VERSION 5.7 ;
  NOWIREEXTENSIONATPIN ON ;
  DIVIDERCHAR "/" ;
  BUSBITCHARS "[]" ;
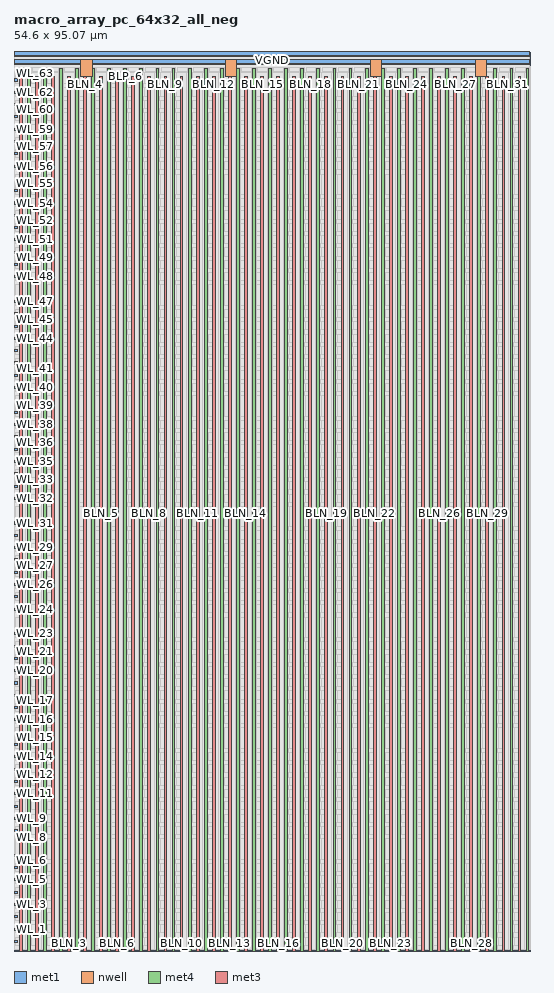
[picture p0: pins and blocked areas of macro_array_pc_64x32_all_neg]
MACRO macro_array_pc_64x32_all_neg
  CLASS BLOCK ;
  FOREIGN macro_array_pc_64x32_all_neg ;
  ORIGIN 0.000 0.000 ;
  SIZE 54.600 BY 95.070 ;
  PIN VPWR
    USE POWER ;
    PORT
      LAYER met1 ;
        RECT 0.000 93.750 54.500 94.150 ;
    END
    PORT
      LAYER nwell ;
        RECT 7.050 92.400 8.250 94.120 ;
    END
    PORT
      LAYER nwell ;
        RECT 22.350 92.400 23.550 94.120 ;
    END
    PORT
      LAYER nwell ;
        RECT 37.650 92.400 38.850 94.120 ;
    END
    PORT
      LAYER nwell ;
        RECT 48.700 92.400 49.900 94.120 ;
    END
    PORT
      LAYER met4 ;
        RECT 0.000 93.680 54.500 94.220 ;
    END
  END VPWR
  PIN VGND
    USE GROUND ;
    PORT
      LAYER met1 ;
        RECT 0.000 94.600 54.500 95.000 ;
    END
    PORT
      LAYER met4 ;
        RECT 0.000 94.530 54.500 95.070 ;
    END
  END VGND
  PIN BLP_0
    ANTENNADIFFAREA 0.121800 ;
    PORT
      LAYER met4 ;
        RECT 1.400 0.000 1.700 93.250 ;
    END
  END BLP_0
  PIN BLN_0
    ANTENNADIFFAREA 7.795200 ;
    PORT
      LAYER met3 ;
        RECT 0.550 0.000 0.850 92.400 ;
    END
  END BLN_0
  PIN BLP_1
    ANTENNADIFFAREA 0.121800 ;
    PORT
      LAYER met4 ;
        RECT 3.100 0.000 3.400 93.250 ;
    END
  END BLP_1
  PIN BLN_1
    ANTENNADIFFAREA 7.795200 ;
    PORT
      LAYER met3 ;
        RECT 2.250 0.000 2.550 92.400 ;
    END
  END BLN_1
  PIN BLP_2
    ANTENNADIFFAREA 0.121800 ;
    PORT
      LAYER met4 ;
        RECT 4.800 0.000 5.100 93.250 ;
    END
  END BLP_2
  PIN BLN_2
    ANTENNADIFFAREA 7.795200 ;
    PORT
      LAYER met3 ;
        RECT 3.950 0.000 4.250 92.400 ;
    END
  END BLN_2
  PIN BLP_3
    ANTENNADIFFAREA 0.121800 ;
    PORT
      LAYER met4 ;
        RECT 6.500 0.000 6.800 93.250 ;
    END
  END BLP_3
  PIN BLN_3
    ANTENNADIFFAREA 7.795200 ;
    PORT
      LAYER met3 ;
        RECT 5.650 0.000 5.950 92.400 ;
    END
  END BLN_3
  PIN BLP_4
    ANTENNADIFFAREA 0.121800 ;
    PORT
      LAYER met4 ;
        RECT 8.200 0.000 8.500 93.250 ;
    END
  END BLP_4
  PIN BLN_4
    ANTENNADIFFAREA 7.795200 ;
    PORT
      LAYER met3 ;
        RECT 7.350 0.000 7.650 92.400 ;
    END
  END BLN_4
  PIN BLP_5
    ANTENNADIFFAREA 0.121800 ;
    PORT
      LAYER met4 ;
        RECT 9.900 0.000 10.200 93.250 ;
    END
  END BLP_5
  PIN BLN_5
    ANTENNADIFFAREA 7.795200 ;
    PORT
      LAYER met3 ;
        RECT 9.050 0.000 9.350 92.400 ;
    END
  END BLN_5
  PIN BLP_6
    ANTENNADIFFAREA 0.121800 ;
    PORT
      LAYER met4 ;
        RECT 11.600 0.000 11.900 93.250 ;
    END
  END BLP_6
  PIN BLN_6
    ANTENNADIFFAREA 7.795200 ;
    PORT
      LAYER met3 ;
        RECT 10.750 0.000 11.050 92.400 ;
    END
  END BLN_6
  PIN BLP_7
    ANTENNADIFFAREA 0.121800 ;
    PORT
      LAYER met4 ;
        RECT 13.300 0.000 13.600 93.250 ;
    END
  END BLP_7
  PIN BLN_7
    ANTENNADIFFAREA 7.795200 ;
    PORT
      LAYER met3 ;
        RECT 12.450 0.000 12.750 92.400 ;
    END
  END BLN_7
  PIN BLP_8
    ANTENNADIFFAREA 0.121800 ;
    PORT
      LAYER met4 ;
        RECT 15.000 0.000 15.300 93.250 ;
    END
  END BLP_8
  PIN BLN_8
    ANTENNADIFFAREA 7.795200 ;
    PORT
      LAYER met3 ;
        RECT 14.150 0.000 14.450 92.400 ;
    END
  END BLN_8
  PIN BLP_9
    ANTENNADIFFAREA 0.121800 ;
    PORT
      LAYER met4 ;
        RECT 16.700 0.000 17.000 93.250 ;
    END
  END BLP_9
  PIN BLN_9
    ANTENNADIFFAREA 7.795200 ;
    PORT
      LAYER met3 ;
        RECT 15.850 0.000 16.150 92.400 ;
    END
  END BLN_9
  PIN BLP_10
    ANTENNADIFFAREA 0.121800 ;
    PORT
      LAYER met4 ;
        RECT 18.400 0.000 18.700 93.250 ;
    END
  END BLP_10
  PIN BLN_10
    ANTENNADIFFAREA 7.795200 ;
    PORT
      LAYER met3 ;
        RECT 17.550 0.000 17.850 92.400 ;
    END
  END BLN_10
  PIN BLP_11
    ANTENNADIFFAREA 0.121800 ;
    PORT
      LAYER met4 ;
        RECT 20.100 0.000 20.400 93.250 ;
    END
  END BLP_11
  PIN BLN_11
    ANTENNADIFFAREA 7.795200 ;
    PORT
      LAYER met3 ;
        RECT 19.250 0.000 19.550 92.400 ;
    END
  END BLN_11
  PIN BLP_12
    ANTENNADIFFAREA 0.121800 ;
    PORT
      LAYER met4 ;
        RECT 21.800 0.000 22.100 93.250 ;
    END
  END BLP_12
  PIN BLN_12
    ANTENNADIFFAREA 7.795200 ;
    PORT
      LAYER met3 ;
        RECT 20.950 0.000 21.250 92.400 ;
    END
  END BLN_12
  PIN BLP_13
    ANTENNADIFFAREA 0.121800 ;
    PORT
      LAYER met4 ;
        RECT 23.500 0.000 23.800 93.250 ;
    END
  END BLP_13
  PIN BLN_13
    ANTENNADIFFAREA 7.795200 ;
    PORT
      LAYER met3 ;
        RECT 22.650 0.000 22.950 92.400 ;
    END
  END BLN_13
  PIN BLP_14
    ANTENNADIFFAREA 0.121800 ;
    PORT
      LAYER met4 ;
        RECT 25.200 0.000 25.500 93.250 ;
    END
  END BLP_14
  PIN BLN_14
    ANTENNADIFFAREA 7.795200 ;
    PORT
      LAYER met3 ;
        RECT 24.350 0.000 24.650 92.400 ;
    END
  END BLN_14
  PIN BLP_15
    ANTENNADIFFAREA 0.121800 ;
    PORT
      LAYER met4 ;
        RECT 26.900 0.000 27.200 93.250 ;
    END
  END BLP_15
  PIN BLN_15
    ANTENNADIFFAREA 7.795200 ;
    PORT
      LAYER met3 ;
        RECT 26.050 0.000 26.350 92.400 ;
    END
  END BLN_15
  PIN BLP_16
    ANTENNADIFFAREA 0.121800 ;
    PORT
      LAYER met4 ;
        RECT 28.600 0.000 28.900 93.250 ;
    END
  END BLP_16
  PIN BLN_16
    ANTENNADIFFAREA 7.795200 ;
    PORT
      LAYER met3 ;
        RECT 27.750 0.000 28.050 92.400 ;
    END
  END BLN_16
  PIN BLP_17
    ANTENNADIFFAREA 0.121800 ;
    PORT
      LAYER met4 ;
        RECT 30.300 0.000 30.600 93.250 ;
    END
  END BLP_17
  PIN BLN_17
    ANTENNADIFFAREA 7.795200 ;
    PORT
      LAYER met3 ;
        RECT 29.450 0.000 29.750 92.400 ;
    END
  END BLN_17
  PIN BLP_18
    ANTENNADIFFAREA 0.121800 ;
    PORT
      LAYER met4 ;
        RECT 32.000 0.000 32.300 93.250 ;
    END
  END BLP_18
  PIN BLN_18
    ANTENNADIFFAREA 7.795200 ;
    PORT
      LAYER met3 ;
        RECT 31.150 0.000 31.450 92.400 ;
    END
  END BLN_18
  PIN BLP_19
    ANTENNADIFFAREA 0.121800 ;
    PORT
      LAYER met4 ;
        RECT 33.700 0.000 34.000 93.250 ;
    END
  END BLP_19
  PIN BLN_19
    ANTENNADIFFAREA 7.795200 ;
    PORT
      LAYER met3 ;
        RECT 32.850 0.000 33.150 92.400 ;
    END
  END BLN_19
  PIN BLP_20
    ANTENNADIFFAREA 0.121800 ;
    PORT
      LAYER met4 ;
        RECT 35.400 0.000 35.700 93.250 ;
    END
  END BLP_20
  PIN BLN_20
    ANTENNADIFFAREA 7.795200 ;
    PORT
      LAYER met3 ;
        RECT 34.550 0.000 34.850 92.400 ;
    END
  END BLN_20
  PIN BLP_21
    ANTENNADIFFAREA 0.121800 ;
    PORT
      LAYER met4 ;
        RECT 37.100 0.000 37.400 93.250 ;
    END
  END BLP_21
  PIN BLN_21
    ANTENNADIFFAREA 7.795200 ;
    PORT
      LAYER met3 ;
        RECT 36.250 0.000 36.550 92.400 ;
    END
  END BLN_21
  PIN BLP_22
    ANTENNADIFFAREA 0.121800 ;
    PORT
      LAYER met4 ;
        RECT 38.800 0.000 39.100 93.250 ;
    END
  END BLP_22
  PIN BLN_22
    ANTENNADIFFAREA 7.795200 ;
    PORT
      LAYER met3 ;
        RECT 37.950 0.000 38.250 92.400 ;
    END
  END BLN_22
  PIN BLP_23
    ANTENNADIFFAREA 0.121800 ;
    PORT
      LAYER met4 ;
        RECT 40.500 0.000 40.800 93.250 ;
    END
  END BLP_23
  PIN BLN_23
    ANTENNADIFFAREA 7.795200 ;
    PORT
      LAYER met3 ;
        RECT 39.650 0.000 39.950 92.400 ;
    END
  END BLN_23
  PIN BLP_24
    ANTENNADIFFAREA 0.121800 ;
    PORT
      LAYER met4 ;
        RECT 42.200 0.000 42.500 93.250 ;
    END
  END BLP_24
  PIN BLN_24
    ANTENNADIFFAREA 7.795200 ;
    PORT
      LAYER met3 ;
        RECT 41.350 0.000 41.650 92.400 ;
    END
  END BLN_24
  PIN BLP_25
    ANTENNADIFFAREA 0.121800 ;
    PORT
      LAYER met4 ;
        RECT 43.900 0.000 44.200 93.250 ;
    END
  END BLP_25
  PIN BLN_25
    ANTENNADIFFAREA 7.795200 ;
    PORT
      LAYER met3 ;
        RECT 43.050 0.000 43.350 92.400 ;
    END
  END BLN_25
  PIN BLP_26
    ANTENNADIFFAREA 0.121800 ;
    PORT
      LAYER met4 ;
        RECT 45.600 0.000 45.900 93.250 ;
    END
  END BLP_26
  PIN BLN_26
    ANTENNADIFFAREA 7.795200 ;
    PORT
      LAYER met3 ;
        RECT 44.750 0.000 45.050 92.400 ;
    END
  END BLN_26
  PIN BLP_27
    ANTENNADIFFAREA 0.121800 ;
    PORT
      LAYER met4 ;
        RECT 47.300 0.000 47.600 93.250 ;
    END
  END BLP_27
  PIN BLN_27
    ANTENNADIFFAREA 7.795200 ;
    PORT
      LAYER met3 ;
        RECT 46.450 0.000 46.750 92.400 ;
    END
  END BLN_27
  PIN BLP_28
    ANTENNADIFFAREA 0.121800 ;
    PORT
      LAYER met4 ;
        RECT 49.000 0.000 49.300 93.250 ;
    END
  END BLP_28
  PIN BLN_28
    ANTENNADIFFAREA 7.795200 ;
    PORT
      LAYER met3 ;
        RECT 48.150 0.000 48.450 92.400 ;
    END
  END BLN_28
  PIN BLP_29
    ANTENNADIFFAREA 0.121800 ;
    PORT
      LAYER met4 ;
        RECT 50.700 0.000 51.000 93.250 ;
    END
  END BLP_29
  PIN BLN_29
    ANTENNADIFFAREA 7.795200 ;
    PORT
      LAYER met3 ;
        RECT 49.850 0.000 50.150 92.400 ;
    END
  END BLN_29
  PIN BLP_30
    ANTENNADIFFAREA 0.121800 ;
    PORT
      LAYER met4 ;
        RECT 52.400 0.000 52.700 93.250 ;
    END
  END BLP_30
  PIN BLN_30
    ANTENNADIFFAREA 7.795200 ;
    PORT
      LAYER met3 ;
        RECT 51.550 0.000 51.850 92.400 ;
    END
  END BLN_30
  PIN BLP_31
    ANTENNADIFFAREA 0.121800 ;
    PORT
      LAYER met4 ;
        RECT 54.100 0.000 54.400 93.250 ;
    END
  END BLP_31
  PIN BLN_31
    ANTENNADIFFAREA 7.795200 ;
    PORT
      LAYER met3 ;
        RECT 53.250 0.000 53.550 92.400 ;
    END
  END BLN_31
  PIN WL_0
    ANTENNAGATEAREA 2.284800 ;
    PORT
      LAYER met1 ;
        RECT 0.000 0.900 0.390 1.120 ;
    END
  END WL_0
  PIN WL_1
    ANTENNAGATEAREA 2.284800 ;
    PORT
      LAYER met1 ;
        RECT 0.000 2.200 0.390 2.420 ;
    END
  END WL_1
  PIN WL_2
    ANTENNAGATEAREA 2.284800 ;
    PORT
      LAYER met1 ;
        RECT 0.000 3.500 0.390 3.720 ;
    END
  END WL_2
  PIN WL_3
    ANTENNAGATEAREA 2.284800 ;
    PORT
      LAYER met1 ;
        RECT 0.000 4.800 0.390 5.020 ;
    END
  END WL_3
  PIN WL_4
    ANTENNAGATEAREA 2.284800 ;
    PORT
      LAYER met1 ;
        RECT 0.000 6.100 0.390 6.320 ;
    END
  END WL_4
  PIN WL_5
    ANTENNAGATEAREA 2.284800 ;
    PORT
      LAYER met1 ;
        RECT 0.000 7.400 0.390 7.620 ;
    END
  END WL_5
  PIN WL_6
    ANTENNAGATEAREA 2.284800 ;
    PORT
      LAYER met1 ;
        RECT 0.000 8.700 0.390 8.920 ;
    END
  END WL_6
  PIN WL_7
    ANTENNAGATEAREA 2.284800 ;
    PORT
      LAYER met1 ;
        RECT 0.000 10.000 0.390 10.220 ;
    END
  END WL_7
  PIN WL_8
    ANTENNAGATEAREA 2.284800 ;
    PORT
      LAYER met1 ;
        RECT 0.000 12.600 0.390 12.820 ;
    END
  END WL_8
  PIN WL_9
    ANTENNAGATEAREA 2.284800 ;
    PORT
      LAYER met1 ;
        RECT 0.000 13.900 0.390 14.120 ;
    END
  END WL_9
  PIN WL_10
    ANTENNAGATEAREA 2.284800 ;
    PORT
      LAYER met1 ;
        RECT 0.000 15.200 0.390 15.420 ;
    END
  END WL_10
  PIN WL_11
    ANTENNAGATEAREA 2.284800 ;
    PORT
      LAYER met1 ;
        RECT 0.000 16.500 0.390 16.720 ;
    END
  END WL_11
  PIN WL_12
    ANTENNAGATEAREA 2.284800 ;
    PORT
      LAYER met1 ;
        RECT 0.000 17.800 0.390 18.020 ;
    END
  END WL_12
  PIN WL_13
    ANTENNAGATEAREA 2.284800 ;
    PORT
      LAYER met1 ;
        RECT 0.000 19.100 0.390 19.320 ;
    END
  END WL_13
  PIN WL_14
    ANTENNAGATEAREA 2.284800 ;
    PORT
      LAYER met1 ;
        RECT 0.000 20.400 0.390 20.620 ;
    END
  END WL_14
  PIN WL_15
    ANTENNAGATEAREA 2.284800 ;
    PORT
      LAYER met1 ;
        RECT 0.000 21.700 0.390 21.920 ;
    END
  END WL_15
  PIN WL_16
    ANTENNAGATEAREA 2.284800 ;
    PORT
      LAYER met1 ;
        RECT 0.000 24.300 0.390 24.520 ;
    END
  END WL_16
  PIN WL_17
    ANTENNAGATEAREA 2.284800 ;
    PORT
      LAYER met1 ;
        RECT 0.000 25.600 0.390 25.820 ;
    END
  END WL_17
  PIN WL_18
    ANTENNAGATEAREA 2.284800 ;
    PORT
      LAYER met1 ;
        RECT 0.000 26.900 0.390 27.120 ;
    END
  END WL_18
  PIN WL_19
    ANTENNAGATEAREA 2.284800 ;
    PORT
      LAYER met1 ;
        RECT 0.000 28.200 0.390 28.420 ;
    END
  END WL_19
  PIN WL_20
    ANTENNAGATEAREA 2.284800 ;
    PORT
      LAYER met1 ;
        RECT 0.000 29.500 0.390 29.720 ;
    END
  END WL_20
  PIN WL_21
    ANTENNAGATEAREA 2.284800 ;
    PORT
      LAYER met1 ;
        RECT 0.000 30.800 0.390 31.020 ;
    END
  END WL_21
  PIN WL_22
    ANTENNAGATEAREA 2.284800 ;
    PORT
      LAYER met1 ;
        RECT 0.000 32.100 0.390 32.320 ;
    END
  END WL_22
  PIN WL_23
    ANTENNAGATEAREA 2.284800 ;
    PORT
      LAYER met1 ;
        RECT 0.000 33.400 0.390 33.620 ;
    END
  END WL_23
  PIN WL_24
    ANTENNAGATEAREA 2.284800 ;
    PORT
      LAYER met1 ;
        RECT 0.000 36.000 0.390 36.220 ;
    END
  END WL_24
  PIN WL_25
    ANTENNAGATEAREA 2.284800 ;
    PORT
      LAYER met1 ;
        RECT 0.000 37.300 0.390 37.520 ;
    END
  END WL_25
  PIN WL_26
    ANTENNAGATEAREA 2.284800 ;
    PORT
      LAYER met1 ;
        RECT 0.000 38.600 0.390 38.820 ;
    END
  END WL_26
  PIN WL_27
    ANTENNAGATEAREA 2.284800 ;
    PORT
      LAYER met1 ;
        RECT 0.000 39.900 0.390 40.120 ;
    END
  END WL_27
  PIN WL_28
    ANTENNAGATEAREA 2.284800 ;
    PORT
      LAYER met1 ;
        RECT 0.000 41.200 0.390 41.420 ;
    END
  END WL_28
  PIN WL_29
    ANTENNAGATEAREA 2.284800 ;
    PORT
      LAYER met1 ;
        RECT 0.000 42.500 0.390 42.720 ;
    END
  END WL_29
  PIN WL_30
    ANTENNAGATEAREA 2.284800 ;
    PORT
      LAYER met1 ;
        RECT 0.000 43.800 0.390 44.020 ;
    END
  END WL_30
  PIN WL_31
    ANTENNAGATEAREA 2.284800 ;
    PORT
      LAYER met1 ;
        RECT 0.000 45.100 0.390 45.320 ;
    END
  END WL_31
  PIN WL_32
    ANTENNAGATEAREA 2.284800 ;
    PORT
      LAYER met1 ;
        RECT 0.000 47.700 0.390 47.920 ;
    END
  END WL_32
  PIN WL_33
    ANTENNAGATEAREA 2.284800 ;
    PORT
      LAYER met1 ;
        RECT 0.000 49.000 0.390 49.220 ;
    END
  END WL_33
  PIN WL_34
    ANTENNAGATEAREA 2.284800 ;
    PORT
      LAYER met1 ;
        RECT 0.000 50.300 0.390 50.520 ;
    END
  END WL_34
  PIN WL_35
    ANTENNAGATEAREA 2.284800 ;
    PORT
      LAYER met1 ;
        RECT 0.000 51.600 0.390 51.820 ;
    END
  END WL_35
  PIN WL_36
    ANTENNAGATEAREA 2.284800 ;
    PORT
      LAYER met1 ;
        RECT 0.000 52.900 0.390 53.120 ;
    END
  END WL_36
  PIN WL_37
    ANTENNAGATEAREA 2.284800 ;
    PORT
      LAYER met1 ;
        RECT 0.000 54.200 0.390 54.420 ;
    END
  END WL_37
  PIN WL_38
    ANTENNAGATEAREA 2.284800 ;
    PORT
      LAYER met1 ;
        RECT 0.000 55.500 0.390 55.720 ;
    END
  END WL_38
  PIN WL_39
    ANTENNAGATEAREA 2.284800 ;
    PORT
      LAYER met1 ;
        RECT 0.000 56.800 0.390 57.020 ;
    END
  END WL_39
  PIN WL_40
    ANTENNAGATEAREA 2.284800 ;
    PORT
      LAYER met1 ;
        RECT 0.000 59.400 0.390 59.620 ;
    END
  END WL_40
  PIN WL_41
    ANTENNAGATEAREA 2.284800 ;
    PORT
      LAYER met1 ;
        RECT 0.000 60.700 0.390 60.920 ;
    END
  END WL_41
  PIN WL_42
    ANTENNAGATEAREA 2.284800 ;
    PORT
      LAYER met1 ;
        RECT 0.000 62.000 0.390 62.220 ;
    END
  END WL_42
  PIN WL_43
    ANTENNAGATEAREA 2.284800 ;
    PORT
      LAYER met1 ;
        RECT 0.000 63.300 0.390 63.520 ;
    END
  END WL_43
  PIN WL_44
    ANTENNAGATEAREA 2.284800 ;
    PORT
      LAYER met1 ;
        RECT 0.000 64.600 0.390 64.820 ;
    END
  END WL_44
  PIN WL_45
    ANTENNAGATEAREA 2.284800 ;
    PORT
      LAYER met1 ;
        RECT 0.000 65.900 0.390 66.120 ;
    END
  END WL_45
  PIN WL_46
    ANTENNAGATEAREA 2.284800 ;
    PORT
      LAYER met1 ;
        RECT 0.000 67.200 0.390 67.420 ;
    END
  END WL_46
  PIN WL_47
    ANTENNAGATEAREA 2.284800 ;
    PORT
      LAYER met1 ;
        RECT 0.000 68.500 0.390 68.720 ;
    END
  END WL_47
  PIN WL_48
    ANTENNAGATEAREA 2.284800 ;
    PORT
      LAYER met1 ;
        RECT 0.000 71.100 0.390 71.320 ;
    END
  END WL_48
  PIN WL_49
    ANTENNAGATEAREA 2.284800 ;
    PORT
      LAYER met1 ;
        RECT 0.000 72.400 0.390 72.620 ;
    END
  END WL_49
  PIN WL_50
    ANTENNAGATEAREA 2.284800 ;
    PORT
      LAYER met1 ;
        RECT 0.000 73.700 0.390 73.920 ;
    END
  END WL_50
  PIN WL_51
    ANTENNAGATEAREA 2.284800 ;
    PORT
      LAYER met1 ;
        RECT 0.000 75.000 0.390 75.220 ;
    END
  END WL_51
  PIN WL_52
    ANTENNAGATEAREA 2.284800 ;
    PORT
      LAYER met1 ;
        RECT 0.000 76.300 0.390 76.520 ;
    END
  END WL_52
  PIN WL_53
    ANTENNAGATEAREA 2.284800 ;
    PORT
      LAYER met1 ;
        RECT 0.000 77.600 0.390 77.820 ;
    END
  END WL_53
  PIN WL_54
    ANTENNAGATEAREA 2.284800 ;
    PORT
      LAYER met1 ;
        RECT 0.000 78.900 0.390 79.120 ;
    END
  END WL_54
  PIN WL_55
    ANTENNAGATEAREA 2.284800 ;
    PORT
      LAYER met1 ;
        RECT 0.000 80.200 0.390 80.420 ;
    END
  END WL_55
  PIN WL_56
    ANTENNAGATEAREA 2.284800 ;
    PORT
      LAYER met1 ;
        RECT 0.000 82.800 0.390 83.020 ;
    END
  END WL_56
  PIN WL_57
    ANTENNAGATEAREA 2.284800 ;
    PORT
      LAYER met1 ;
        RECT 0.000 84.100 0.390 84.320 ;
    END
  END WL_57
  PIN WL_58
    ANTENNAGATEAREA 2.284800 ;
    PORT
      LAYER met1 ;
        RECT 0.000 85.400 0.390 85.620 ;
    END
  END WL_58
  PIN WL_59
    ANTENNAGATEAREA 2.284800 ;
    PORT
      LAYER met1 ;
        RECT 0.000 86.700 0.390 86.920 ;
    END
  END WL_59
  PIN WL_60
    ANTENNAGATEAREA 2.284800 ;
    PORT
      LAYER met1 ;
        RECT 0.000 88.000 0.390 88.220 ;
    END
  END WL_60
  PIN WL_61
    ANTENNAGATEAREA 2.284800 ;
    PORT
      LAYER met1 ;
        RECT 0.000 89.300 0.390 89.520 ;
    END
  END WL_61
  PIN WL_62
    ANTENNAGATEAREA 2.284800 ;
    PORT
      LAYER met1 ;
        RECT 0.000 90.600 0.390 90.820 ;
    END
  END WL_62
  PIN WL_63
    ANTENNAGATEAREA 2.284800 ;
    PORT
      LAYER met1 ;
        RECT 0.000 91.900 0.390 92.120 ;
    END
  END WL_63
  OBS
      LAYER nwell ;
        RECT 0.100 92.400 5.780 93.550 ;
        RECT 9.520 92.400 21.080 93.550 ;
        RECT 24.820 92.400 36.380 93.550 ;
        RECT 40.120 92.400 47.430 93.550 ;
        RECT 51.170 92.400 54.040 93.550 ;
      LAYER li1 ;
        RECT 0.140 0.160 53.750 93.845 ;
      LAYER met1 ;
        RECT 0.080 92.400 54.600 93.470 ;
        RECT 0.670 91.620 54.600 92.400 ;
        RECT 0.080 91.100 54.600 91.620 ;
        RECT 0.670 90.320 54.600 91.100 ;
        RECT 0.080 89.800 54.600 90.320 ;
        RECT 0.670 89.020 54.600 89.800 ;
        RECT 0.080 88.500 54.600 89.020 ;
        RECT 0.670 87.720 54.600 88.500 ;
        RECT 0.080 87.200 54.600 87.720 ;
        RECT 0.670 86.420 54.600 87.200 ;
        RECT 0.080 85.900 54.600 86.420 ;
        RECT 0.670 85.120 54.600 85.900 ;
        RECT 0.080 84.600 54.600 85.120 ;
        RECT 0.670 83.820 54.600 84.600 ;
        RECT 0.080 83.300 54.600 83.820 ;
        RECT 0.670 82.520 54.600 83.300 ;
        RECT 0.080 80.700 54.600 82.520 ;
        RECT 0.670 79.920 54.600 80.700 ;
        RECT 0.080 79.400 54.600 79.920 ;
        RECT 0.670 78.620 54.600 79.400 ;
        RECT 0.080 78.100 54.600 78.620 ;
        RECT 0.670 77.320 54.600 78.100 ;
        RECT 0.080 76.800 54.600 77.320 ;
        RECT 0.670 76.020 54.600 76.800 ;
        RECT 0.080 75.500 54.600 76.020 ;
        RECT 0.670 74.720 54.600 75.500 ;
        RECT 0.080 74.200 54.600 74.720 ;
        RECT 0.670 73.420 54.600 74.200 ;
        RECT 0.080 72.900 54.600 73.420 ;
        RECT 0.670 72.120 54.600 72.900 ;
        RECT 0.080 71.600 54.600 72.120 ;
        RECT 0.670 70.820 54.600 71.600 ;
        RECT 0.080 69.000 54.600 70.820 ;
        RECT 0.670 68.220 54.600 69.000 ;
        RECT 0.080 67.700 54.600 68.220 ;
        RECT 0.670 66.920 54.600 67.700 ;
        RECT 0.080 66.400 54.600 66.920 ;
        RECT 0.670 65.620 54.600 66.400 ;
        RECT 0.080 65.100 54.600 65.620 ;
        RECT 0.670 64.320 54.600 65.100 ;
        RECT 0.080 63.800 54.600 64.320 ;
        RECT 0.670 63.020 54.600 63.800 ;
        RECT 0.080 62.500 54.600 63.020 ;
        RECT 0.670 61.720 54.600 62.500 ;
        RECT 0.080 61.200 54.600 61.720 ;
        RECT 0.670 60.420 54.600 61.200 ;
        RECT 0.080 59.900 54.600 60.420 ;
        RECT 0.670 59.120 54.600 59.900 ;
        RECT 0.080 57.300 54.600 59.120 ;
        RECT 0.670 56.520 54.600 57.300 ;
        RECT 0.080 56.000 54.600 56.520 ;
        RECT 0.670 55.220 54.600 56.000 ;
        RECT 0.080 54.700 54.600 55.220 ;
        RECT 0.670 53.920 54.600 54.700 ;
        RECT 0.080 53.400 54.600 53.920 ;
        RECT 0.670 52.620 54.600 53.400 ;
        RECT 0.080 52.100 54.600 52.620 ;
        RECT 0.670 51.320 54.600 52.100 ;
        RECT 0.080 50.800 54.600 51.320 ;
        RECT 0.670 50.020 54.600 50.800 ;
        RECT 0.080 49.500 54.600 50.020 ;
        RECT 0.670 48.720 54.600 49.500 ;
        RECT 0.080 48.200 54.600 48.720 ;
        RECT 0.670 47.420 54.600 48.200 ;
        RECT 0.080 45.600 54.600 47.420 ;
        RECT 0.670 44.820 54.600 45.600 ;
        RECT 0.080 44.300 54.600 44.820 ;
        RECT 0.670 43.520 54.600 44.300 ;
        RECT 0.080 43.000 54.600 43.520 ;
        RECT 0.670 42.220 54.600 43.000 ;
        RECT 0.080 41.700 54.600 42.220 ;
        RECT 0.670 40.920 54.600 41.700 ;
        RECT 0.080 40.400 54.600 40.920 ;
        RECT 0.670 39.620 54.600 40.400 ;
        RECT 0.080 39.100 54.600 39.620 ;
        RECT 0.670 38.320 54.600 39.100 ;
        RECT 0.080 37.800 54.600 38.320 ;
        RECT 0.670 37.020 54.600 37.800 ;
        RECT 0.080 36.500 54.600 37.020 ;
        RECT 0.670 35.720 54.600 36.500 ;
        RECT 0.080 33.900 54.600 35.720 ;
        RECT 0.670 33.120 54.600 33.900 ;
        RECT 0.080 32.600 54.600 33.120 ;
        RECT 0.670 31.820 54.600 32.600 ;
        RECT 0.080 31.300 54.600 31.820 ;
        RECT 0.670 30.520 54.600 31.300 ;
        RECT 0.080 30.000 54.600 30.520 ;
        RECT 0.670 29.220 54.600 30.000 ;
        RECT 0.080 28.700 54.600 29.220 ;
        RECT 0.670 27.920 54.600 28.700 ;
        RECT 0.080 27.400 54.600 27.920 ;
        RECT 0.670 26.620 54.600 27.400 ;
        RECT 0.080 26.100 54.600 26.620 ;
        RECT 0.670 25.320 54.600 26.100 ;
        RECT 0.080 24.800 54.600 25.320 ;
        RECT 0.670 24.020 54.600 24.800 ;
        RECT 0.080 22.200 54.600 24.020 ;
        RECT 0.670 21.420 54.600 22.200 ;
        RECT 0.080 20.900 54.600 21.420 ;
        RECT 0.670 20.120 54.600 20.900 ;
        RECT 0.080 19.600 54.600 20.120 ;
        RECT 0.670 18.820 54.600 19.600 ;
        RECT 0.080 18.300 54.600 18.820 ;
        RECT 0.670 17.520 54.600 18.300 ;
        RECT 0.080 17.000 54.600 17.520 ;
        RECT 0.670 16.220 54.600 17.000 ;
        RECT 0.080 15.700 54.600 16.220 ;
        RECT 0.670 14.920 54.600 15.700 ;
        RECT 0.080 14.400 54.600 14.920 ;
        RECT 0.670 13.620 54.600 14.400 ;
        RECT 0.080 13.100 54.600 13.620 ;
        RECT 0.670 12.320 54.600 13.100 ;
        RECT 0.080 10.500 54.600 12.320 ;
        RECT 0.670 9.720 54.600 10.500 ;
        RECT 0.080 9.200 54.600 9.720 ;
        RECT 0.670 8.420 54.600 9.200 ;
        RECT 0.080 7.900 54.600 8.420 ;
        RECT 0.670 7.120 54.600 7.900 ;
        RECT 0.080 6.600 54.600 7.120 ;
        RECT 0.670 5.820 54.600 6.600 ;
        RECT 0.080 5.300 54.600 5.820 ;
        RECT 0.670 4.520 54.600 5.300 ;
        RECT 0.080 4.000 54.600 4.520 ;
        RECT 0.670 3.220 54.600 4.000 ;
        RECT 0.080 2.700 54.600 3.220 ;
        RECT 0.670 1.920 54.600 2.700 ;
        RECT 0.080 1.400 54.600 1.920 ;
        RECT 0.670 0.620 54.600 1.400 ;
        RECT 0.080 0.170 54.600 0.620 ;
      LAYER met2 ;
        RECT 0.080 0.170 54.500 95.060 ;
      LAYER met3 ;
        RECT 0.080 92.800 54.500 95.070 ;
        RECT 0.080 0.170 0.150 92.800 ;
        RECT 1.250 0.170 1.850 92.800 ;
        RECT 2.950 0.170 3.550 92.800 ;
        RECT 4.650 0.170 5.250 92.800 ;
        RECT 6.350 0.170 6.950 92.800 ;
        RECT 8.050 0.170 8.650 92.800 ;
        RECT 9.750 0.170 10.350 92.800 ;
        RECT 11.450 0.170 12.050 92.800 ;
        RECT 13.150 0.170 13.750 92.800 ;
        RECT 14.850 0.170 15.450 92.800 ;
        RECT 16.550 0.170 17.150 92.800 ;
        RECT 18.250 0.170 18.850 92.800 ;
        RECT 19.950 0.170 20.550 92.800 ;
        RECT 21.650 0.170 22.250 92.800 ;
        RECT 23.350 0.170 23.950 92.800 ;
        RECT 25.050 0.170 25.650 92.800 ;
        RECT 26.750 0.170 27.350 92.800 ;
        RECT 28.450 0.170 29.050 92.800 ;
        RECT 30.150 0.170 30.750 92.800 ;
        RECT 31.850 0.170 32.450 92.800 ;
        RECT 33.550 0.170 34.150 92.800 ;
        RECT 35.250 0.170 35.850 92.800 ;
        RECT 36.950 0.170 37.550 92.800 ;
        RECT 38.650 0.170 39.250 92.800 ;
        RECT 40.350 0.170 40.950 92.800 ;
        RECT 42.050 0.170 42.650 92.800 ;
        RECT 43.750 0.170 44.350 92.800 ;
        RECT 45.450 0.170 46.050 92.800 ;
        RECT 47.150 0.170 47.750 92.800 ;
        RECT 48.850 0.170 49.450 92.800 ;
        RECT 50.550 0.170 51.150 92.800 ;
        RECT 52.250 0.170 52.850 92.800 ;
        RECT 53.950 0.170 54.500 92.800 ;
      LAYER met4 ;
        RECT 2.100 92.820 2.700 93.280 ;
        RECT 3.800 92.820 4.400 93.280 ;
        RECT 5.500 92.820 6.100 93.280 ;
        RECT 7.200 92.820 7.800 93.280 ;
        RECT 8.900 92.820 9.500 93.280 ;
        RECT 10.600 92.820 11.200 93.280 ;
        RECT 12.300 92.820 12.900 93.280 ;
        RECT 14.000 92.820 14.600 93.280 ;
        RECT 15.700 92.820 16.300 93.280 ;
        RECT 17.400 92.820 18.000 93.280 ;
        RECT 19.100 92.820 19.700 93.280 ;
        RECT 20.800 92.820 21.400 93.280 ;
        RECT 22.500 92.820 23.100 93.280 ;
        RECT 24.200 92.820 24.800 93.280 ;
        RECT 25.900 92.820 26.500 93.280 ;
        RECT 27.600 92.820 28.200 93.280 ;
        RECT 29.300 92.820 29.900 93.280 ;
        RECT 31.000 92.820 31.600 93.280 ;
        RECT 32.700 92.820 33.300 93.280 ;
        RECT 34.400 92.820 35.000 93.280 ;
        RECT 36.100 92.820 36.700 93.280 ;
        RECT 37.800 92.820 38.400 93.280 ;
        RECT 39.500 92.820 40.100 93.280 ;
        RECT 41.200 92.820 41.800 93.280 ;
        RECT 42.900 92.820 43.500 93.280 ;
        RECT 44.600 92.820 45.200 93.280 ;
        RECT 46.300 92.820 46.900 93.280 ;
        RECT 48.000 92.820 48.600 93.280 ;
        RECT 49.700 92.820 50.300 93.280 ;
        RECT 51.400 92.820 52.000 93.280 ;
        RECT 53.100 92.820 53.700 93.280 ;
      LAYER met2 ;
        RECT 27.280 0.170 27.775 0.610 ;
        RECT 27.280 1.470 27.775 1.910 ;
        RECT 27.280 2.770 27.775 3.210 ;
        RECT 27.280 4.070 27.775 4.510 ;
        RECT 27.280 5.370 27.775 5.810 ;
        RECT 27.280 6.670 27.775 7.110 ;
        RECT 27.280 7.970 27.775 8.410 ;
        RECT 27.280 9.270 27.775 9.710 ;
        RECT 27.280 11.870 27.775 12.310 ;
        RECT 27.280 13.170 27.775 13.610 ;
        RECT 27.280 14.470 27.775 14.910 ;
        RECT 27.280 15.770 27.775 16.210 ;
        RECT 27.280 17.070 27.775 17.510 ;
        RECT 27.280 18.370 27.775 18.810 ;
        RECT 27.280 19.670 27.775 20.110 ;
        RECT 27.280 20.970 27.775 21.410 ;
        RECT 27.280 23.570 27.775 24.010 ;
        RECT 27.280 24.870 27.775 25.310 ;
        RECT 27.280 26.170 27.775 26.610 ;
        RECT 27.280 27.470 27.775 27.910 ;
        RECT 27.280 28.770 27.775 29.210 ;
        RECT 27.280 30.070 27.775 30.510 ;
        RECT 27.280 31.370 27.775 31.810 ;
        RECT 27.280 32.670 27.775 33.110 ;
        RECT 27.280 35.270 27.775 35.710 ;
        RECT 27.280 36.570 27.775 37.010 ;
        RECT 27.280 37.870 27.775 38.310 ;
        RECT 27.280 39.170 27.775 39.610 ;
        RECT 27.280 40.470 27.775 40.910 ;
        RECT 27.280 41.770 27.775 42.210 ;
        RECT 27.280 43.070 27.775 43.510 ;
        RECT 27.280 44.370 27.775 44.810 ;
        RECT 27.280 46.970 27.775 47.410 ;
        RECT 27.280 48.270 27.775 48.710 ;
        RECT 27.280 49.570 27.775 50.010 ;
        RECT 27.280 50.870 27.775 51.310 ;
        RECT 27.280 52.170 27.775 52.610 ;
        RECT 27.280 53.470 27.775 53.910 ;
        RECT 27.280 54.770 27.775 55.210 ;
        RECT 27.280 56.070 27.775 56.510 ;
        RECT 27.280 58.670 27.775 59.110 ;
        RECT 27.280 59.970 27.775 60.410 ;
        RECT 27.280 61.270 27.775 61.710 ;
        RECT 27.280 62.570 27.775 63.010 ;
        RECT 27.280 63.870 27.775 64.310 ;
        RECT 27.280 65.170 27.775 65.610 ;
        RECT 27.280 66.470 27.775 66.910 ;
        RECT 27.280 67.770 27.775 68.210 ;
        RECT 27.280 70.370 27.775 70.810 ;
        RECT 27.280 71.670 27.775 72.110 ;
        RECT 27.280 72.970 27.775 73.410 ;
        RECT 27.280 74.270 27.775 74.710 ;
        RECT 27.280 75.570 27.775 76.010 ;
        RECT 27.280 76.870 27.775 77.310 ;
        RECT 27.280 78.170 27.775 78.610 ;
        RECT 27.280 79.470 27.775 79.910 ;
        RECT 27.280 82.070 27.775 82.510 ;
        RECT 27.280 83.370 27.775 83.810 ;
        RECT 27.280 84.670 27.775 85.110 ;
        RECT 27.280 85.970 27.775 86.410 ;
        RECT 27.280 87.270 27.775 87.710 ;
        RECT 27.280 88.570 27.775 89.010 ;
        RECT 27.280 89.870 27.775 90.310 ;
        RECT 27.280 91.170 27.775 91.610 ;
        RECT 25.745 92.870 27.300 93.340 ;
        RECT 40.880 50.870 41.375 51.310 ;
        RECT 40.880 52.170 41.375 52.610 ;
        RECT 40.880 53.470 41.375 53.910 ;
        RECT 40.880 54.770 41.375 55.210 ;
        RECT 40.880 56.070 41.375 56.510 ;
        RECT 40.880 58.670 41.375 59.110 ;
        RECT 40.880 48.270 41.375 48.710 ;
        RECT 40.880 59.970 41.375 60.410 ;
        RECT 40.880 61.270 41.375 61.710 ;
        RECT 40.880 62.570 41.375 63.010 ;
        RECT 40.880 63.870 41.375 64.310 ;
        RECT 40.880 65.170 41.375 65.610 ;
        RECT 40.880 66.470 41.375 66.910 ;
        RECT 40.880 67.770 41.375 68.210 ;
        RECT 40.880 70.370 41.375 70.810 ;
        RECT 40.880 71.670 41.375 72.110 ;
        RECT 40.880 72.970 41.375 73.410 ;
        RECT 40.880 74.270 41.375 74.710 ;
        RECT 40.880 75.570 41.375 76.010 ;
        RECT 40.880 76.870 41.375 77.310 ;
        RECT 40.880 78.170 41.375 78.610 ;
        RECT 40.880 79.470 41.375 79.910 ;
        RECT 40.880 82.070 41.375 82.510 ;
        RECT 40.880 49.570 41.375 50.010 ;
        RECT 40.880 83.370 41.375 83.810 ;
        RECT 40.880 84.670 41.375 85.110 ;
        RECT 40.880 85.970 41.375 86.410 ;
        RECT 40.880 87.270 41.375 87.710 ;
        RECT 40.880 88.570 41.375 89.010 ;
        RECT 40.880 89.870 41.375 90.310 ;
        RECT 40.880 91.170 41.375 91.610 ;
        RECT 39.345 92.870 40.900 93.340 ;
        RECT 47.680 74.270 48.175 74.710 ;
        RECT 47.680 75.570 48.175 76.010 ;
        RECT 47.680 71.670 48.175 72.110 ;
        RECT 47.680 76.870 48.175 77.310 ;
        RECT 47.680 78.170 48.175 78.610 ;
        RECT 47.680 79.470 48.175 79.910 ;
        RECT 47.680 82.070 48.175 82.510 ;
        RECT 47.680 83.370 48.175 83.810 ;
        RECT 47.680 84.670 48.175 85.110 ;
        RECT 47.680 85.970 48.175 86.410 ;
        RECT 47.680 72.970 48.175 73.410 ;
        RECT 47.680 87.270 48.175 87.710 ;
        RECT 47.680 88.570 48.175 89.010 ;
        RECT 47.680 89.870 48.175 90.310 ;
        RECT 47.680 91.170 48.175 91.610 ;
        RECT 46.145 92.870 47.700 93.340 ;
        RECT 49.380 85.970 49.875 86.410 ;
        RECT 51.080 85.970 51.575 86.410 ;
        RECT 52.780 85.970 53.275 86.410 ;
        RECT 52.780 83.370 53.275 83.810 ;
        RECT 49.380 83.370 49.875 83.810 ;
        RECT 49.380 87.270 49.875 87.710 ;
        RECT 51.080 87.270 51.575 87.710 ;
        RECT 52.780 87.270 53.275 87.710 ;
        RECT 49.380 84.670 49.875 85.110 ;
        RECT 49.380 88.570 49.875 89.010 ;
        RECT 51.080 88.570 51.575 89.010 ;
        RECT 52.780 88.570 53.275 89.010 ;
        RECT 51.080 84.670 51.575 85.110 ;
        RECT 49.380 89.870 49.875 90.310 ;
        RECT 51.080 89.870 51.575 90.310 ;
        RECT 52.780 89.870 53.275 90.310 ;
        RECT 52.780 84.670 53.275 85.110 ;
        RECT 49.380 91.170 49.875 91.610 ;
        RECT 51.080 91.170 51.575 91.610 ;
        RECT 52.780 91.170 53.275 91.610 ;
        RECT 51.080 83.370 51.575 83.810 ;
        RECT 47.845 92.870 49.400 93.340 ;
        RECT 49.545 92.870 51.100 93.340 ;
        RECT 51.245 92.870 52.800 93.340 ;
        RECT 52.945 92.870 54.500 93.340 ;
        RECT 44.280 83.370 44.775 83.810 ;
        RECT 45.980 83.370 46.475 83.810 ;
        RECT 42.580 89.870 43.075 90.310 ;
        RECT 44.280 89.870 44.775 90.310 ;
        RECT 45.980 89.870 46.475 90.310 ;
        RECT 42.580 83.370 43.075 83.810 ;
        RECT 42.580 87.270 43.075 87.710 ;
        RECT 44.280 87.270 44.775 87.710 ;
        RECT 45.980 87.270 46.475 87.710 ;
        RECT 42.580 91.170 43.075 91.610 ;
        RECT 44.280 91.170 44.775 91.610 ;
        RECT 45.980 91.170 46.475 91.610 ;
        RECT 42.580 84.670 43.075 85.110 ;
        RECT 42.580 85.970 43.075 86.410 ;
        RECT 44.280 85.970 44.775 86.410 ;
        RECT 45.980 85.970 46.475 86.410 ;
        RECT 41.045 92.870 42.600 93.340 ;
        RECT 42.745 92.870 44.300 93.340 ;
        RECT 44.445 92.870 46.000 93.340 ;
        RECT 42.580 88.570 43.075 89.010 ;
        RECT 44.280 88.570 44.775 89.010 ;
        RECT 45.980 88.570 46.475 89.010 ;
        RECT 44.280 84.670 44.775 85.110 ;
        RECT 45.980 84.670 46.475 85.110 ;
        RECT 45.980 79.470 46.475 79.910 ;
        RECT 45.980 72.970 46.475 73.410 ;
        RECT 42.580 75.570 43.075 76.010 ;
        RECT 42.580 82.070 43.075 82.510 ;
        RECT 44.280 82.070 44.775 82.510 ;
        RECT 45.980 82.070 46.475 82.510 ;
        RECT 44.280 75.570 44.775 76.010 ;
        RECT 42.580 71.670 43.075 72.110 ;
        RECT 42.580 72.970 43.075 73.410 ;
        RECT 45.980 75.570 46.475 76.010 ;
        RECT 44.280 74.270 44.775 74.710 ;
        RECT 45.980 74.270 46.475 74.710 ;
        RECT 42.580 76.870 43.075 77.310 ;
        RECT 44.280 76.870 44.775 77.310 ;
        RECT 45.980 76.870 46.475 77.310 ;
        RECT 44.280 71.670 44.775 72.110 ;
        RECT 42.580 74.270 43.075 74.710 ;
        RECT 44.280 72.970 44.775 73.410 ;
        RECT 42.580 78.170 43.075 78.610 ;
        RECT 44.280 78.170 44.775 78.610 ;
        RECT 45.980 78.170 46.475 78.610 ;
        RECT 45.980 71.670 46.475 72.110 ;
        RECT 42.580 79.470 43.075 79.910 ;
        RECT 44.280 79.470 44.775 79.910 ;
        RECT 51.080 82.070 51.575 82.510 ;
        RECT 52.780 82.070 53.275 82.510 ;
        RECT 49.380 74.270 49.875 74.710 ;
        RECT 51.080 74.270 51.575 74.710 ;
        RECT 49.380 78.170 49.875 78.610 ;
        RECT 51.080 78.170 51.575 78.610 ;
        RECT 52.780 78.170 53.275 78.610 ;
        RECT 52.780 72.970 53.275 73.410 ;
        RECT 51.080 71.670 51.575 72.110 ;
        RECT 49.380 75.570 49.875 76.010 ;
        RECT 51.080 75.570 51.575 76.010 ;
        RECT 49.380 76.870 49.875 77.310 ;
        RECT 51.080 76.870 51.575 77.310 ;
        RECT 49.380 79.470 49.875 79.910 ;
        RECT 51.080 79.470 51.575 79.910 ;
        RECT 49.380 72.970 49.875 73.410 ;
        RECT 52.780 79.470 53.275 79.910 ;
        RECT 52.780 71.670 53.275 72.110 ;
        RECT 52.780 76.870 53.275 77.310 ;
        RECT 49.380 71.670 49.875 72.110 ;
        RECT 52.780 75.570 53.275 76.010 ;
        RECT 52.780 74.270 53.275 74.710 ;
        RECT 49.380 82.070 49.875 82.510 ;
        RECT 51.080 72.970 51.575 73.410 ;
        RECT 34.080 74.270 34.575 74.710 ;
        RECT 34.080 84.670 34.575 85.110 ;
        RECT 34.080 72.970 34.575 73.410 ;
        RECT 34.080 78.170 34.575 78.610 ;
        RECT 34.080 85.970 34.575 86.410 ;
        RECT 34.080 87.270 34.575 87.710 ;
        RECT 34.080 79.470 34.575 79.910 ;
        RECT 34.080 88.570 34.575 89.010 ;
        RECT 34.080 75.570 34.575 76.010 ;
        RECT 34.080 71.670 34.575 72.110 ;
        RECT 34.080 89.870 34.575 90.310 ;
        RECT 34.080 82.070 34.575 82.510 ;
        RECT 34.080 91.170 34.575 91.610 ;
        RECT 34.080 76.870 34.575 77.310 ;
        RECT 32.545 92.870 34.100 93.340 ;
        RECT 34.080 83.370 34.575 83.810 ;
        RECT 39.180 84.670 39.675 85.110 ;
        RECT 35.780 88.570 36.275 89.010 ;
        RECT 37.480 88.570 37.975 89.010 ;
        RECT 39.180 88.570 39.675 89.010 ;
        RECT 35.780 85.970 36.275 86.410 ;
        RECT 37.480 85.970 37.975 86.410 ;
        RECT 39.180 85.970 39.675 86.410 ;
        RECT 35.780 89.870 36.275 90.310 ;
        RECT 37.480 89.870 37.975 90.310 ;
        RECT 39.180 89.870 39.675 90.310 ;
        RECT 35.780 84.670 36.275 85.110 ;
        RECT 35.780 87.270 36.275 87.710 ;
        RECT 35.780 91.170 36.275 91.610 ;
        RECT 37.480 91.170 37.975 91.610 ;
        RECT 39.180 91.170 39.675 91.610 ;
        RECT 37.480 87.270 37.975 87.710 ;
        RECT 39.180 87.270 39.675 87.710 ;
        RECT 34.245 92.870 35.800 93.340 ;
        RECT 35.945 92.870 37.500 93.340 ;
        RECT 37.645 92.870 39.200 93.340 ;
        RECT 37.480 84.670 37.975 85.110 ;
        RECT 35.780 83.370 36.275 83.810 ;
        RECT 37.480 83.370 37.975 83.810 ;
        RECT 39.180 83.370 39.675 83.810 ;
        RECT 28.980 88.570 29.475 89.010 ;
        RECT 30.680 88.570 31.175 89.010 ;
        RECT 28.980 91.170 29.475 91.610 ;
        RECT 30.680 91.170 31.175 91.610 ;
        RECT 32.380 91.170 32.875 91.610 ;
        RECT 32.380 88.570 32.875 89.010 ;
        RECT 28.980 85.970 29.475 86.410 ;
        RECT 28.980 87.270 29.475 87.710 ;
        RECT 30.680 87.270 31.175 87.710 ;
        RECT 32.380 87.270 32.875 87.710 ;
        RECT 27.445 92.870 29.000 93.340 ;
        RECT 29.145 92.870 30.700 93.340 ;
        RECT 30.845 92.870 32.400 93.340 ;
        RECT 30.680 85.970 31.175 86.410 ;
        RECT 32.380 85.970 32.875 86.410 ;
        RECT 28.980 89.870 29.475 90.310 ;
        RECT 30.680 89.870 31.175 90.310 ;
        RECT 28.980 83.370 29.475 83.810 ;
        RECT 30.680 83.370 31.175 83.810 ;
        RECT 32.380 83.370 32.875 83.810 ;
        RECT 32.380 89.870 32.875 90.310 ;
        RECT 28.980 84.670 29.475 85.110 ;
        RECT 30.680 84.670 31.175 85.110 ;
        RECT 32.380 84.670 32.875 85.110 ;
        RECT 29.940 94.540 30.460 95.060 ;
        RECT 30.680 71.670 31.175 72.110 ;
        RECT 32.380 75.570 32.875 76.010 ;
        RECT 28.980 72.970 29.475 73.410 ;
        RECT 28.980 74.270 29.475 74.710 ;
        RECT 30.680 74.270 31.175 74.710 ;
        RECT 28.980 76.870 29.475 77.310 ;
        RECT 30.680 76.870 31.175 77.310 ;
        RECT 32.380 76.870 32.875 77.310 ;
        RECT 28.980 79.470 29.475 79.910 ;
        RECT 30.680 79.470 31.175 79.910 ;
        RECT 32.380 79.470 32.875 79.910 ;
        RECT 32.380 71.670 32.875 72.110 ;
        RECT 28.980 75.570 29.475 76.010 ;
        RECT 30.680 75.570 31.175 76.010 ;
        RECT 28.980 82.070 29.475 82.510 ;
        RECT 30.680 82.070 31.175 82.510 ;
        RECT 32.380 82.070 32.875 82.510 ;
        RECT 30.680 72.970 31.175 73.410 ;
        RECT 28.980 71.670 29.475 72.110 ;
        RECT 28.980 78.170 29.475 78.610 ;
        RECT 30.680 78.170 31.175 78.610 ;
        RECT 32.380 78.170 32.875 78.610 ;
        RECT 32.380 74.270 32.875 74.710 ;
        RECT 32.380 72.970 32.875 73.410 ;
        RECT 39.180 79.470 39.675 79.910 ;
        RECT 37.480 72.970 37.975 73.410 ;
        RECT 39.180 72.970 39.675 73.410 ;
        RECT 37.480 74.270 37.975 74.710 ;
        RECT 35.780 78.170 36.275 78.610 ;
        RECT 37.480 78.170 37.975 78.610 ;
        RECT 35.780 76.870 36.275 77.310 ;
        RECT 39.180 74.270 39.675 74.710 ;
        RECT 35.780 74.270 36.275 74.710 ;
        RECT 39.180 78.170 39.675 78.610 ;
        RECT 35.780 82.070 36.275 82.510 ;
        RECT 37.480 82.070 37.975 82.510 ;
        RECT 39.180 82.070 39.675 82.510 ;
        RECT 35.780 75.570 36.275 76.010 ;
        RECT 37.480 75.570 37.975 76.010 ;
        RECT 39.180 75.570 39.675 76.010 ;
        RECT 35.780 72.970 36.275 73.410 ;
        RECT 35.780 71.670 36.275 72.110 ;
        RECT 37.480 71.670 37.975 72.110 ;
        RECT 39.180 71.670 39.675 72.110 ;
        RECT 35.780 79.470 36.275 79.910 ;
        RECT 37.480 76.870 37.975 77.310 ;
        RECT 39.180 76.870 39.675 77.310 ;
        RECT 37.480 79.470 37.975 79.910 ;
        RECT 34.080 56.070 34.575 56.510 ;
        RECT 34.080 50.870 34.575 51.310 ;
        RECT 34.080 58.670 34.575 59.110 ;
        RECT 34.080 59.970 34.575 60.410 ;
        RECT 34.080 61.270 34.575 61.710 ;
        RECT 34.080 62.570 34.575 63.010 ;
        RECT 34.080 49.570 34.575 50.010 ;
        RECT 34.080 63.870 34.575 64.310 ;
        RECT 34.080 65.170 34.575 65.610 ;
        RECT 34.080 66.470 34.575 66.910 ;
        RECT 34.080 67.770 34.575 68.210 ;
        RECT 34.080 52.170 34.575 52.610 ;
        RECT 34.080 70.370 34.575 70.810 ;
        RECT 34.080 48.270 34.575 48.710 ;
        RECT 34.080 53.470 34.575 53.910 ;
        RECT 34.080 54.770 34.575 55.210 ;
        RECT 35.780 59.970 36.275 60.410 ;
        RECT 35.780 63.870 36.275 64.310 ;
        RECT 37.480 63.870 37.975 64.310 ;
        RECT 39.180 63.870 39.675 64.310 ;
        RECT 35.780 61.270 36.275 61.710 ;
        RECT 35.780 65.170 36.275 65.610 ;
        RECT 37.480 65.170 37.975 65.610 ;
        RECT 39.180 65.170 39.675 65.610 ;
        RECT 37.480 61.270 37.975 61.710 ;
        RECT 35.780 66.470 36.275 66.910 ;
        RECT 37.480 66.470 37.975 66.910 ;
        RECT 39.180 66.470 39.675 66.910 ;
        RECT 39.180 61.270 39.675 61.710 ;
        RECT 35.780 67.770 36.275 68.210 ;
        RECT 37.480 67.770 37.975 68.210 ;
        RECT 39.180 67.770 39.675 68.210 ;
        RECT 37.480 59.970 37.975 60.410 ;
        RECT 39.180 59.970 39.675 60.410 ;
        RECT 35.780 70.370 36.275 70.810 ;
        RECT 37.480 70.370 37.975 70.810 ;
        RECT 39.180 70.370 39.675 70.810 ;
        RECT 35.780 62.570 36.275 63.010 ;
        RECT 37.480 62.570 37.975 63.010 ;
        RECT 39.180 62.570 39.675 63.010 ;
        RECT 30.680 66.470 31.175 66.910 ;
        RECT 32.380 66.470 32.875 66.910 ;
        RECT 28.980 59.970 29.475 60.410 ;
        RECT 28.980 63.870 29.475 64.310 ;
        RECT 30.680 63.870 31.175 64.310 ;
        RECT 32.380 63.870 32.875 64.310 ;
        RECT 28.980 67.770 29.475 68.210 ;
        RECT 30.680 67.770 31.175 68.210 ;
        RECT 32.380 67.770 32.875 68.210 ;
        RECT 28.980 61.270 29.475 61.710 ;
        RECT 28.980 62.570 29.475 63.010 ;
        RECT 30.680 62.570 31.175 63.010 ;
        RECT 32.380 62.570 32.875 63.010 ;
        RECT 28.980 65.170 29.475 65.610 ;
        RECT 28.980 70.370 29.475 70.810 ;
        RECT 30.680 70.370 31.175 70.810 ;
        RECT 32.380 70.370 32.875 70.810 ;
        RECT 30.680 65.170 31.175 65.610 ;
        RECT 32.380 65.170 32.875 65.610 ;
        RECT 30.680 61.270 31.175 61.710 ;
        RECT 32.380 61.270 32.875 61.710 ;
        RECT 30.680 59.970 31.175 60.410 ;
        RECT 32.380 59.970 32.875 60.410 ;
        RECT 28.980 66.470 29.475 66.910 ;
        RECT 30.680 58.670 31.175 59.110 ;
        RECT 32.380 52.170 32.875 52.610 ;
        RECT 32.380 48.270 32.875 48.710 ;
        RECT 30.680 52.170 31.175 52.610 ;
        RECT 28.980 52.170 29.475 52.610 ;
        RECT 32.380 58.670 32.875 59.110 ;
        RECT 30.680 49.570 31.175 50.010 ;
        RECT 28.980 48.270 29.475 48.710 ;
        RECT 28.980 50.870 29.475 51.310 ;
        RECT 28.980 58.670 29.475 59.110 ;
        RECT 28.980 53.470 29.475 53.910 ;
        RECT 30.680 53.470 31.175 53.910 ;
        RECT 32.380 53.470 32.875 53.910 ;
        RECT 30.680 48.270 31.175 48.710 ;
        RECT 30.680 50.870 31.175 51.310 ;
        RECT 28.980 54.770 29.475 55.210 ;
        RECT 30.680 54.770 31.175 55.210 ;
        RECT 28.980 49.570 29.475 50.010 ;
        RECT 32.380 54.770 32.875 55.210 ;
        RECT 32.380 49.570 32.875 50.010 ;
        RECT 32.380 50.870 32.875 51.310 ;
        RECT 28.980 56.070 29.475 56.510 ;
        RECT 30.680 56.070 31.175 56.510 ;
        RECT 32.380 56.070 32.875 56.510 ;
        RECT 39.180 48.270 39.675 48.710 ;
        RECT 35.780 58.670 36.275 59.110 ;
        RECT 37.480 58.670 37.975 59.110 ;
        RECT 39.180 58.670 39.675 59.110 ;
        RECT 35.780 49.570 36.275 50.010 ;
        RECT 35.780 50.870 36.275 51.310 ;
        RECT 35.780 53.470 36.275 53.910 ;
        RECT 37.480 53.470 37.975 53.910 ;
        RECT 39.180 53.470 39.675 53.910 ;
        RECT 39.180 50.870 39.675 51.310 ;
        RECT 35.780 48.270 36.275 48.710 ;
        RECT 37.480 50.870 37.975 51.310 ;
        RECT 39.180 56.070 39.675 56.510 ;
        RECT 37.480 49.570 37.975 50.010 ;
        RECT 35.780 56.070 36.275 56.510 ;
        RECT 35.780 52.170 36.275 52.610 ;
        RECT 35.780 54.770 36.275 55.210 ;
        RECT 37.480 54.770 37.975 55.210 ;
        RECT 39.180 54.770 39.675 55.210 ;
        RECT 37.480 56.070 37.975 56.510 ;
        RECT 37.480 48.270 37.975 48.710 ;
        RECT 39.180 49.570 39.675 50.010 ;
        RECT 37.480 52.170 37.975 52.610 ;
        RECT 39.180 52.170 39.675 52.610 ;
        RECT 47.680 48.270 48.175 48.710 ;
        RECT 47.680 58.670 48.175 59.110 ;
        RECT 47.680 65.170 48.175 65.610 ;
        RECT 47.680 50.870 48.175 51.310 ;
        RECT 47.680 54.770 48.175 55.210 ;
        RECT 47.680 66.470 48.175 66.910 ;
        RECT 47.680 59.970 48.175 60.410 ;
        RECT 47.680 49.570 48.175 50.010 ;
        RECT 47.680 67.770 48.175 68.210 ;
        RECT 47.680 70.370 48.175 70.810 ;
        RECT 47.680 61.270 48.175 61.710 ;
        RECT 47.680 53.470 48.175 53.910 ;
        RECT 47.680 56.070 48.175 56.510 ;
        RECT 47.680 62.570 48.175 63.010 ;
        RECT 47.680 52.170 48.175 52.610 ;
        RECT 47.680 63.870 48.175 64.310 ;
        RECT 52.780 63.870 53.275 64.310 ;
        RECT 49.380 65.170 49.875 65.610 ;
        RECT 49.380 67.770 49.875 68.210 ;
        RECT 51.080 67.770 51.575 68.210 ;
        RECT 52.780 67.770 53.275 68.210 ;
        RECT 52.780 59.970 53.275 60.410 ;
        RECT 51.080 65.170 51.575 65.610 ;
        RECT 49.380 70.370 49.875 70.810 ;
        RECT 51.080 70.370 51.575 70.810 ;
        RECT 52.780 70.370 53.275 70.810 ;
        RECT 49.380 66.470 49.875 66.910 ;
        RECT 49.380 61.270 49.875 61.710 ;
        RECT 51.080 61.270 51.575 61.710 ;
        RECT 52.780 61.270 53.275 61.710 ;
        RECT 51.080 66.470 51.575 66.910 ;
        RECT 52.780 66.470 53.275 66.910 ;
        RECT 52.780 65.170 53.275 65.610 ;
        RECT 49.380 62.570 49.875 63.010 ;
        RECT 51.080 62.570 51.575 63.010 ;
        RECT 52.780 62.570 53.275 63.010 ;
        RECT 49.380 59.970 49.875 60.410 ;
        RECT 51.080 59.970 51.575 60.410 ;
        RECT 49.380 63.870 49.875 64.310 ;
        RECT 51.080 63.870 51.575 64.310 ;
        RECT 42.580 67.770 43.075 68.210 ;
        RECT 42.580 61.270 43.075 61.710 ;
        RECT 44.280 61.270 44.775 61.710 ;
        RECT 45.980 61.270 46.475 61.710 ;
        RECT 44.280 67.770 44.775 68.210 ;
        RECT 44.280 65.170 44.775 65.610 ;
        RECT 45.980 67.770 46.475 68.210 ;
        RECT 45.980 65.170 46.475 65.610 ;
        RECT 42.580 66.470 43.075 66.910 ;
        RECT 42.580 59.970 43.075 60.410 ;
        RECT 42.580 62.570 43.075 63.010 ;
        RECT 44.280 62.570 44.775 63.010 ;
        RECT 45.980 62.570 46.475 63.010 ;
        RECT 44.280 59.970 44.775 60.410 ;
        RECT 45.980 59.970 46.475 60.410 ;
        RECT 42.580 70.370 43.075 70.810 ;
        RECT 44.280 70.370 44.775 70.810 ;
        RECT 45.980 70.370 46.475 70.810 ;
        RECT 42.580 63.870 43.075 64.310 ;
        RECT 44.280 63.870 44.775 64.310 ;
        RECT 45.980 63.870 46.475 64.310 ;
        RECT 44.280 66.470 44.775 66.910 ;
        RECT 45.980 66.470 46.475 66.910 ;
        RECT 42.580 65.170 43.075 65.610 ;
        RECT 44.280 48.270 44.775 48.710 ;
        RECT 45.980 53.470 46.475 53.910 ;
        RECT 42.580 54.770 43.075 55.210 ;
        RECT 42.580 56.070 43.075 56.510 ;
        RECT 44.280 56.070 44.775 56.510 ;
        RECT 45.980 56.070 46.475 56.510 ;
        RECT 44.280 54.770 44.775 55.210 ;
        RECT 45.980 54.770 46.475 55.210 ;
        RECT 44.280 49.570 44.775 50.010 ;
        RECT 42.580 58.670 43.075 59.110 ;
        RECT 44.280 58.670 44.775 59.110 ;
        RECT 45.980 58.670 46.475 59.110 ;
        RECT 42.580 53.470 43.075 53.910 ;
        RECT 44.280 53.470 44.775 53.910 ;
        RECT 45.980 48.270 46.475 48.710 ;
        RECT 45.980 52.170 46.475 52.610 ;
        RECT 45.980 49.570 46.475 50.010 ;
        RECT 45.980 50.870 46.475 51.310 ;
        RECT 42.580 48.270 43.075 48.710 ;
        RECT 42.580 50.870 43.075 51.310 ;
        RECT 44.280 50.870 44.775 51.310 ;
        RECT 42.580 52.170 43.075 52.610 ;
        RECT 42.580 49.570 43.075 50.010 ;
        RECT 44.280 52.170 44.775 52.610 ;
        RECT 51.080 58.670 51.575 59.110 ;
        RECT 51.080 48.270 51.575 48.710 ;
        RECT 49.380 54.770 49.875 55.210 ;
        RECT 51.080 54.770 51.575 55.210 ;
        RECT 49.380 50.870 49.875 51.310 ;
        RECT 49.380 49.570 49.875 50.010 ;
        RECT 52.780 49.570 53.275 50.010 ;
        RECT 51.080 50.870 51.575 51.310 ;
        RECT 51.080 49.570 51.575 50.010 ;
        RECT 52.780 56.070 53.275 56.510 ;
        RECT 49.380 53.470 49.875 53.910 ;
        RECT 51.080 53.470 51.575 53.910 ;
        RECT 52.780 53.470 53.275 53.910 ;
        RECT 52.780 52.170 53.275 52.610 ;
        RECT 49.380 58.670 49.875 59.110 ;
        RECT 49.380 52.170 49.875 52.610 ;
        RECT 51.080 52.170 51.575 52.610 ;
        RECT 52.780 48.270 53.275 48.710 ;
        RECT 49.380 48.270 49.875 48.710 ;
        RECT 52.780 58.670 53.275 59.110 ;
        RECT 52.780 54.770 53.275 55.210 ;
        RECT 52.780 50.870 53.275 51.310 ;
        RECT 49.380 56.070 49.875 56.510 ;
        RECT 51.080 56.070 51.575 56.510 ;
        RECT 13.680 71.670 14.175 72.110 ;
        RECT 13.680 59.970 14.175 60.410 ;
        RECT 13.680 72.970 14.175 73.410 ;
        RECT 13.680 53.470 14.175 53.910 ;
        RECT 13.680 74.270 14.175 74.710 ;
        RECT 13.680 61.270 14.175 61.710 ;
        RECT 13.680 75.570 14.175 76.010 ;
        RECT 13.680 50.870 14.175 51.310 ;
        RECT 13.680 76.870 14.175 77.310 ;
        RECT 13.680 62.570 14.175 63.010 ;
        RECT 13.680 78.170 14.175 78.610 ;
        RECT 13.680 54.770 14.175 55.210 ;
        RECT 13.680 79.470 14.175 79.910 ;
        RECT 13.680 63.870 14.175 64.310 ;
        RECT 13.680 82.070 14.175 82.510 ;
        RECT 13.680 49.570 14.175 50.010 ;
        RECT 13.680 83.370 14.175 83.810 ;
        RECT 13.680 65.170 14.175 65.610 ;
        RECT 13.680 84.670 14.175 85.110 ;
        RECT 13.680 56.070 14.175 56.510 ;
        RECT 13.680 85.970 14.175 86.410 ;
        RECT 13.680 66.470 14.175 66.910 ;
        RECT 13.680 87.270 14.175 87.710 ;
        RECT 13.680 52.170 14.175 52.610 ;
        RECT 13.680 88.570 14.175 89.010 ;
        RECT 13.680 67.770 14.175 68.210 ;
        RECT 13.680 89.870 14.175 90.310 ;
        RECT 13.680 58.670 14.175 59.110 ;
        RECT 13.680 91.170 14.175 91.610 ;
        RECT 13.680 70.370 14.175 70.810 ;
        RECT 12.145 92.870 13.700 93.340 ;
        RECT 13.680 48.270 14.175 48.710 ;
        RECT 20.480 76.870 20.975 77.310 ;
        RECT 20.480 78.170 20.975 78.610 ;
        RECT 20.480 79.470 20.975 79.910 ;
        RECT 20.480 72.970 20.975 73.410 ;
        RECT 20.480 82.070 20.975 82.510 ;
        RECT 20.480 83.370 20.975 83.810 ;
        RECT 20.480 71.670 20.975 72.110 ;
        RECT 20.480 84.670 20.975 85.110 ;
        RECT 20.480 85.970 20.975 86.410 ;
        RECT 20.480 74.270 20.975 74.710 ;
        RECT 20.480 87.270 20.975 87.710 ;
        RECT 20.480 88.570 20.975 89.010 ;
        RECT 20.480 89.870 20.975 90.310 ;
        RECT 20.480 91.170 20.975 91.610 ;
        RECT 18.945 92.870 20.500 93.340 ;
        RECT 20.480 75.570 20.975 76.010 ;
        RECT 23.880 85.970 24.375 86.410 ;
        RECT 25.580 85.970 26.075 86.410 ;
        RECT 22.180 83.370 22.675 83.810 ;
        RECT 23.880 83.370 24.375 83.810 ;
        RECT 22.180 87.270 22.675 87.710 ;
        RECT 23.880 87.270 24.375 87.710 ;
        RECT 25.580 87.270 26.075 87.710 ;
        RECT 22.180 84.670 22.675 85.110 ;
        RECT 22.180 88.570 22.675 89.010 ;
        RECT 23.880 88.570 24.375 89.010 ;
        RECT 25.580 88.570 26.075 89.010 ;
        RECT 23.880 84.670 24.375 85.110 ;
        RECT 22.180 89.870 22.675 90.310 ;
        RECT 23.880 89.870 24.375 90.310 ;
        RECT 25.580 89.870 26.075 90.310 ;
        RECT 25.580 84.670 26.075 85.110 ;
        RECT 22.180 91.170 22.675 91.610 ;
        RECT 23.880 91.170 24.375 91.610 ;
        RECT 25.580 91.170 26.075 91.610 ;
        RECT 25.580 83.370 26.075 83.810 ;
        RECT 20.645 92.870 22.200 93.340 ;
        RECT 22.345 92.870 23.900 93.340 ;
        RECT 24.045 92.870 25.600 93.340 ;
        RECT 22.180 85.970 22.675 86.410 ;
        RECT 18.780 83.370 19.275 83.810 ;
        RECT 15.380 83.370 15.875 83.810 ;
        RECT 15.380 89.870 15.875 90.310 ;
        RECT 17.080 89.870 17.575 90.310 ;
        RECT 18.780 89.870 19.275 90.310 ;
        RECT 17.080 83.370 17.575 83.810 ;
        RECT 15.380 87.270 15.875 87.710 ;
        RECT 17.080 87.270 17.575 87.710 ;
        RECT 18.780 87.270 19.275 87.710 ;
        RECT 15.380 91.170 15.875 91.610 ;
        RECT 17.080 91.170 17.575 91.610 ;
        RECT 18.780 91.170 19.275 91.610 ;
        RECT 15.380 84.670 15.875 85.110 ;
        RECT 15.380 85.970 15.875 86.410 ;
        RECT 17.080 85.970 17.575 86.410 ;
        RECT 18.780 85.970 19.275 86.410 ;
        RECT 13.845 92.870 15.400 93.340 ;
        RECT 15.545 92.870 17.100 93.340 ;
        RECT 17.245 92.870 18.800 93.340 ;
        RECT 15.380 88.570 15.875 89.010 ;
        RECT 17.080 88.570 17.575 89.010 ;
        RECT 18.780 88.570 19.275 89.010 ;
        RECT 17.080 84.670 17.575 85.110 ;
        RECT 18.780 84.670 19.275 85.110 ;
        RECT 15.380 72.970 15.875 73.410 ;
        RECT 15.380 78.170 15.875 78.610 ;
        RECT 17.080 78.170 17.575 78.610 ;
        RECT 18.780 78.170 19.275 78.610 ;
        RECT 18.780 74.270 19.275 74.710 ;
        RECT 15.380 76.870 15.875 77.310 ;
        RECT 15.380 75.570 15.875 76.010 ;
        RECT 17.080 72.970 17.575 73.410 ;
        RECT 18.780 71.670 19.275 72.110 ;
        RECT 18.780 72.970 19.275 73.410 ;
        RECT 15.380 79.470 15.875 79.910 ;
        RECT 17.080 79.470 17.575 79.910 ;
        RECT 18.780 79.470 19.275 79.910 ;
        RECT 17.080 76.870 17.575 77.310 ;
        RECT 17.080 75.570 17.575 76.010 ;
        RECT 18.780 75.570 19.275 76.010 ;
        RECT 18.780 76.870 19.275 77.310 ;
        RECT 15.380 82.070 15.875 82.510 ;
        RECT 17.080 82.070 17.575 82.510 ;
        RECT 15.380 74.270 15.875 74.710 ;
        RECT 17.080 74.270 17.575 74.710 ;
        RECT 18.780 82.070 19.275 82.510 ;
        RECT 15.380 71.670 15.875 72.110 ;
        RECT 17.080 71.670 17.575 72.110 ;
        RECT 22.180 79.470 22.675 79.910 ;
        RECT 23.880 79.470 24.375 79.910 ;
        RECT 25.580 79.470 26.075 79.910 ;
        RECT 23.880 76.870 24.375 77.310 ;
        RECT 22.180 72.970 22.675 73.410 ;
        RECT 23.880 71.670 24.375 72.110 ;
        RECT 22.180 78.170 22.675 78.610 ;
        RECT 23.880 78.170 24.375 78.610 ;
        RECT 25.580 78.170 26.075 78.610 ;
        RECT 25.580 76.870 26.075 77.310 ;
        RECT 22.180 82.070 22.675 82.510 ;
        RECT 22.180 74.270 22.675 74.710 ;
        RECT 23.880 74.270 24.375 74.710 ;
        RECT 23.880 82.070 24.375 82.510 ;
        RECT 25.580 82.070 26.075 82.510 ;
        RECT 23.880 72.970 24.375 73.410 ;
        RECT 25.580 72.970 26.075 73.410 ;
        RECT 23.880 75.570 24.375 76.010 ;
        RECT 25.580 75.570 26.075 76.010 ;
        RECT 25.580 71.670 26.075 72.110 ;
        RECT 25.580 74.270 26.075 74.710 ;
        RECT 22.180 71.670 22.675 72.110 ;
        RECT 22.180 75.570 22.675 76.010 ;
        RECT 22.180 76.870 22.675 77.310 ;
        RECT 6.880 74.270 7.375 74.710 ;
        RECT 6.880 72.970 7.375 73.410 ;
        RECT 6.880 84.670 7.375 85.110 ;
        RECT 6.880 78.170 7.375 78.610 ;
        RECT 6.880 85.970 7.375 86.410 ;
        RECT 6.880 87.270 7.375 87.710 ;
        RECT 6.880 75.570 7.375 76.010 ;
        RECT 6.880 79.470 7.375 79.910 ;
        RECT 6.880 88.570 7.375 89.010 ;
        RECT 6.880 71.670 7.375 72.110 ;
        RECT 6.880 89.870 7.375 90.310 ;
        RECT 6.880 82.070 7.375 82.510 ;
        RECT 6.880 91.170 7.375 91.610 ;
        RECT 6.880 76.870 7.375 77.310 ;
        RECT 5.345 92.870 6.900 93.340 ;
        RECT 6.880 83.370 7.375 83.810 ;
        RECT 10.280 84.670 10.775 85.110 ;
        RECT 8.580 85.970 9.075 86.410 ;
        RECT 8.580 88.570 9.075 89.010 ;
        RECT 10.280 88.570 10.775 89.010 ;
        RECT 11.980 88.570 12.475 89.010 ;
        RECT 10.280 85.970 10.775 86.410 ;
        RECT 11.980 85.970 12.475 86.410 ;
        RECT 8.580 89.870 9.075 90.310 ;
        RECT 10.280 89.870 10.775 90.310 ;
        RECT 11.980 89.870 12.475 90.310 ;
        RECT 11.980 84.670 12.475 85.110 ;
        RECT 8.580 87.270 9.075 87.710 ;
        RECT 8.580 91.170 9.075 91.610 ;
        RECT 10.280 91.170 10.775 91.610 ;
        RECT 11.980 91.170 12.475 91.610 ;
        RECT 10.280 87.270 10.775 87.710 ;
        RECT 11.980 87.270 12.475 87.710 ;
        RECT 7.045 92.870 8.600 93.340 ;
        RECT 8.745 92.870 10.300 93.340 ;
        RECT 10.445 92.870 12.000 93.340 ;
        RECT 8.580 84.670 9.075 85.110 ;
        RECT 8.580 83.370 9.075 83.810 ;
        RECT 10.280 83.370 10.775 83.810 ;
        RECT 11.980 83.370 12.475 83.810 ;
        RECT 7.940 93.690 8.460 94.210 ;
        RECT 5.180 89.870 5.675 90.310 ;
        RECT 5.180 87.270 5.675 87.710 ;
        RECT 0.080 85.970 0.575 86.410 ;
        RECT 1.780 85.970 2.275 86.410 ;
        RECT 3.480 85.970 3.975 86.410 ;
        RECT 5.180 85.970 5.675 86.410 ;
        RECT 0.080 91.170 0.575 91.610 ;
        RECT 1.780 91.170 2.275 91.610 ;
        RECT 3.480 91.170 3.975 91.610 ;
        RECT 5.180 91.170 5.675 91.610 ;
        RECT 1.780 84.670 2.275 85.110 ;
        RECT 3.480 84.670 3.975 85.110 ;
        RECT 0.080 88.570 0.575 89.010 ;
        RECT 1.780 88.570 2.275 89.010 ;
        RECT 3.480 88.570 3.975 89.010 ;
        RECT 0.080 83.370 0.575 83.810 ;
        RECT 0.245 92.870 1.800 93.340 ;
        RECT 1.945 92.870 3.500 93.340 ;
        RECT 3.645 92.870 5.200 93.340 ;
        RECT 5.180 88.570 5.675 89.010 ;
        RECT 5.180 84.670 5.675 85.110 ;
        RECT 0.080 84.670 0.575 85.110 ;
        RECT 0.080 87.270 0.575 87.710 ;
        RECT 1.780 83.370 2.275 83.810 ;
        RECT 3.480 83.370 3.975 83.810 ;
        RECT 5.180 83.370 5.675 83.810 ;
        RECT 1.780 87.270 2.275 87.710 ;
        RECT 3.480 87.270 3.975 87.710 ;
        RECT 0.080 89.870 0.575 90.310 ;
        RECT 1.780 89.870 2.275 90.310 ;
        RECT 3.480 89.870 3.975 90.310 ;
        RECT 3.480 71.670 3.975 72.110 ;
        RECT 0.080 75.570 0.575 76.010 ;
        RECT 1.780 75.570 2.275 76.010 ;
        RECT 5.180 71.670 5.675 72.110 ;
        RECT 3.480 75.570 3.975 76.010 ;
        RECT 0.080 72.970 0.575 73.410 ;
        RECT 1.780 72.970 2.275 73.410 ;
        RECT 3.480 74.270 3.975 74.710 ;
        RECT 5.180 74.270 5.675 74.710 ;
        RECT 0.080 76.870 0.575 77.310 ;
        RECT 1.780 76.870 2.275 77.310 ;
        RECT 3.480 76.870 3.975 77.310 ;
        RECT 5.180 76.870 5.675 77.310 ;
        RECT 3.480 72.970 3.975 73.410 ;
        RECT 0.080 74.270 0.575 74.710 ;
        RECT 0.080 79.470 0.575 79.910 ;
        RECT 1.780 79.470 2.275 79.910 ;
        RECT 3.480 79.470 3.975 79.910 ;
        RECT 5.180 79.470 5.675 79.910 ;
        RECT 5.180 75.570 5.675 76.010 ;
        RECT 5.180 78.170 5.675 78.610 ;
        RECT 5.180 72.970 5.675 73.410 ;
        RECT 0.080 78.170 0.575 78.610 ;
        RECT 0.080 82.070 0.575 82.510 ;
        RECT 1.780 82.070 2.275 82.510 ;
        RECT 3.480 82.070 3.975 82.510 ;
        RECT 5.180 82.070 5.675 82.510 ;
        RECT 1.780 78.170 2.275 78.610 ;
        RECT 1.780 74.270 2.275 74.710 ;
        RECT 0.080 71.670 0.575 72.110 ;
        RECT 3.480 78.170 3.975 78.610 ;
        RECT 1.780 71.670 2.275 72.110 ;
        RECT 8.580 74.270 9.075 74.710 ;
        RECT 8.580 75.570 9.075 76.010 ;
        RECT 10.280 75.570 10.775 76.010 ;
        RECT 8.580 76.870 9.075 77.310 ;
        RECT 11.980 75.570 12.475 76.010 ;
        RECT 10.280 74.270 10.775 74.710 ;
        RECT 8.580 82.070 9.075 82.510 ;
        RECT 10.280 82.070 10.775 82.510 ;
        RECT 11.980 82.070 12.475 82.510 ;
        RECT 8.580 72.970 9.075 73.410 ;
        RECT 10.280 72.970 10.775 73.410 ;
        RECT 8.580 78.170 9.075 78.610 ;
        RECT 8.580 79.470 9.075 79.910 ;
        RECT 10.280 79.470 10.775 79.910 ;
        RECT 11.980 79.470 12.475 79.910 ;
        RECT 10.280 78.170 10.775 78.610 ;
        RECT 11.980 78.170 12.475 78.610 ;
        RECT 8.580 71.670 9.075 72.110 ;
        RECT 10.280 71.670 10.775 72.110 ;
        RECT 10.280 76.870 10.775 77.310 ;
        RECT 11.980 76.870 12.475 77.310 ;
        RECT 11.980 71.670 12.475 72.110 ;
        RECT 11.980 72.970 12.475 73.410 ;
        RECT 11.980 74.270 12.475 74.710 ;
        RECT 6.880 49.570 7.375 50.010 ;
        RECT 6.880 50.870 7.375 51.310 ;
        RECT 6.880 52.170 7.375 52.610 ;
        RECT 6.880 54.770 7.375 55.210 ;
        RECT 6.880 61.270 7.375 61.710 ;
        RECT 6.880 67.770 7.375 68.210 ;
        RECT 6.880 65.170 7.375 65.610 ;
        RECT 6.880 59.970 7.375 60.410 ;
        RECT 6.880 58.670 7.375 59.110 ;
        RECT 6.880 56.070 7.375 56.510 ;
        RECT 6.880 63.870 7.375 64.310 ;
        RECT 6.880 70.370 7.375 70.810 ;
        RECT 6.880 62.570 7.375 63.010 ;
        RECT 6.880 53.470 7.375 53.910 ;
        RECT 6.880 48.270 7.375 48.710 ;
        RECT 6.880 66.470 7.375 66.910 ;
        RECT 8.580 67.770 9.075 68.210 ;
        RECT 8.580 59.970 9.075 60.410 ;
        RECT 10.280 59.970 10.775 60.410 ;
        RECT 11.980 59.970 12.475 60.410 ;
        RECT 10.280 67.770 10.775 68.210 ;
        RECT 11.980 67.770 12.475 68.210 ;
        RECT 8.580 61.270 9.075 61.710 ;
        RECT 8.580 63.870 9.075 64.310 ;
        RECT 10.280 63.870 10.775 64.310 ;
        RECT 11.980 63.870 12.475 64.310 ;
        RECT 8.580 65.170 9.075 65.610 ;
        RECT 8.580 70.370 9.075 70.810 ;
        RECT 10.280 70.370 10.775 70.810 ;
        RECT 11.980 70.370 12.475 70.810 ;
        RECT 10.280 65.170 10.775 65.610 ;
        RECT 8.580 62.570 9.075 63.010 ;
        RECT 10.280 62.570 10.775 63.010 ;
        RECT 11.980 62.570 12.475 63.010 ;
        RECT 11.980 65.170 12.475 65.610 ;
        RECT 10.280 61.270 10.775 61.710 ;
        RECT 11.980 61.270 12.475 61.710 ;
        RECT 8.580 66.470 9.075 66.910 ;
        RECT 10.280 66.470 10.775 66.910 ;
        RECT 11.980 66.470 12.475 66.910 ;
        RECT 3.480 63.870 3.975 64.310 ;
        RECT 3.480 61.270 3.975 61.710 ;
        RECT 5.180 63.870 5.675 64.310 ;
        RECT 0.080 65.170 0.575 65.610 ;
        RECT 1.780 65.170 2.275 65.610 ;
        RECT 3.480 65.170 3.975 65.610 ;
        RECT 5.180 65.170 5.675 65.610 ;
        RECT 0.080 70.370 0.575 70.810 ;
        RECT 1.780 70.370 2.275 70.810 ;
        RECT 3.480 70.370 3.975 70.810 ;
        RECT 5.180 70.370 5.675 70.810 ;
        RECT 0.080 67.770 0.575 68.210 ;
        RECT 1.780 67.770 2.275 68.210 ;
        RECT 3.480 59.970 3.975 60.410 ;
        RECT 5.180 59.970 5.675 60.410 ;
        RECT 3.480 62.570 3.975 63.010 ;
        RECT 5.180 62.570 5.675 63.010 ;
        RECT 3.480 67.770 3.975 68.210 ;
        RECT 5.180 67.770 5.675 68.210 ;
        RECT 0.080 61.270 0.575 61.710 ;
        RECT 5.180 61.270 5.675 61.710 ;
        RECT 0.080 59.970 0.575 60.410 ;
        RECT 1.780 59.970 2.275 60.410 ;
        RECT 0.080 66.470 0.575 66.910 ;
        RECT 1.780 66.470 2.275 66.910 ;
        RECT 3.480 66.470 3.975 66.910 ;
        RECT 5.180 66.470 5.675 66.910 ;
        RECT 0.080 62.570 0.575 63.010 ;
        RECT 1.780 61.270 2.275 61.710 ;
        RECT 1.780 62.570 2.275 63.010 ;
        RECT 0.080 63.870 0.575 64.310 ;
        RECT 1.780 63.870 2.275 64.310 ;
        RECT 3.480 52.170 3.975 52.610 ;
        RECT 5.180 52.170 5.675 52.610 ;
        RECT 3.480 50.870 3.975 51.310 ;
        RECT 5.180 50.870 5.675 51.310 ;
        RECT 0.080 49.570 0.575 50.010 ;
        RECT 0.080 54.770 0.575 55.210 ;
        RECT 0.080 53.470 0.575 53.910 ;
        RECT 1.780 53.470 2.275 53.910 ;
        RECT 3.480 53.470 3.975 53.910 ;
        RECT 1.780 54.770 2.275 55.210 ;
        RECT 0.080 58.670 0.575 59.110 ;
        RECT 1.780 58.670 2.275 59.110 ;
        RECT 3.480 58.670 3.975 59.110 ;
        RECT 5.180 58.670 5.675 59.110 ;
        RECT 3.480 54.770 3.975 55.210 ;
        RECT 5.180 54.770 5.675 55.210 ;
        RECT 5.180 53.470 5.675 53.910 ;
        RECT 1.780 49.570 2.275 50.010 ;
        RECT 3.480 49.570 3.975 50.010 ;
        RECT 5.180 49.570 5.675 50.010 ;
        RECT 0.080 56.070 0.575 56.510 ;
        RECT 1.780 56.070 2.275 56.510 ;
        RECT 3.480 56.070 3.975 56.510 ;
        RECT 0.080 48.270 0.575 48.710 ;
        RECT 1.780 48.270 2.275 48.710 ;
        RECT 3.480 48.270 3.975 48.710 ;
        RECT 5.180 48.270 5.675 48.710 ;
        RECT 5.180 56.070 5.675 56.510 ;
        RECT 0.080 50.870 0.575 51.310 ;
        RECT 1.780 50.870 2.275 51.310 ;
        RECT 0.080 52.170 0.575 52.610 ;
        RECT 1.780 52.170 2.275 52.610 ;
        RECT 11.980 56.070 12.475 56.510 ;
        RECT 10.280 54.770 10.775 55.210 ;
        RECT 11.980 54.770 12.475 55.210 ;
        RECT 10.280 52.170 10.775 52.610 ;
        RECT 8.580 53.470 9.075 53.910 ;
        RECT 10.280 53.470 10.775 53.910 ;
        RECT 11.980 53.470 12.475 53.910 ;
        RECT 8.580 58.670 9.075 59.110 ;
        RECT 10.280 58.670 10.775 59.110 ;
        RECT 11.980 58.670 12.475 59.110 ;
        RECT 11.980 52.170 12.475 52.610 ;
        RECT 11.980 50.870 12.475 51.310 ;
        RECT 10.280 49.570 10.775 50.010 ;
        RECT 11.980 49.570 12.475 50.010 ;
        RECT 8.580 49.570 9.075 50.010 ;
        RECT 8.580 50.870 9.075 51.310 ;
        RECT 10.280 50.870 10.775 51.310 ;
        RECT 8.580 48.270 9.075 48.710 ;
        RECT 10.280 48.270 10.775 48.710 ;
        RECT 11.980 48.270 12.475 48.710 ;
        RECT 8.580 52.170 9.075 52.610 ;
        RECT 8.580 54.770 9.075 55.210 ;
        RECT 8.580 56.070 9.075 56.510 ;
        RECT 10.280 56.070 10.775 56.510 ;
        RECT 20.480 49.570 20.975 50.010 ;
        RECT 20.480 67.770 20.975 68.210 ;
        RECT 20.480 59.970 20.975 60.410 ;
        RECT 20.480 53.470 20.975 53.910 ;
        RECT 20.480 66.470 20.975 66.910 ;
        RECT 20.480 58.670 20.975 59.110 ;
        RECT 20.480 63.870 20.975 64.310 ;
        RECT 20.480 65.170 20.975 65.610 ;
        RECT 20.480 61.270 20.975 61.710 ;
        RECT 20.480 70.370 20.975 70.810 ;
        RECT 20.480 52.170 20.975 52.610 ;
        RECT 20.480 54.770 20.975 55.210 ;
        RECT 20.480 50.870 20.975 51.310 ;
        RECT 20.480 62.570 20.975 63.010 ;
        RECT 20.480 48.270 20.975 48.710 ;
        RECT 20.480 56.070 20.975 56.510 ;
        RECT 25.580 62.570 26.075 63.010 ;
        RECT 22.180 63.870 22.675 64.310 ;
        RECT 23.880 63.870 24.375 64.310 ;
        RECT 25.580 63.870 26.075 64.310 ;
        RECT 23.880 59.970 24.375 60.410 ;
        RECT 22.180 65.170 22.675 65.610 ;
        RECT 23.880 65.170 24.375 65.610 ;
        RECT 25.580 65.170 26.075 65.610 ;
        RECT 25.580 59.970 26.075 60.410 ;
        RECT 22.180 61.270 22.675 61.710 ;
        RECT 23.880 61.270 24.375 61.710 ;
        RECT 25.580 61.270 26.075 61.710 ;
        RECT 22.180 59.970 22.675 60.410 ;
        RECT 22.180 67.770 22.675 68.210 ;
        RECT 22.180 70.370 22.675 70.810 ;
        RECT 23.880 70.370 24.375 70.810 ;
        RECT 25.580 70.370 26.075 70.810 ;
        RECT 23.880 67.770 24.375 68.210 ;
        RECT 25.580 67.770 26.075 68.210 ;
        RECT 22.180 66.470 22.675 66.910 ;
        RECT 23.880 62.570 24.375 63.010 ;
        RECT 22.180 62.570 22.675 63.010 ;
        RECT 23.880 66.470 24.375 66.910 ;
        RECT 25.580 66.470 26.075 66.910 ;
        RECT 17.080 66.470 17.575 66.910 ;
        RECT 18.780 66.470 19.275 66.910 ;
        RECT 17.080 67.770 17.575 68.210 ;
        RECT 15.380 59.970 15.875 60.410 ;
        RECT 17.080 59.970 17.575 60.410 ;
        RECT 18.780 59.970 19.275 60.410 ;
        RECT 18.780 67.770 19.275 68.210 ;
        RECT 15.380 70.370 15.875 70.810 ;
        RECT 17.080 70.370 17.575 70.810 ;
        RECT 18.780 70.370 19.275 70.810 ;
        RECT 18.780 63.870 19.275 64.310 ;
        RECT 15.380 67.770 15.875 68.210 ;
        RECT 15.380 61.270 15.875 61.710 ;
        RECT 17.080 61.270 17.575 61.710 ;
        RECT 15.380 63.870 15.875 64.310 ;
        RECT 18.780 61.270 19.275 61.710 ;
        RECT 15.380 65.170 15.875 65.610 ;
        RECT 15.380 62.570 15.875 63.010 ;
        RECT 17.080 62.570 17.575 63.010 ;
        RECT 18.780 62.570 19.275 63.010 ;
        RECT 17.080 65.170 17.575 65.610 ;
        RECT 18.780 65.170 19.275 65.610 ;
        RECT 17.080 63.870 17.575 64.310 ;
        RECT 15.380 66.470 15.875 66.910 ;
        RECT 17.080 54.770 17.575 55.210 ;
        RECT 18.780 54.770 19.275 55.210 ;
        RECT 15.380 52.170 15.875 52.610 ;
        RECT 17.080 52.170 17.575 52.610 ;
        RECT 18.780 52.170 19.275 52.610 ;
        RECT 18.780 53.470 19.275 53.910 ;
        RECT 15.380 50.870 15.875 51.310 ;
        RECT 17.080 50.870 17.575 51.310 ;
        RECT 18.780 50.870 19.275 51.310 ;
        RECT 15.380 54.770 15.875 55.210 ;
        RECT 15.380 58.670 15.875 59.110 ;
        RECT 17.080 58.670 17.575 59.110 ;
        RECT 18.780 58.670 19.275 59.110 ;
        RECT 17.080 49.570 17.575 50.010 ;
        RECT 18.780 49.570 19.275 50.010 ;
        RECT 15.380 49.570 15.875 50.010 ;
        RECT 15.380 56.070 15.875 56.510 ;
        RECT 17.080 56.070 17.575 56.510 ;
        RECT 15.380 48.270 15.875 48.710 ;
        RECT 17.080 48.270 17.575 48.710 ;
        RECT 18.780 48.270 19.275 48.710 ;
        RECT 15.380 53.470 15.875 53.910 ;
        RECT 18.780 56.070 19.275 56.510 ;
        RECT 17.080 53.470 17.575 53.910 ;
        RECT 22.180 54.770 22.675 55.210 ;
        RECT 23.880 54.770 24.375 55.210 ;
        RECT 25.580 54.770 26.075 55.210 ;
        RECT 25.580 50.870 26.075 51.310 ;
        RECT 23.880 56.070 24.375 56.510 ;
        RECT 22.180 49.570 22.675 50.010 ;
        RECT 25.580 49.570 26.075 50.010 ;
        RECT 23.880 49.570 24.375 50.010 ;
        RECT 25.580 56.070 26.075 56.510 ;
        RECT 22.180 50.870 22.675 51.310 ;
        RECT 23.880 50.870 24.375 51.310 ;
        RECT 22.180 53.470 22.675 53.910 ;
        RECT 23.880 53.470 24.375 53.910 ;
        RECT 25.580 53.470 26.075 53.910 ;
        RECT 22.180 58.670 22.675 59.110 ;
        RECT 23.880 58.670 24.375 59.110 ;
        RECT 22.180 52.170 22.675 52.610 ;
        RECT 23.880 52.170 24.375 52.610 ;
        RECT 22.180 48.270 22.675 48.710 ;
        RECT 23.880 48.270 24.375 48.710 ;
        RECT 25.580 48.270 26.075 48.710 ;
        RECT 25.580 52.170 26.075 52.610 ;
        RECT 25.580 58.670 26.075 59.110 ;
        RECT 22.180 56.070 22.675 56.510 ;
        RECT 13.680 44.370 14.175 44.810 ;
        RECT 13.680 46.970 14.175 47.410 ;
        RECT 13.680 2.770 14.175 3.210 ;
        RECT 13.680 4.070 14.175 4.510 ;
        RECT 13.680 5.370 14.175 5.810 ;
        RECT 13.680 6.670 14.175 7.110 ;
        RECT 13.680 7.970 14.175 8.410 ;
        RECT 13.680 9.270 14.175 9.710 ;
        RECT 13.680 11.870 14.175 12.310 ;
        RECT 13.680 0.170 14.175 0.610 ;
        RECT 13.680 13.170 14.175 13.610 ;
        RECT 13.680 14.470 14.175 14.910 ;
        RECT 13.680 15.770 14.175 16.210 ;
        RECT 13.680 17.070 14.175 17.510 ;
        RECT 13.680 18.370 14.175 18.810 ;
        RECT 13.680 19.670 14.175 20.110 ;
        RECT 13.680 20.970 14.175 21.410 ;
        RECT 0.080 23.570 0.575 24.010 ;
        RECT 1.780 23.570 2.275 24.010 ;
        RECT 3.480 23.570 3.975 24.010 ;
        RECT 5.180 23.570 5.675 24.010 ;
        RECT 6.880 23.570 7.375 24.010 ;
        RECT 8.580 23.570 9.075 24.010 ;
        RECT 10.280 23.570 10.775 24.010 ;
        RECT 11.980 23.570 12.475 24.010 ;
        RECT 13.680 23.570 14.175 24.010 ;
        RECT 15.380 23.570 15.875 24.010 ;
        RECT 17.080 23.570 17.575 24.010 ;
        RECT 18.780 23.570 19.275 24.010 ;
        RECT 20.480 23.570 20.975 24.010 ;
        RECT 22.180 23.570 22.675 24.010 ;
        RECT 23.880 23.570 24.375 24.010 ;
        RECT 25.580 23.570 26.075 24.010 ;
        RECT 13.680 24.870 14.175 25.310 ;
        RECT 13.680 26.170 14.175 26.610 ;
        RECT 13.680 27.470 14.175 27.910 ;
        RECT 13.680 28.770 14.175 29.210 ;
        RECT 13.680 30.070 14.175 30.510 ;
        RECT 13.680 31.370 14.175 31.810 ;
        RECT 13.680 32.670 14.175 33.110 ;
        RECT 13.680 35.270 14.175 35.710 ;
        RECT 13.680 36.570 14.175 37.010 ;
        RECT 13.680 1.470 14.175 1.910 ;
        RECT 13.680 37.870 14.175 38.310 ;
        RECT 13.680 39.170 14.175 39.610 ;
        RECT 13.680 40.470 14.175 40.910 ;
        RECT 13.680 41.770 14.175 42.210 ;
        RECT 13.680 43.070 14.175 43.510 ;
        RECT 20.480 24.870 20.975 25.310 ;
        RECT 20.480 26.170 20.975 26.610 ;
        RECT 20.480 27.470 20.975 27.910 ;
        RECT 20.480 28.770 20.975 29.210 ;
        RECT 20.480 30.070 20.975 30.510 ;
        RECT 20.480 31.370 20.975 31.810 ;
        RECT 20.480 32.670 20.975 33.110 ;
        RECT 20.480 46.970 20.975 47.410 ;
        RECT 20.480 35.270 20.975 35.710 ;
        RECT 20.480 36.570 20.975 37.010 ;
        RECT 20.480 37.870 20.975 38.310 ;
        RECT 20.480 39.170 20.975 39.610 ;
        RECT 20.480 40.470 20.975 40.910 ;
        RECT 20.480 44.370 20.975 44.810 ;
        RECT 20.480 41.770 20.975 42.210 ;
        RECT 20.480 43.070 20.975 43.510 ;
        RECT 23.880 46.970 24.375 47.410 ;
        RECT 25.580 46.970 26.075 47.410 ;
        RECT 23.880 44.370 24.375 44.810 ;
        RECT 22.180 37.870 22.675 38.310 ;
        RECT 23.880 37.870 24.375 38.310 ;
        RECT 25.580 37.870 26.075 38.310 ;
        RECT 22.180 46.970 22.675 47.410 ;
        RECT 22.180 39.170 22.675 39.610 ;
        RECT 23.880 39.170 24.375 39.610 ;
        RECT 25.580 39.170 26.075 39.610 ;
        RECT 25.580 44.370 26.075 44.810 ;
        RECT 22.180 40.470 22.675 40.910 ;
        RECT 23.880 40.470 24.375 40.910 ;
        RECT 25.580 40.470 26.075 40.910 ;
        RECT 22.180 36.570 22.675 37.010 ;
        RECT 23.880 36.570 24.375 37.010 ;
        RECT 22.180 41.770 22.675 42.210 ;
        RECT 23.880 41.770 24.375 42.210 ;
        RECT 25.580 41.770 26.075 42.210 ;
        RECT 22.180 44.370 22.675 44.810 ;
        RECT 25.580 36.570 26.075 37.010 ;
        RECT 22.180 43.070 22.675 43.510 ;
        RECT 23.880 43.070 24.375 43.510 ;
        RECT 25.580 43.070 26.075 43.510 ;
        RECT 18.780 44.370 19.275 44.810 ;
        RECT 15.380 40.470 15.875 40.910 ;
        RECT 17.080 40.470 17.575 40.910 ;
        RECT 18.780 40.470 19.275 40.910 ;
        RECT 17.080 37.870 17.575 38.310 ;
        RECT 18.780 37.870 19.275 38.310 ;
        RECT 18.780 36.570 19.275 37.010 ;
        RECT 15.380 44.370 15.875 44.810 ;
        RECT 17.080 46.970 17.575 47.410 ;
        RECT 15.380 41.770 15.875 42.210 ;
        RECT 17.080 41.770 17.575 42.210 ;
        RECT 18.780 41.770 19.275 42.210 ;
        RECT 15.380 46.970 15.875 47.410 ;
        RECT 17.080 44.370 17.575 44.810 ;
        RECT 15.380 39.170 15.875 39.610 ;
        RECT 17.080 39.170 17.575 39.610 ;
        RECT 18.780 39.170 19.275 39.610 ;
        RECT 15.380 43.070 15.875 43.510 ;
        RECT 17.080 43.070 17.575 43.510 ;
        RECT 18.780 43.070 19.275 43.510 ;
        RECT 18.780 46.970 19.275 47.410 ;
        RECT 15.380 36.570 15.875 37.010 ;
        RECT 17.080 36.570 17.575 37.010 ;
        RECT 15.380 37.870 15.875 38.310 ;
        RECT 17.080 28.770 17.575 29.210 ;
        RECT 18.780 28.770 19.275 29.210 ;
        RECT 17.080 26.170 17.575 26.610 ;
        RECT 18.780 26.170 19.275 26.610 ;
        RECT 15.380 30.070 15.875 30.510 ;
        RECT 17.080 30.070 17.575 30.510 ;
        RECT 18.780 30.070 19.275 30.510 ;
        RECT 18.780 24.870 19.275 25.310 ;
        RECT 15.380 24.870 15.875 25.310 ;
        RECT 15.380 31.370 15.875 31.810 ;
        RECT 17.080 31.370 17.575 31.810 ;
        RECT 18.780 31.370 19.275 31.810 ;
        RECT 15.380 27.470 15.875 27.910 ;
        RECT 17.080 27.470 17.575 27.910 ;
        RECT 15.380 32.670 15.875 33.110 ;
        RECT 17.080 32.670 17.575 33.110 ;
        RECT 18.780 32.670 19.275 33.110 ;
        RECT 18.780 27.470 19.275 27.910 ;
        RECT 17.080 24.870 17.575 25.310 ;
        RECT 15.380 35.270 15.875 35.710 ;
        RECT 17.080 35.270 17.575 35.710 ;
        RECT 18.780 35.270 19.275 35.710 ;
        RECT 15.380 26.170 15.875 26.610 ;
        RECT 15.380 28.770 15.875 29.210 ;
        RECT 22.180 24.870 22.675 25.310 ;
        RECT 23.880 24.870 24.375 25.310 ;
        RECT 22.180 26.170 22.675 26.610 ;
        RECT 22.180 28.770 22.675 29.210 ;
        RECT 22.180 31.370 22.675 31.810 ;
        RECT 23.880 31.370 24.375 31.810 ;
        RECT 25.580 31.370 26.075 31.810 ;
        RECT 23.880 28.770 24.375 29.210 ;
        RECT 25.580 28.770 26.075 29.210 ;
        RECT 23.880 26.170 24.375 26.610 ;
        RECT 22.180 27.470 22.675 27.910 ;
        RECT 23.880 27.470 24.375 27.910 ;
        RECT 22.180 32.670 22.675 33.110 ;
        RECT 23.880 32.670 24.375 33.110 ;
        RECT 25.580 32.670 26.075 33.110 ;
        RECT 25.580 27.470 26.075 27.910 ;
        RECT 25.580 26.170 26.075 26.610 ;
        RECT 22.180 30.070 22.675 30.510 ;
        RECT 23.880 30.070 24.375 30.510 ;
        RECT 25.580 30.070 26.075 30.510 ;
        RECT 22.180 35.270 22.675 35.710 ;
        RECT 23.880 35.270 24.375 35.710 ;
        RECT 25.580 35.270 26.075 35.710 ;
        RECT 25.580 24.870 26.075 25.310 ;
        RECT 6.880 27.470 7.375 27.910 ;
        RECT 6.880 24.870 7.375 25.310 ;
        RECT 6.880 35.270 7.375 35.710 ;
        RECT 6.880 36.570 7.375 37.010 ;
        RECT 6.880 28.770 7.375 29.210 ;
        RECT 6.880 46.970 7.375 47.410 ;
        RECT 6.880 37.870 7.375 38.310 ;
        RECT 6.880 30.070 7.375 30.510 ;
        RECT 6.880 39.170 7.375 39.610 ;
        RECT 6.880 26.170 7.375 26.610 ;
        RECT 6.880 40.470 7.375 40.910 ;
        RECT 6.880 44.370 7.375 44.810 ;
        RECT 6.880 31.370 7.375 31.810 ;
        RECT 6.880 41.770 7.375 42.210 ;
        RECT 6.880 43.070 7.375 43.510 ;
        RECT 6.880 32.670 7.375 33.110 ;
        RECT 11.980 36.570 12.475 37.010 ;
        RECT 11.980 44.370 12.475 44.810 ;
        RECT 8.580 39.170 9.075 39.610 ;
        RECT 10.280 39.170 10.775 39.610 ;
        RECT 11.980 39.170 12.475 39.610 ;
        RECT 8.580 36.570 9.075 37.010 ;
        RECT 11.980 46.970 12.475 47.410 ;
        RECT 8.580 46.970 9.075 47.410 ;
        RECT 8.580 40.470 9.075 40.910 ;
        RECT 10.280 40.470 10.775 40.910 ;
        RECT 11.980 40.470 12.475 40.910 ;
        RECT 10.280 46.970 10.775 47.410 ;
        RECT 8.580 44.370 9.075 44.810 ;
        RECT 10.280 44.370 10.775 44.810 ;
        RECT 10.280 36.570 10.775 37.010 ;
        RECT 8.580 37.870 9.075 38.310 ;
        RECT 8.580 41.770 9.075 42.210 ;
        RECT 10.280 41.770 10.775 42.210 ;
        RECT 11.980 41.770 12.475 42.210 ;
        RECT 10.280 37.870 10.775 38.310 ;
        RECT 8.580 43.070 9.075 43.510 ;
        RECT 10.280 43.070 10.775 43.510 ;
        RECT 11.980 43.070 12.475 43.510 ;
        RECT 11.980 37.870 12.475 38.310 ;
        RECT 1.780 40.470 2.275 40.910 ;
        RECT 3.480 40.470 3.975 40.910 ;
        RECT 5.180 40.470 5.675 40.910 ;
        RECT 5.180 37.870 5.675 38.310 ;
        RECT 1.780 46.970 2.275 47.410 ;
        RECT 3.480 46.970 3.975 47.410 ;
        RECT 0.080 36.570 0.575 37.010 ;
        RECT 1.780 36.570 2.275 37.010 ;
        RECT 5.180 46.970 5.675 47.410 ;
        RECT 0.080 39.170 0.575 39.610 ;
        RECT 1.780 39.170 2.275 39.610 ;
        RECT 0.080 41.770 0.575 42.210 ;
        RECT 1.780 41.770 2.275 42.210 ;
        RECT 3.480 41.770 3.975 42.210 ;
        RECT 5.180 41.770 5.675 42.210 ;
        RECT 3.480 39.170 3.975 39.610 ;
        RECT 5.180 39.170 5.675 39.610 ;
        RECT 3.480 36.570 3.975 37.010 ;
        RECT 5.180 36.570 5.675 37.010 ;
        RECT 0.080 43.070 0.575 43.510 ;
        RECT 1.780 43.070 2.275 43.510 ;
        RECT 3.480 43.070 3.975 43.510 ;
        RECT 5.180 43.070 5.675 43.510 ;
        RECT 0.080 46.970 0.575 47.410 ;
        RECT 0.080 37.870 0.575 38.310 ;
        RECT 1.780 37.870 2.275 38.310 ;
        RECT 3.480 37.870 3.975 38.310 ;
        RECT 0.080 40.470 0.575 40.910 ;
        RECT 0.080 44.370 0.575 44.810 ;
        RECT 1.780 44.370 2.275 44.810 ;
        RECT 3.480 44.370 3.975 44.810 ;
        RECT 5.180 44.370 5.675 44.810 ;
        RECT 0.080 28.770 0.575 29.210 ;
        RECT 1.780 26.170 2.275 26.610 ;
        RECT 3.480 26.170 3.975 26.610 ;
        RECT 5.180 26.170 5.675 26.610 ;
        RECT 0.080 30.070 0.575 30.510 ;
        RECT 1.780 30.070 2.275 30.510 ;
        RECT 3.480 30.070 3.975 30.510 ;
        RECT 0.080 24.870 0.575 25.310 ;
        RECT 1.780 24.870 2.275 25.310 ;
        RECT 3.480 24.870 3.975 25.310 ;
        RECT 5.180 24.870 5.675 25.310 ;
        RECT 0.080 27.470 0.575 27.910 ;
        RECT 5.180 30.070 5.675 30.510 ;
        RECT 0.080 26.170 0.575 26.610 ;
        RECT 1.780 28.770 2.275 29.210 ;
        RECT 3.480 28.770 3.975 29.210 ;
        RECT 5.180 28.770 5.675 29.210 ;
        RECT 1.780 35.270 2.275 35.710 ;
        RECT 3.480 35.270 3.975 35.710 ;
        RECT 0.080 31.370 0.575 31.810 ;
        RECT 1.780 27.470 2.275 27.910 ;
        RECT 3.480 27.470 3.975 27.910 ;
        RECT 5.180 27.470 5.675 27.910 ;
        RECT 0.080 32.670 0.575 33.110 ;
        RECT 1.780 32.670 2.275 33.110 ;
        RECT 3.480 32.670 3.975 33.110 ;
        RECT 5.180 32.670 5.675 33.110 ;
        RECT 1.780 31.370 2.275 31.810 ;
        RECT 3.480 31.370 3.975 31.810 ;
        RECT 5.180 31.370 5.675 31.810 ;
        RECT 5.180 35.270 5.675 35.710 ;
        RECT 0.080 35.270 0.575 35.710 ;
        RECT 10.280 35.270 10.775 35.710 ;
        RECT 11.980 35.270 12.475 35.710 ;
        RECT 10.280 32.670 10.775 33.110 ;
        RECT 8.580 24.870 9.075 25.310 ;
        RECT 10.280 24.870 10.775 25.310 ;
        RECT 11.980 24.870 12.475 25.310 ;
        RECT 11.980 32.670 12.475 33.110 ;
        RECT 8.580 28.770 9.075 29.210 ;
        RECT 10.280 28.770 10.775 29.210 ;
        RECT 8.580 30.070 9.075 30.510 ;
        RECT 10.280 30.070 10.775 30.510 ;
        RECT 11.980 30.070 12.475 30.510 ;
        RECT 11.980 28.770 12.475 29.210 ;
        RECT 8.580 26.170 9.075 26.610 ;
        RECT 10.280 26.170 10.775 26.610 ;
        RECT 11.980 26.170 12.475 26.610 ;
        RECT 8.580 32.670 9.075 33.110 ;
        RECT 8.580 27.470 9.075 27.910 ;
        RECT 10.280 27.470 10.775 27.910 ;
        RECT 11.980 27.470 12.475 27.910 ;
        RECT 8.580 31.370 9.075 31.810 ;
        RECT 10.280 31.370 10.775 31.810 ;
        RECT 11.980 31.370 12.475 31.810 ;
        RECT 8.580 35.270 9.075 35.710 ;
        RECT 6.880 4.070 7.375 4.510 ;
        RECT 6.880 5.370 7.375 5.810 ;
        RECT 6.880 0.170 7.375 0.610 ;
        RECT 6.880 6.670 7.375 7.110 ;
        RECT 6.880 7.970 7.375 8.410 ;
        RECT 6.880 9.270 7.375 9.710 ;
        RECT 6.880 2.770 7.375 3.210 ;
        RECT 0.080 11.870 0.575 12.310 ;
        RECT 1.780 11.870 2.275 12.310 ;
        RECT 3.480 11.870 3.975 12.310 ;
        RECT 5.180 11.870 5.675 12.310 ;
        RECT 6.880 11.870 7.375 12.310 ;
        RECT 8.580 11.870 9.075 12.310 ;
        RECT 10.280 11.870 10.775 12.310 ;
        RECT 11.980 11.870 12.475 12.310 ;
        RECT 6.880 13.170 7.375 13.610 ;
        RECT 6.880 14.470 7.375 14.910 ;
        RECT 6.880 15.770 7.375 16.210 ;
        RECT 6.880 17.070 7.375 17.510 ;
        RECT 6.880 1.470 7.375 1.910 ;
        RECT 6.880 18.370 7.375 18.810 ;
        RECT 6.880 19.670 7.375 20.110 ;
        RECT 6.880 20.970 7.375 21.410 ;
        RECT 10.280 13.170 10.775 13.610 ;
        RECT 8.580 15.770 9.075 16.210 ;
        RECT 10.280 15.770 10.775 16.210 ;
        RECT 11.980 15.770 12.475 16.210 ;
        RECT 11.980 13.170 12.475 13.610 ;
        RECT 8.580 17.070 9.075 17.510 ;
        RECT 10.280 17.070 10.775 17.510 ;
        RECT 11.980 17.070 12.475 17.510 ;
        RECT 8.580 13.170 9.075 13.610 ;
        RECT 8.580 14.470 9.075 14.910 ;
        RECT 8.580 18.370 9.075 18.810 ;
        RECT 10.280 18.370 10.775 18.810 ;
        RECT 11.980 18.370 12.475 18.810 ;
        RECT 10.280 14.470 10.775 14.910 ;
        RECT 8.580 19.670 9.075 20.110 ;
        RECT 10.280 19.670 10.775 20.110 ;
        RECT 11.980 19.670 12.475 20.110 ;
        RECT 11.980 14.470 12.475 14.910 ;
        RECT 8.580 20.970 9.075 21.410 ;
        RECT 10.280 20.970 10.775 21.410 ;
        RECT 11.980 20.970 12.475 21.410 ;
        RECT 1.780 13.170 2.275 13.610 ;
        RECT 3.480 13.170 3.975 13.610 ;
        RECT 5.180 13.170 5.675 13.610 ;
        RECT 0.080 18.370 0.575 18.810 ;
        RECT 1.780 18.370 2.275 18.810 ;
        RECT 3.480 18.370 3.975 18.810 ;
        RECT 5.180 18.370 5.675 18.810 ;
        RECT 0.080 15.770 0.575 16.210 ;
        RECT 1.780 15.770 2.275 16.210 ;
        RECT 3.480 15.770 3.975 16.210 ;
        RECT 5.180 15.770 5.675 16.210 ;
        RECT 0.080 14.470 0.575 14.910 ;
        RECT 0.080 19.670 0.575 20.110 ;
        RECT 1.780 19.670 2.275 20.110 ;
        RECT 3.480 19.670 3.975 20.110 ;
        RECT 5.180 19.670 5.675 20.110 ;
        RECT 1.780 14.470 2.275 14.910 ;
        RECT 3.480 14.470 3.975 14.910 ;
        RECT 5.180 14.470 5.675 14.910 ;
        RECT 0.080 17.070 0.575 17.510 ;
        RECT 0.080 20.970 0.575 21.410 ;
        RECT 1.780 20.970 2.275 21.410 ;
        RECT 3.480 20.970 3.975 21.410 ;
        RECT 5.180 20.970 5.675 21.410 ;
        RECT 1.780 17.070 2.275 17.510 ;
        RECT 3.480 17.070 3.975 17.510 ;
        RECT 5.180 17.070 5.675 17.510 ;
        RECT 0.080 13.170 0.575 13.610 ;
        RECT 5.180 7.970 5.675 8.410 ;
        RECT 1.780 5.370 2.275 5.810 ;
        RECT 0.080 1.470 0.575 1.910 ;
        RECT 0.080 4.070 0.575 4.510 ;
        RECT 3.480 1.470 3.975 1.910 ;
        RECT 5.180 2.770 5.675 3.210 ;
        RECT 0.080 9.270 0.575 9.710 ;
        RECT 1.780 9.270 2.275 9.710 ;
        RECT 3.480 9.270 3.975 9.710 ;
        RECT 5.180 9.270 5.675 9.710 ;
        RECT 3.480 5.370 3.975 5.810 ;
        RECT 5.180 5.370 5.675 5.810 ;
        RECT 0.080 2.770 0.575 3.210 ;
        RECT 1.780 4.070 2.275 4.510 ;
        RECT 1.780 0.170 2.275 0.610 ;
        RECT 1.780 2.770 2.275 3.210 ;
        RECT 1.780 1.470 2.275 1.910 ;
        RECT 5.180 0.170 5.675 0.610 ;
        RECT 0.080 0.170 0.575 0.610 ;
        RECT 0.080 6.670 0.575 7.110 ;
        RECT 1.780 6.670 2.275 7.110 ;
        RECT 5.180 1.470 5.675 1.910 ;
        RECT 3.480 4.070 3.975 4.510 ;
        RECT 3.480 6.670 3.975 7.110 ;
        RECT 5.180 6.670 5.675 7.110 ;
        RECT 3.480 0.170 3.975 0.610 ;
        RECT 0.080 5.370 0.575 5.810 ;
        RECT 3.480 2.770 3.975 3.210 ;
        RECT 0.080 7.970 0.575 8.410 ;
        RECT 1.780 7.970 2.275 8.410 ;
        RECT 3.480 7.970 3.975 8.410 ;
        RECT 5.180 4.070 5.675 4.510 ;
        RECT 8.580 6.670 9.075 7.110 ;
        RECT 8.580 2.770 9.075 3.210 ;
        RECT 10.280 2.770 10.775 3.210 ;
        RECT 10.280 0.170 10.775 0.610 ;
        RECT 10.280 6.670 10.775 7.110 ;
        RECT 11.980 6.670 12.475 7.110 ;
        RECT 11.980 1.470 12.475 1.910 ;
        RECT 10.280 1.470 10.775 1.910 ;
        RECT 8.580 0.170 9.075 0.610 ;
        RECT 8.580 9.270 9.075 9.710 ;
        RECT 10.280 9.270 10.775 9.710 ;
        RECT 11.980 9.270 12.475 9.710 ;
        RECT 11.980 2.770 12.475 3.210 ;
        RECT 11.980 4.070 12.475 4.510 ;
        RECT 11.980 0.170 12.475 0.610 ;
        RECT 8.580 4.070 9.075 4.510 ;
        RECT 8.580 1.470 9.075 1.910 ;
        RECT 8.580 5.370 9.075 5.810 ;
        RECT 10.280 5.370 10.775 5.810 ;
        RECT 11.980 5.370 12.475 5.810 ;
        RECT 8.580 7.970 9.075 8.410 ;
        RECT 10.280 4.070 10.775 4.510 ;
        RECT 10.280 7.970 10.775 8.410 ;
        RECT 11.980 7.970 12.475 8.410 ;
        RECT 20.480 9.270 20.975 9.710 ;
        RECT 20.480 17.070 20.975 17.510 ;
        RECT 20.480 0.170 20.975 0.610 ;
        RECT 20.480 6.670 20.975 7.110 ;
        RECT 15.380 11.870 15.875 12.310 ;
        RECT 17.080 11.870 17.575 12.310 ;
        RECT 20.480 18.370 20.975 18.810 ;
        RECT 18.780 11.870 19.275 12.310 ;
        RECT 20.480 11.870 20.975 12.310 ;
        RECT 22.180 11.870 22.675 12.310 ;
        RECT 23.880 11.870 24.375 12.310 ;
        RECT 25.580 11.870 26.075 12.310 ;
        RECT 20.480 2.770 20.975 3.210 ;
        RECT 20.480 19.670 20.975 20.110 ;
        RECT 20.480 5.370 20.975 5.810 ;
        RECT 20.480 20.970 20.975 21.410 ;
        RECT 20.480 13.170 20.975 13.610 ;
        RECT 20.480 7.970 20.975 8.410 ;
        RECT 20.480 14.470 20.975 14.910 ;
        RECT 20.480 1.470 20.975 1.910 ;
        RECT 20.480 4.070 20.975 4.510 ;
        RECT 20.480 15.770 20.975 16.210 ;
        RECT 25.580 19.670 26.075 20.110 ;
        RECT 22.180 17.070 22.675 17.510 ;
        RECT 23.880 17.070 24.375 17.510 ;
        RECT 22.180 20.970 22.675 21.410 ;
        RECT 23.880 20.970 24.375 21.410 ;
        RECT 25.580 20.970 26.075 21.410 ;
        RECT 22.180 18.370 22.675 18.810 ;
        RECT 22.180 13.170 22.675 13.610 ;
        RECT 23.880 13.170 24.375 13.610 ;
        RECT 25.580 13.170 26.075 13.610 ;
        RECT 23.880 18.370 24.375 18.810 ;
        RECT 25.580 18.370 26.075 18.810 ;
        RECT 22.180 14.470 22.675 14.910 ;
        RECT 23.880 14.470 24.375 14.910 ;
        RECT 25.580 17.070 26.075 17.510 ;
        RECT 25.580 14.470 26.075 14.910 ;
        RECT 22.180 19.670 22.675 20.110 ;
        RECT 23.880 19.670 24.375 20.110 ;
        RECT 22.180 15.770 22.675 16.210 ;
        RECT 23.880 15.770 24.375 16.210 ;
        RECT 25.580 15.770 26.075 16.210 ;
        RECT 17.080 18.370 17.575 18.810 ;
        RECT 18.780 18.370 19.275 18.810 ;
        RECT 18.780 17.070 19.275 17.510 ;
        RECT 15.380 17.070 15.875 17.510 ;
        RECT 17.080 17.070 17.575 17.510 ;
        RECT 15.380 14.470 15.875 14.910 ;
        RECT 17.080 14.470 17.575 14.910 ;
        RECT 18.780 14.470 19.275 14.910 ;
        RECT 15.380 13.170 15.875 13.610 ;
        RECT 17.080 13.170 17.575 13.610 ;
        RECT 18.780 13.170 19.275 13.610 ;
        RECT 15.380 20.970 15.875 21.410 ;
        RECT 17.080 20.970 17.575 21.410 ;
        RECT 18.780 20.970 19.275 21.410 ;
        RECT 15.380 15.770 15.875 16.210 ;
        RECT 17.080 15.770 17.575 16.210 ;
        RECT 18.780 15.770 19.275 16.210 ;
        RECT 15.380 18.370 15.875 18.810 ;
        RECT 15.380 19.670 15.875 20.110 ;
        RECT 17.080 19.670 17.575 20.110 ;
        RECT 18.780 19.670 19.275 20.110 ;
        RECT 18.780 7.970 19.275 8.410 ;
        RECT 18.780 2.770 19.275 3.210 ;
        RECT 15.380 6.670 15.875 7.110 ;
        RECT 17.080 6.670 17.575 7.110 ;
        RECT 18.780 6.670 19.275 7.110 ;
        RECT 18.780 9.270 19.275 9.710 ;
        RECT 15.380 2.770 15.875 3.210 ;
        RECT 15.380 4.070 15.875 4.510 ;
        RECT 15.380 5.370 15.875 5.810 ;
        RECT 17.080 5.370 17.575 5.810 ;
        RECT 17.080 0.170 17.575 0.610 ;
        RECT 17.080 4.070 17.575 4.510 ;
        RECT 18.780 4.070 19.275 4.510 ;
        RECT 18.780 5.370 19.275 5.810 ;
        RECT 15.380 9.270 15.875 9.710 ;
        RECT 17.080 1.470 17.575 1.910 ;
        RECT 15.380 1.470 15.875 1.910 ;
        RECT 17.080 2.770 17.575 3.210 ;
        RECT 18.780 1.470 19.275 1.910 ;
        RECT 15.380 0.170 15.875 0.610 ;
        RECT 15.380 7.970 15.875 8.410 ;
        RECT 17.080 7.970 17.575 8.410 ;
        RECT 18.780 0.170 19.275 0.610 ;
        RECT 17.080 9.270 17.575 9.710 ;
        RECT 25.580 6.670 26.075 7.110 ;
        RECT 22.180 9.270 22.675 9.710 ;
        RECT 23.880 9.270 24.375 9.710 ;
        RECT 25.580 9.270 26.075 9.710 ;
        RECT 22.180 0.170 22.675 0.610 ;
        RECT 25.580 5.370 26.075 5.810 ;
        RECT 23.880 0.170 24.375 0.610 ;
        RECT 23.880 1.470 24.375 1.910 ;
        RECT 22.180 2.770 22.675 3.210 ;
        RECT 22.180 4.070 22.675 4.510 ;
        RECT 23.880 4.070 24.375 4.510 ;
        RECT 25.580 4.070 26.075 4.510 ;
        RECT 25.580 1.470 26.075 1.910 ;
        RECT 23.880 2.770 24.375 3.210 ;
        RECT 22.180 7.970 22.675 8.410 ;
        RECT 23.880 7.970 24.375 8.410 ;
        RECT 25.580 7.970 26.075 8.410 ;
        RECT 22.180 5.370 22.675 5.810 ;
        RECT 23.880 5.370 24.375 5.810 ;
        RECT 22.180 1.470 22.675 1.910 ;
        RECT 25.580 2.770 26.075 3.210 ;
        RECT 22.180 6.670 22.675 7.110 ;
        RECT 25.580 0.170 26.075 0.610 ;
        RECT 23.880 6.670 24.375 7.110 ;
        RECT 40.880 26.170 41.375 26.610 ;
        RECT 40.880 1.470 41.375 1.910 ;
        RECT 40.880 6.670 41.375 7.110 ;
        RECT 40.880 27.470 41.375 27.910 ;
        RECT 40.880 14.470 41.375 14.910 ;
        RECT 40.880 28.770 41.375 29.210 ;
        RECT 40.880 30.070 41.375 30.510 ;
        RECT 40.880 15.770 41.375 16.210 ;
        RECT 40.880 31.370 41.375 31.810 ;
        RECT 40.880 7.970 41.375 8.410 ;
        RECT 40.880 32.670 41.375 33.110 ;
        RECT 40.880 17.070 41.375 17.510 ;
        RECT 40.880 4.070 41.375 4.510 ;
        RECT 40.880 35.270 41.375 35.710 ;
        RECT 40.880 0.170 41.375 0.610 ;
        RECT 40.880 18.370 41.375 18.810 ;
        RECT 40.880 36.570 41.375 37.010 ;
        RECT 40.880 9.270 41.375 9.710 ;
        RECT 40.880 37.870 41.375 38.310 ;
        RECT 40.880 19.670 41.375 20.110 ;
        RECT 40.880 39.170 41.375 39.610 ;
        RECT 40.880 40.470 41.375 40.910 ;
        RECT 40.880 20.970 41.375 21.410 ;
        RECT 40.880 41.770 41.375 42.210 ;
        RECT 40.880 5.370 41.375 5.810 ;
        RECT 40.880 11.870 41.375 12.310 ;
        RECT 40.880 43.070 41.375 43.510 ;
        RECT 28.980 23.570 29.475 24.010 ;
        RECT 30.680 23.570 31.175 24.010 ;
        RECT 32.380 23.570 32.875 24.010 ;
        RECT 34.080 23.570 34.575 24.010 ;
        RECT 35.780 23.570 36.275 24.010 ;
        RECT 37.480 23.570 37.975 24.010 ;
        RECT 39.180 23.570 39.675 24.010 ;
        RECT 40.880 23.570 41.375 24.010 ;
        RECT 42.580 23.570 43.075 24.010 ;
        RECT 44.280 23.570 44.775 24.010 ;
        RECT 45.980 23.570 46.475 24.010 ;
        RECT 47.680 23.570 48.175 24.010 ;
        RECT 49.380 23.570 49.875 24.010 ;
        RECT 51.080 23.570 51.575 24.010 ;
        RECT 52.780 23.570 53.275 24.010 ;
        RECT 40.880 44.370 41.375 44.810 ;
        RECT 40.880 2.770 41.375 3.210 ;
        RECT 40.880 46.970 41.375 47.410 ;
        RECT 40.880 24.870 41.375 25.310 ;
        RECT 40.880 13.170 41.375 13.610 ;
        RECT 47.680 32.670 48.175 33.110 ;
        RECT 47.680 35.270 48.175 35.710 ;
        RECT 47.680 27.470 48.175 27.910 ;
        RECT 47.680 36.570 48.175 37.010 ;
        RECT 47.680 26.170 48.175 26.610 ;
        RECT 47.680 37.870 48.175 38.310 ;
        RECT 47.680 39.170 48.175 39.610 ;
        RECT 47.680 40.470 48.175 40.910 ;
        RECT 47.680 28.770 48.175 29.210 ;
        RECT 47.680 41.770 48.175 42.210 ;
        RECT 47.680 43.070 48.175 43.510 ;
        RECT 47.680 30.070 48.175 30.510 ;
        RECT 47.680 31.370 48.175 31.810 ;
        RECT 47.680 44.370 48.175 44.810 ;
        RECT 47.680 46.970 48.175 47.410 ;
        RECT 47.680 24.870 48.175 25.310 ;
        RECT 49.380 36.570 49.875 37.010 ;
        RECT 49.380 40.470 49.875 40.910 ;
        RECT 51.080 40.470 51.575 40.910 ;
        RECT 52.780 40.470 53.275 40.910 ;
        RECT 51.080 36.570 51.575 37.010 ;
        RECT 49.380 37.870 49.875 38.310 ;
        RECT 49.380 41.770 49.875 42.210 ;
        RECT 51.080 41.770 51.575 42.210 ;
        RECT 52.780 41.770 53.275 42.210 ;
        RECT 51.080 37.870 51.575 38.310 ;
        RECT 49.380 43.070 49.875 43.510 ;
        RECT 51.080 43.070 51.575 43.510 ;
        RECT 52.780 43.070 53.275 43.510 ;
        RECT 52.780 37.870 53.275 38.310 ;
        RECT 52.780 36.570 53.275 37.010 ;
        RECT 49.380 39.170 49.875 39.610 ;
        RECT 49.380 44.370 49.875 44.810 ;
        RECT 51.080 44.370 51.575 44.810 ;
        RECT 52.780 44.370 53.275 44.810 ;
        RECT 51.080 39.170 51.575 39.610 ;
        RECT 49.380 46.970 49.875 47.410 ;
        RECT 51.080 46.970 51.575 47.410 ;
        RECT 52.780 46.970 53.275 47.410 ;
        RECT 52.780 39.170 53.275 39.610 ;
        RECT 42.580 43.070 43.075 43.510 ;
        RECT 44.280 43.070 44.775 43.510 ;
        RECT 45.980 43.070 46.475 43.510 ;
        RECT 42.580 40.470 43.075 40.910 ;
        RECT 44.280 40.470 44.775 40.910 ;
        RECT 45.980 40.470 46.475 40.910 ;
        RECT 44.280 36.570 44.775 37.010 ;
        RECT 42.580 37.870 43.075 38.310 ;
        RECT 42.580 39.170 43.075 39.610 ;
        RECT 42.580 44.370 43.075 44.810 ;
        RECT 44.280 44.370 44.775 44.810 ;
        RECT 45.980 44.370 46.475 44.810 ;
        RECT 44.280 39.170 44.775 39.610 ;
        RECT 45.980 39.170 46.475 39.610 ;
        RECT 42.580 41.770 43.075 42.210 ;
        RECT 44.280 41.770 44.775 42.210 ;
        RECT 42.580 46.970 43.075 47.410 ;
        RECT 44.280 46.970 44.775 47.410 ;
        RECT 45.980 46.970 46.475 47.410 ;
        RECT 45.980 41.770 46.475 42.210 ;
        RECT 44.280 37.870 44.775 38.310 ;
        RECT 45.980 37.870 46.475 38.310 ;
        RECT 45.980 36.570 46.475 37.010 ;
        RECT 42.580 36.570 43.075 37.010 ;
        RECT 44.280 31.370 44.775 31.810 ;
        RECT 45.980 31.370 46.475 31.810 ;
        RECT 44.280 32.670 44.775 33.110 ;
        RECT 42.580 27.470 43.075 27.910 ;
        RECT 44.280 27.470 44.775 27.910 ;
        RECT 45.980 27.470 46.475 27.910 ;
        RECT 42.580 35.270 43.075 35.710 ;
        RECT 45.980 28.770 46.475 29.210 ;
        RECT 44.280 35.270 44.775 35.710 ;
        RECT 45.980 35.270 46.475 35.710 ;
        RECT 44.280 26.170 44.775 26.610 ;
        RECT 44.280 28.770 44.775 29.210 ;
        RECT 45.980 32.670 46.475 33.110 ;
        RECT 42.580 30.070 43.075 30.510 ;
        RECT 44.280 30.070 44.775 30.510 ;
        RECT 45.980 30.070 46.475 30.510 ;
        RECT 42.580 28.770 43.075 29.210 ;
        RECT 42.580 26.170 43.075 26.610 ;
        RECT 45.980 26.170 46.475 26.610 ;
        RECT 42.580 24.870 43.075 25.310 ;
        RECT 44.280 24.870 44.775 25.310 ;
        RECT 45.980 24.870 46.475 25.310 ;
        RECT 42.580 31.370 43.075 31.810 ;
        RECT 42.580 32.670 43.075 33.110 ;
        RECT 49.380 26.170 49.875 26.610 ;
        RECT 52.780 27.470 53.275 27.910 ;
        RECT 51.080 27.470 51.575 27.910 ;
        RECT 51.080 26.170 51.575 26.610 ;
        RECT 52.780 32.670 53.275 33.110 ;
        RECT 49.380 32.670 49.875 33.110 ;
        RECT 52.780 31.370 53.275 31.810 ;
        RECT 49.380 35.270 49.875 35.710 ;
        RECT 49.380 28.770 49.875 29.210 ;
        RECT 49.380 30.070 49.875 30.510 ;
        RECT 51.080 30.070 51.575 30.510 ;
        RECT 52.780 30.070 53.275 30.510 ;
        RECT 52.780 26.170 53.275 26.610 ;
        RECT 51.080 28.770 51.575 29.210 ;
        RECT 52.780 28.770 53.275 29.210 ;
        RECT 51.080 35.270 51.575 35.710 ;
        RECT 52.780 35.270 53.275 35.710 ;
        RECT 51.080 32.670 51.575 33.110 ;
        RECT 49.380 31.370 49.875 31.810 ;
        RECT 51.080 31.370 51.575 31.810 ;
        RECT 49.380 24.870 49.875 25.310 ;
        RECT 51.080 24.870 51.575 25.310 ;
        RECT 52.780 24.870 53.275 25.310 ;
        RECT 49.380 27.470 49.875 27.910 ;
        RECT 34.080 40.470 34.575 40.910 ;
        RECT 34.080 35.270 34.575 35.710 ;
        RECT 34.080 41.770 34.575 42.210 ;
        RECT 34.080 28.770 34.575 29.210 ;
        RECT 34.080 31.370 34.575 31.810 ;
        RECT 34.080 43.070 34.575 43.510 ;
        RECT 34.080 36.570 34.575 37.010 ;
        RECT 34.080 37.870 34.575 38.310 ;
        RECT 34.080 44.370 34.575 44.810 ;
        RECT 34.080 27.470 34.575 27.910 ;
        RECT 34.080 32.670 34.575 33.110 ;
        RECT 34.080 46.970 34.575 47.410 ;
        RECT 34.080 39.170 34.575 39.610 ;
        RECT 34.080 24.870 34.575 25.310 ;
        RECT 34.080 30.070 34.575 30.510 ;
        RECT 34.080 26.170 34.575 26.610 ;
        RECT 35.780 36.570 36.275 37.010 ;
        RECT 37.480 36.570 37.975 37.010 ;
        RECT 39.180 36.570 39.675 37.010 ;
        RECT 37.480 41.770 37.975 42.210 ;
        RECT 35.780 37.870 36.275 38.310 ;
        RECT 37.480 37.870 37.975 38.310 ;
        RECT 39.180 37.870 39.675 38.310 ;
        RECT 39.180 41.770 39.675 42.210 ;
        RECT 35.780 44.370 36.275 44.810 ;
        RECT 37.480 44.370 37.975 44.810 ;
        RECT 39.180 44.370 39.675 44.810 ;
        RECT 39.180 40.470 39.675 40.910 ;
        RECT 35.780 40.470 36.275 40.910 ;
        RECT 37.480 40.470 37.975 40.910 ;
        RECT 35.780 46.970 36.275 47.410 ;
        RECT 37.480 46.970 37.975 47.410 ;
        RECT 39.180 46.970 39.675 47.410 ;
        RECT 35.780 43.070 36.275 43.510 ;
        RECT 35.780 39.170 36.275 39.610 ;
        RECT 37.480 39.170 37.975 39.610 ;
        RECT 39.180 39.170 39.675 39.610 ;
        RECT 37.480 43.070 37.975 43.510 ;
        RECT 39.180 43.070 39.675 43.510 ;
        RECT 35.780 41.770 36.275 42.210 ;
        RECT 32.380 36.570 32.875 37.010 ;
        RECT 28.980 43.070 29.475 43.510 ;
        RECT 30.680 43.070 31.175 43.510 ;
        RECT 32.380 43.070 32.875 43.510 ;
        RECT 30.680 41.770 31.175 42.210 ;
        RECT 28.980 46.970 29.475 47.410 ;
        RECT 30.680 46.970 31.175 47.410 ;
        RECT 32.380 46.970 32.875 47.410 ;
        RECT 28.980 37.870 29.475 38.310 ;
        RECT 30.680 37.870 31.175 38.310 ;
        RECT 32.380 37.870 32.875 38.310 ;
        RECT 32.380 41.770 32.875 42.210 ;
        RECT 28.980 39.170 29.475 39.610 ;
        RECT 30.680 39.170 31.175 39.610 ;
        RECT 32.380 39.170 32.875 39.610 ;
        RECT 32.380 40.470 32.875 40.910 ;
        RECT 28.980 41.770 29.475 42.210 ;
        RECT 28.980 36.570 29.475 37.010 ;
        RECT 28.980 44.370 29.475 44.810 ;
        RECT 30.680 44.370 31.175 44.810 ;
        RECT 32.380 44.370 32.875 44.810 ;
        RECT 28.980 40.470 29.475 40.910 ;
        RECT 30.680 40.470 31.175 40.910 ;
        RECT 30.680 36.570 31.175 37.010 ;
        RECT 32.380 28.770 32.875 29.210 ;
        RECT 30.680 35.270 31.175 35.710 ;
        RECT 28.980 27.470 29.475 27.910 ;
        RECT 30.680 27.470 31.175 27.910 ;
        RECT 32.380 27.470 32.875 27.910 ;
        RECT 28.980 31.370 29.475 31.810 ;
        RECT 30.680 31.370 31.175 31.810 ;
        RECT 32.380 31.370 32.875 31.810 ;
        RECT 28.980 30.070 29.475 30.510 ;
        RECT 28.980 32.670 29.475 33.110 ;
        RECT 30.680 32.670 31.175 33.110 ;
        RECT 30.680 30.070 31.175 30.510 ;
        RECT 28.980 24.870 29.475 25.310 ;
        RECT 30.680 24.870 31.175 25.310 ;
        RECT 32.380 24.870 32.875 25.310 ;
        RECT 32.380 32.670 32.875 33.110 ;
        RECT 32.380 30.070 32.875 30.510 ;
        RECT 32.380 35.270 32.875 35.710 ;
        RECT 28.980 28.770 29.475 29.210 ;
        RECT 30.680 28.770 31.175 29.210 ;
        RECT 28.980 26.170 29.475 26.610 ;
        RECT 30.680 26.170 31.175 26.610 ;
        RECT 32.380 26.170 32.875 26.610 ;
        RECT 28.980 35.270 29.475 35.710 ;
        RECT 39.180 31.370 39.675 31.810 ;
        RECT 39.180 27.470 39.675 27.910 ;
        RECT 35.780 32.670 36.275 33.110 ;
        RECT 37.480 32.670 37.975 33.110 ;
        RECT 39.180 32.670 39.675 33.110 ;
        RECT 37.480 26.170 37.975 26.610 ;
        RECT 39.180 26.170 39.675 26.610 ;
        RECT 35.780 26.170 36.275 26.610 ;
        RECT 35.780 24.870 36.275 25.310 ;
        RECT 37.480 24.870 37.975 25.310 ;
        RECT 39.180 24.870 39.675 25.310 ;
        RECT 37.480 28.770 37.975 29.210 ;
        RECT 39.180 28.770 39.675 29.210 ;
        RECT 35.780 30.070 36.275 30.510 ;
        RECT 37.480 30.070 37.975 30.510 ;
        RECT 39.180 30.070 39.675 30.510 ;
        RECT 35.780 27.470 36.275 27.910 ;
        RECT 37.480 27.470 37.975 27.910 ;
        RECT 35.780 35.270 36.275 35.710 ;
        RECT 37.480 35.270 37.975 35.710 ;
        RECT 39.180 35.270 39.675 35.710 ;
        RECT 35.780 28.770 36.275 29.210 ;
        RECT 35.780 31.370 36.275 31.810 ;
        RECT 37.480 31.370 37.975 31.810 ;
        RECT 34.080 9.270 34.575 9.710 ;
        RECT 28.980 11.870 29.475 12.310 ;
        RECT 30.680 11.870 31.175 12.310 ;
        RECT 32.380 11.870 32.875 12.310 ;
        RECT 34.080 11.870 34.575 12.310 ;
        RECT 35.780 11.870 36.275 12.310 ;
        RECT 37.480 11.870 37.975 12.310 ;
        RECT 39.180 11.870 39.675 12.310 ;
        RECT 34.080 14.470 34.575 14.910 ;
        RECT 34.080 4.070 34.575 4.510 ;
        RECT 34.080 19.670 34.575 20.110 ;
        RECT 34.080 0.170 34.575 0.610 ;
        RECT 34.080 15.770 34.575 16.210 ;
        RECT 34.080 2.770 34.575 3.210 ;
        RECT 34.080 18.370 34.575 18.810 ;
        RECT 34.080 7.970 34.575 8.410 ;
        RECT 34.080 5.370 34.575 5.810 ;
        RECT 34.080 20.970 34.575 21.410 ;
        RECT 34.080 13.170 34.575 13.610 ;
        RECT 34.080 6.670 34.575 7.110 ;
        RECT 34.080 1.470 34.575 1.910 ;
        RECT 34.080 17.070 34.575 17.510 ;
        RECT 37.480 15.770 37.975 16.210 ;
        RECT 35.780 15.770 36.275 16.210 ;
        RECT 39.180 14.470 39.675 14.910 ;
        RECT 39.180 15.770 39.675 16.210 ;
        RECT 35.780 14.470 36.275 14.910 ;
        RECT 35.780 18.370 36.275 18.810 ;
        RECT 37.480 18.370 37.975 18.810 ;
        RECT 39.180 18.370 39.675 18.810 ;
        RECT 35.780 17.070 36.275 17.510 ;
        RECT 37.480 17.070 37.975 17.510 ;
        RECT 35.780 19.670 36.275 20.110 ;
        RECT 35.780 20.970 36.275 21.410 ;
        RECT 37.480 20.970 37.975 21.410 ;
        RECT 39.180 20.970 39.675 21.410 ;
        RECT 37.480 19.670 37.975 20.110 ;
        RECT 35.780 13.170 36.275 13.610 ;
        RECT 37.480 13.170 37.975 13.610 ;
        RECT 39.180 13.170 39.675 13.610 ;
        RECT 39.180 19.670 39.675 20.110 ;
        RECT 37.480 14.470 37.975 14.910 ;
        RECT 39.180 17.070 39.675 17.510 ;
        RECT 32.380 15.770 32.875 16.210 ;
        RECT 32.380 14.470 32.875 14.910 ;
        RECT 28.980 20.970 29.475 21.410 ;
        RECT 30.680 20.970 31.175 21.410 ;
        RECT 32.380 20.970 32.875 21.410 ;
        RECT 28.980 14.470 29.475 14.910 ;
        RECT 30.680 14.470 31.175 14.910 ;
        RECT 28.980 19.670 29.475 20.110 ;
        RECT 28.980 13.170 29.475 13.610 ;
        RECT 30.680 13.170 31.175 13.610 ;
        RECT 32.380 13.170 32.875 13.610 ;
        RECT 28.980 18.370 29.475 18.810 ;
        RECT 30.680 18.370 31.175 18.810 ;
        RECT 32.380 18.370 32.875 18.810 ;
        RECT 30.680 19.670 31.175 20.110 ;
        RECT 32.380 19.670 32.875 20.110 ;
        RECT 28.980 15.770 29.475 16.210 ;
        RECT 28.980 17.070 29.475 17.510 ;
        RECT 30.680 17.070 31.175 17.510 ;
        RECT 32.380 17.070 32.875 17.510 ;
        RECT 30.680 15.770 31.175 16.210 ;
        RECT 32.380 6.670 32.875 7.110 ;
        RECT 32.380 7.970 32.875 8.410 ;
        RECT 28.980 0.170 29.475 0.610 ;
        RECT 30.680 0.170 31.175 0.610 ;
        RECT 28.980 1.470 29.475 1.910 ;
        RECT 30.680 1.470 31.175 1.910 ;
        RECT 28.980 2.770 29.475 3.210 ;
        RECT 30.680 2.770 31.175 3.210 ;
        RECT 32.380 2.770 32.875 3.210 ;
        RECT 32.380 0.170 32.875 0.610 ;
        RECT 32.380 4.070 32.875 4.510 ;
        RECT 28.980 5.370 29.475 5.810 ;
        RECT 30.680 5.370 31.175 5.810 ;
        RECT 32.380 5.370 32.875 5.810 ;
        RECT 28.980 6.670 29.475 7.110 ;
        RECT 28.980 4.070 29.475 4.510 ;
        RECT 28.980 9.270 29.475 9.710 ;
        RECT 30.680 9.270 31.175 9.710 ;
        RECT 32.380 1.470 32.875 1.910 ;
        RECT 32.380 9.270 32.875 9.710 ;
        RECT 28.980 7.970 29.475 8.410 ;
        RECT 30.680 7.970 31.175 8.410 ;
        RECT 30.680 4.070 31.175 4.510 ;
        RECT 30.680 6.670 31.175 7.110 ;
        RECT 35.780 5.370 36.275 5.810 ;
        RECT 37.480 5.370 37.975 5.810 ;
        RECT 39.180 5.370 39.675 5.810 ;
        RECT 37.480 6.670 37.975 7.110 ;
        RECT 39.180 6.670 39.675 7.110 ;
        RECT 37.480 1.470 37.975 1.910 ;
        RECT 39.180 9.270 39.675 9.710 ;
        RECT 39.180 0.170 39.675 0.610 ;
        RECT 35.780 4.070 36.275 4.510 ;
        RECT 37.480 4.070 37.975 4.510 ;
        RECT 39.180 7.970 39.675 8.410 ;
        RECT 35.780 6.670 36.275 7.110 ;
        RECT 35.780 9.270 36.275 9.710 ;
        RECT 39.180 4.070 39.675 4.510 ;
        RECT 39.180 1.470 39.675 1.910 ;
        RECT 35.780 1.470 36.275 1.910 ;
        RECT 35.780 0.170 36.275 0.610 ;
        RECT 37.480 0.170 37.975 0.610 ;
        RECT 35.780 2.770 36.275 3.210 ;
        RECT 37.480 2.770 37.975 3.210 ;
        RECT 39.180 2.770 39.675 3.210 ;
        RECT 35.780 7.970 36.275 8.410 ;
        RECT 37.480 7.970 37.975 8.410 ;
        RECT 37.480 9.270 37.975 9.710 ;
        RECT 47.680 19.670 48.175 20.110 ;
        RECT 52.780 11.870 53.275 12.310 ;
        RECT 47.680 17.070 48.175 17.510 ;
        RECT 47.680 18.370 48.175 18.810 ;
        RECT 47.680 0.170 48.175 0.610 ;
        RECT 47.680 15.770 48.175 16.210 ;
        RECT 47.680 4.070 48.175 4.510 ;
        RECT 47.680 7.970 48.175 8.410 ;
        RECT 47.680 5.370 48.175 5.810 ;
        RECT 47.680 6.670 48.175 7.110 ;
        RECT 47.680 2.770 48.175 3.210 ;
        RECT 47.680 20.970 48.175 21.410 ;
        RECT 47.680 9.270 48.175 9.710 ;
        RECT 47.680 1.470 48.175 1.910 ;
        RECT 42.580 11.870 43.075 12.310 ;
        RECT 44.280 11.870 44.775 12.310 ;
        RECT 45.980 11.870 46.475 12.310 ;
        RECT 47.680 13.170 48.175 13.610 ;
        RECT 47.680 11.870 48.175 12.310 ;
        RECT 49.380 11.870 49.875 12.310 ;
        RECT 51.080 11.870 51.575 12.310 ;
        RECT 47.680 14.470 48.175 14.910 ;
        RECT 51.080 17.070 51.575 17.510 ;
        RECT 52.780 17.070 53.275 17.510 ;
        RECT 51.080 19.670 51.575 20.110 ;
        RECT 49.380 18.370 49.875 18.810 ;
        RECT 49.380 20.970 49.875 21.410 ;
        RECT 51.080 18.370 51.575 18.810 ;
        RECT 52.780 18.370 53.275 18.810 ;
        RECT 51.080 20.970 51.575 21.410 ;
        RECT 52.780 20.970 53.275 21.410 ;
        RECT 52.780 19.670 53.275 20.110 ;
        RECT 51.080 14.470 51.575 14.910 ;
        RECT 49.380 19.670 49.875 20.110 ;
        RECT 49.380 15.770 49.875 16.210 ;
        RECT 49.380 13.170 49.875 13.610 ;
        RECT 51.080 13.170 51.575 13.610 ;
        RECT 52.780 13.170 53.275 13.610 ;
        RECT 51.080 15.770 51.575 16.210 ;
        RECT 52.780 15.770 53.275 16.210 ;
        RECT 49.380 17.070 49.875 17.510 ;
        RECT 52.780 14.470 53.275 14.910 ;
        RECT 49.380 14.470 49.875 14.910 ;
        RECT 44.280 19.670 44.775 20.110 ;
        RECT 45.980 19.670 46.475 20.110 ;
        RECT 42.580 14.470 43.075 14.910 ;
        RECT 44.280 14.470 44.775 14.910 ;
        RECT 45.980 14.470 46.475 14.910 ;
        RECT 44.280 18.370 44.775 18.810 ;
        RECT 45.980 18.370 46.475 18.810 ;
        RECT 42.580 20.970 43.075 21.410 ;
        RECT 42.580 13.170 43.075 13.610 ;
        RECT 44.280 13.170 44.775 13.610 ;
        RECT 45.980 13.170 46.475 13.610 ;
        RECT 44.280 20.970 44.775 21.410 ;
        RECT 45.980 20.970 46.475 21.410 ;
        RECT 45.980 17.070 46.475 17.510 ;
        RECT 42.580 15.770 43.075 16.210 ;
        RECT 44.280 15.770 44.775 16.210 ;
        RECT 42.580 17.070 43.075 17.510 ;
        RECT 44.280 17.070 44.775 17.510 ;
        RECT 42.580 18.370 43.075 18.810 ;
        RECT 45.980 15.770 46.475 16.210 ;
        RECT 42.580 19.670 43.075 20.110 ;
        RECT 45.980 4.070 46.475 4.510 ;
        RECT 42.580 2.770 43.075 3.210 ;
        RECT 44.280 2.770 44.775 3.210 ;
        RECT 45.980 2.770 46.475 3.210 ;
        RECT 42.580 6.670 43.075 7.110 ;
        RECT 42.580 7.970 43.075 8.410 ;
        RECT 44.280 6.670 44.775 7.110 ;
        RECT 42.580 1.470 43.075 1.910 ;
        RECT 44.280 7.970 44.775 8.410 ;
        RECT 45.980 7.970 46.475 8.410 ;
        RECT 42.580 5.370 43.075 5.810 ;
        RECT 42.580 4.070 43.075 4.510 ;
        RECT 44.280 5.370 44.775 5.810 ;
        RECT 42.580 9.270 43.075 9.710 ;
        RECT 44.280 9.270 44.775 9.710 ;
        RECT 45.980 9.270 46.475 9.710 ;
        RECT 45.980 5.370 46.475 5.810 ;
        RECT 44.280 1.470 44.775 1.910 ;
        RECT 45.980 1.470 46.475 1.910 ;
        RECT 42.580 0.170 43.075 0.610 ;
        RECT 44.280 0.170 44.775 0.610 ;
        RECT 45.980 0.170 46.475 0.610 ;
        RECT 44.280 4.070 44.775 4.510 ;
        RECT 45.980 6.670 46.475 7.110 ;
        RECT 52.780 0.170 53.275 0.610 ;
        RECT 51.080 1.470 51.575 1.910 ;
        RECT 52.780 1.470 53.275 1.910 ;
        RECT 49.380 6.670 49.875 7.110 ;
        RECT 51.080 4.070 51.575 4.510 ;
        RECT 51.080 6.670 51.575 7.110 ;
        RECT 49.380 0.170 49.875 0.610 ;
        RECT 51.080 0.170 51.575 0.610 ;
        RECT 49.380 7.970 49.875 8.410 ;
        RECT 49.380 9.270 49.875 9.710 ;
        RECT 51.080 9.270 51.575 9.710 ;
        RECT 52.780 4.070 53.275 4.510 ;
        RECT 51.080 7.970 51.575 8.410 ;
        RECT 49.380 2.770 49.875 3.210 ;
        RECT 51.080 2.770 51.575 3.210 ;
        RECT 52.780 6.670 53.275 7.110 ;
        RECT 52.780 7.970 53.275 8.410 ;
        RECT 52.780 2.770 53.275 3.210 ;
        RECT 49.380 5.370 49.875 5.810 ;
        RECT 49.380 1.470 49.875 1.910 ;
        RECT 49.380 4.070 49.875 4.510 ;
        RECT 51.080 5.370 51.575 5.810 ;
        RECT 52.780 5.370 53.275 5.810 ;
        RECT 52.780 9.270 53.275 9.710 ;
      LAYER met3 ;
        RECT 27.280 0.170 27.750 0.610 ;
        RECT 27.280 1.470 27.750 1.910 ;
        RECT 27.280 2.770 27.750 3.210 ;
        RECT 27.280 4.070 27.750 4.510 ;
        RECT 27.280 5.370 27.750 5.810 ;
        RECT 27.280 6.670 27.750 7.110 ;
        RECT 27.280 7.970 27.750 8.410 ;
        RECT 27.280 9.270 27.750 9.710 ;
        RECT 27.280 11.870 27.750 12.310 ;
        RECT 27.280 13.170 27.750 13.610 ;
        RECT 27.280 14.470 27.750 14.910 ;
        RECT 27.280 15.770 27.750 16.210 ;
        RECT 27.280 17.070 27.750 17.510 ;
        RECT 27.280 18.370 27.750 18.810 ;
        RECT 27.280 19.670 27.750 20.110 ;
        RECT 27.280 20.970 27.750 21.410 ;
        RECT 27.280 23.570 27.750 24.010 ;
        RECT 27.280 24.870 27.750 25.310 ;
        RECT 27.280 26.170 27.750 26.610 ;
        RECT 27.280 27.470 27.750 27.910 ;
        RECT 27.280 28.770 27.750 29.210 ;
        RECT 27.280 30.070 27.750 30.510 ;
        RECT 27.280 31.370 27.750 31.810 ;
        RECT 27.280 32.670 27.750 33.110 ;
        RECT 27.280 35.270 27.750 35.710 ;
        RECT 27.280 36.570 27.750 37.010 ;
        RECT 27.280 37.870 27.750 38.310 ;
        RECT 27.280 39.170 27.750 39.610 ;
        RECT 27.280 40.470 27.750 40.910 ;
        RECT 27.280 41.770 27.750 42.210 ;
        RECT 27.280 43.070 27.750 43.510 ;
        RECT 27.280 44.370 27.750 44.810 ;
        RECT 27.280 46.970 27.750 47.410 ;
        RECT 27.280 48.270 27.750 48.710 ;
        RECT 27.280 49.570 27.750 50.010 ;
        RECT 27.280 50.870 27.750 51.310 ;
        RECT 27.280 52.170 27.750 52.610 ;
        RECT 27.280 53.470 27.750 53.910 ;
        RECT 27.280 54.770 27.750 55.210 ;
        RECT 27.280 56.070 27.750 56.510 ;
        RECT 27.280 58.670 27.750 59.110 ;
        RECT 27.280 59.970 27.750 60.410 ;
        RECT 27.280 61.270 27.750 61.710 ;
        RECT 27.280 62.570 27.750 63.010 ;
        RECT 27.280 63.870 27.750 64.310 ;
        RECT 27.280 65.170 27.750 65.610 ;
        RECT 27.280 66.470 27.750 66.910 ;
        RECT 27.280 67.770 27.750 68.210 ;
        RECT 27.280 70.370 27.750 70.810 ;
        RECT 27.280 71.670 27.750 72.110 ;
        RECT 27.280 72.970 27.750 73.410 ;
        RECT 27.280 74.270 27.750 74.710 ;
        RECT 27.280 75.570 27.750 76.010 ;
        RECT 27.280 76.870 27.750 77.310 ;
        RECT 27.280 78.170 27.750 78.610 ;
        RECT 27.280 79.470 27.750 79.910 ;
        RECT 27.280 82.070 27.750 82.510 ;
        RECT 27.280 83.370 27.750 83.810 ;
        RECT 27.280 84.670 27.750 85.110 ;
        RECT 27.280 85.970 27.750 86.410 ;
        RECT 27.280 87.270 27.750 87.710 ;
        RECT 27.280 88.570 27.750 89.010 ;
        RECT 27.280 89.870 27.750 90.310 ;
        RECT 27.280 91.170 27.750 91.610 ;
        RECT 26.800 92.820 27.300 93.320 ;
        RECT 40.880 50.870 41.350 51.310 ;
        RECT 40.880 52.170 41.350 52.610 ;
        RECT 40.880 53.470 41.350 53.910 ;
        RECT 40.880 54.770 41.350 55.210 ;
        RECT 40.880 56.070 41.350 56.510 ;
        RECT 40.880 58.670 41.350 59.110 ;
        RECT 40.880 48.270 41.350 48.710 ;
        RECT 40.880 59.970 41.350 60.410 ;
        RECT 40.880 61.270 41.350 61.710 ;
        RECT 40.880 62.570 41.350 63.010 ;
        RECT 40.880 63.870 41.350 64.310 ;
        RECT 40.880 65.170 41.350 65.610 ;
        RECT 40.880 66.470 41.350 66.910 ;
        RECT 40.880 67.770 41.350 68.210 ;
        RECT 40.880 70.370 41.350 70.810 ;
        RECT 40.880 71.670 41.350 72.110 ;
        RECT 40.880 72.970 41.350 73.410 ;
        RECT 40.880 74.270 41.350 74.710 ;
        RECT 40.880 75.570 41.350 76.010 ;
        RECT 40.880 76.870 41.350 77.310 ;
        RECT 40.880 78.170 41.350 78.610 ;
        RECT 40.880 79.470 41.350 79.910 ;
        RECT 40.880 82.070 41.350 82.510 ;
        RECT 40.880 49.570 41.350 50.010 ;
        RECT 40.880 83.370 41.350 83.810 ;
        RECT 40.880 84.670 41.350 85.110 ;
        RECT 40.880 85.970 41.350 86.410 ;
        RECT 40.880 87.270 41.350 87.710 ;
        RECT 40.880 88.570 41.350 89.010 ;
        RECT 40.880 89.870 41.350 90.310 ;
        RECT 40.880 91.170 41.350 91.610 ;
        RECT 40.400 92.820 40.900 93.320 ;
        RECT 47.680 74.270 48.150 74.710 ;
        RECT 47.680 75.570 48.150 76.010 ;
        RECT 47.680 71.670 48.150 72.110 ;
        RECT 47.680 76.870 48.150 77.310 ;
        RECT 47.680 78.170 48.150 78.610 ;
        RECT 47.680 79.470 48.150 79.910 ;
        RECT 47.680 82.070 48.150 82.510 ;
        RECT 47.680 83.370 48.150 83.810 ;
        RECT 47.680 84.670 48.150 85.110 ;
        RECT 47.680 85.970 48.150 86.410 ;
        RECT 47.680 72.970 48.150 73.410 ;
        RECT 47.680 87.270 48.150 87.710 ;
        RECT 47.680 88.570 48.150 89.010 ;
        RECT 47.680 89.870 48.150 90.310 ;
        RECT 47.680 91.170 48.150 91.610 ;
        RECT 47.200 92.820 47.700 93.320 ;
        RECT 49.380 85.970 49.850 86.410 ;
        RECT 51.080 85.970 51.550 86.410 ;
        RECT 52.780 85.970 53.250 86.410 ;
        RECT 52.780 83.370 53.250 83.810 ;
        RECT 49.380 83.370 49.850 83.810 ;
        RECT 49.380 87.270 49.850 87.710 ;
        RECT 51.080 87.270 51.550 87.710 ;
        RECT 52.780 87.270 53.250 87.710 ;
        RECT 49.380 84.670 49.850 85.110 ;
        RECT 49.380 88.570 49.850 89.010 ;
        RECT 51.080 88.570 51.550 89.010 ;
        RECT 52.780 88.570 53.250 89.010 ;
        RECT 51.080 84.670 51.550 85.110 ;
        RECT 49.380 89.870 49.850 90.310 ;
        RECT 51.080 89.870 51.550 90.310 ;
        RECT 52.780 89.870 53.250 90.310 ;
        RECT 52.780 84.670 53.250 85.110 ;
        RECT 49.380 91.170 49.850 91.610 ;
        RECT 51.080 91.170 51.550 91.610 ;
        RECT 52.780 91.170 53.250 91.610 ;
        RECT 51.080 83.370 51.550 83.810 ;
        RECT 48.900 92.820 49.400 93.320 ;
        RECT 50.600 92.820 51.100 93.320 ;
        RECT 52.300 92.820 52.800 93.320 ;
        RECT 54.000 92.820 54.500 93.320 ;
        RECT 44.280 83.370 44.750 83.810 ;
        RECT 45.980 83.370 46.450 83.810 ;
        RECT 42.580 89.870 43.050 90.310 ;
        RECT 44.280 89.870 44.750 90.310 ;
        RECT 45.980 89.870 46.450 90.310 ;
        RECT 42.580 83.370 43.050 83.810 ;
        RECT 42.580 87.270 43.050 87.710 ;
        RECT 44.280 87.270 44.750 87.710 ;
        RECT 45.980 87.270 46.450 87.710 ;
        RECT 42.580 91.170 43.050 91.610 ;
        RECT 44.280 91.170 44.750 91.610 ;
        RECT 45.980 91.170 46.450 91.610 ;
        RECT 42.580 84.670 43.050 85.110 ;
        RECT 42.580 85.970 43.050 86.410 ;
        RECT 44.280 85.970 44.750 86.410 ;
        RECT 45.980 85.970 46.450 86.410 ;
        RECT 42.100 92.820 42.600 93.320 ;
        RECT 43.800 92.820 44.300 93.320 ;
        RECT 45.500 92.820 46.000 93.320 ;
        RECT 42.580 88.570 43.050 89.010 ;
        RECT 44.280 88.570 44.750 89.010 ;
        RECT 45.980 88.570 46.450 89.010 ;
        RECT 44.280 84.670 44.750 85.110 ;
        RECT 45.980 84.670 46.450 85.110 ;
        RECT 45.980 79.470 46.450 79.910 ;
        RECT 45.980 72.970 46.450 73.410 ;
        RECT 42.580 75.570 43.050 76.010 ;
        RECT 42.580 82.070 43.050 82.510 ;
        RECT 44.280 82.070 44.750 82.510 ;
        RECT 45.980 82.070 46.450 82.510 ;
        RECT 44.280 75.570 44.750 76.010 ;
        RECT 42.580 71.670 43.050 72.110 ;
        RECT 42.580 72.970 43.050 73.410 ;
        RECT 45.980 75.570 46.450 76.010 ;
        RECT 44.280 74.270 44.750 74.710 ;
        RECT 45.980 74.270 46.450 74.710 ;
        RECT 42.580 76.870 43.050 77.310 ;
        RECT 44.280 76.870 44.750 77.310 ;
        RECT 45.980 76.870 46.450 77.310 ;
        RECT 44.280 71.670 44.750 72.110 ;
        RECT 42.580 74.270 43.050 74.710 ;
        RECT 44.280 72.970 44.750 73.410 ;
        RECT 42.580 78.170 43.050 78.610 ;
        RECT 44.280 78.170 44.750 78.610 ;
        RECT 45.980 78.170 46.450 78.610 ;
        RECT 45.980 71.670 46.450 72.110 ;
        RECT 42.580 79.470 43.050 79.910 ;
        RECT 44.280 79.470 44.750 79.910 ;
        RECT 51.080 82.070 51.550 82.510 ;
        RECT 52.780 82.070 53.250 82.510 ;
        RECT 49.380 74.270 49.850 74.710 ;
        RECT 51.080 74.270 51.550 74.710 ;
        RECT 49.380 78.170 49.850 78.610 ;
        RECT 51.080 78.170 51.550 78.610 ;
        RECT 52.780 78.170 53.250 78.610 ;
        RECT 52.780 72.970 53.250 73.410 ;
        RECT 51.080 71.670 51.550 72.110 ;
        RECT 49.380 75.570 49.850 76.010 ;
        RECT 51.080 75.570 51.550 76.010 ;
        RECT 49.380 76.870 49.850 77.310 ;
        RECT 51.080 76.870 51.550 77.310 ;
        RECT 49.380 79.470 49.850 79.910 ;
        RECT 51.080 79.470 51.550 79.910 ;
        RECT 49.380 72.970 49.850 73.410 ;
        RECT 52.780 79.470 53.250 79.910 ;
        RECT 52.780 71.670 53.250 72.110 ;
        RECT 52.780 76.870 53.250 77.310 ;
        RECT 49.380 71.670 49.850 72.110 ;
        RECT 52.780 75.570 53.250 76.010 ;
        RECT 52.780 74.270 53.250 74.710 ;
        RECT 49.380 82.070 49.850 82.510 ;
        RECT 51.080 72.970 51.550 73.410 ;
        RECT 34.080 74.270 34.550 74.710 ;
        RECT 34.080 84.670 34.550 85.110 ;
        RECT 34.080 72.970 34.550 73.410 ;
        RECT 34.080 78.170 34.550 78.610 ;
        RECT 34.080 85.970 34.550 86.410 ;
        RECT 34.080 87.270 34.550 87.710 ;
        RECT 34.080 79.470 34.550 79.910 ;
        RECT 34.080 88.570 34.550 89.010 ;
        RECT 34.080 75.570 34.550 76.010 ;
        RECT 34.080 71.670 34.550 72.110 ;
        RECT 34.080 89.870 34.550 90.310 ;
        RECT 34.080 82.070 34.550 82.510 ;
        RECT 34.080 91.170 34.550 91.610 ;
        RECT 34.080 76.870 34.550 77.310 ;
        RECT 33.600 92.820 34.100 93.320 ;
        RECT 34.080 83.370 34.550 83.810 ;
        RECT 39.180 84.670 39.650 85.110 ;
        RECT 35.780 88.570 36.250 89.010 ;
        RECT 37.480 88.570 37.950 89.010 ;
        RECT 39.180 88.570 39.650 89.010 ;
        RECT 35.780 85.970 36.250 86.410 ;
        RECT 37.480 85.970 37.950 86.410 ;
        RECT 39.180 85.970 39.650 86.410 ;
        RECT 35.780 89.870 36.250 90.310 ;
        RECT 37.480 89.870 37.950 90.310 ;
        RECT 39.180 89.870 39.650 90.310 ;
        RECT 35.780 84.670 36.250 85.110 ;
        RECT 35.780 87.270 36.250 87.710 ;
        RECT 35.780 91.170 36.250 91.610 ;
        RECT 37.480 91.170 37.950 91.610 ;
        RECT 39.180 91.170 39.650 91.610 ;
        RECT 37.480 87.270 37.950 87.710 ;
        RECT 39.180 87.270 39.650 87.710 ;
        RECT 35.300 92.820 35.800 93.320 ;
        RECT 37.000 92.820 37.500 93.320 ;
        RECT 38.700 92.820 39.200 93.320 ;
        RECT 37.480 84.670 37.950 85.110 ;
        RECT 35.780 83.370 36.250 83.810 ;
        RECT 37.480 83.370 37.950 83.810 ;
        RECT 39.180 83.370 39.650 83.810 ;
        RECT 28.980 88.570 29.450 89.010 ;
        RECT 30.680 88.570 31.150 89.010 ;
        RECT 28.980 91.170 29.450 91.610 ;
        RECT 30.680 91.170 31.150 91.610 ;
        RECT 32.380 91.170 32.850 91.610 ;
        RECT 32.380 88.570 32.850 89.010 ;
        RECT 28.980 85.970 29.450 86.410 ;
        RECT 28.980 87.270 29.450 87.710 ;
        RECT 30.680 87.270 31.150 87.710 ;
        RECT 32.380 87.270 32.850 87.710 ;
        RECT 28.500 92.820 29.000 93.320 ;
        RECT 30.200 92.820 30.700 93.320 ;
        RECT 31.900 92.820 32.400 93.320 ;
        RECT 30.680 85.970 31.150 86.410 ;
        RECT 32.380 85.970 32.850 86.410 ;
        RECT 28.980 89.870 29.450 90.310 ;
        RECT 30.680 89.870 31.150 90.310 ;
        RECT 28.980 83.370 29.450 83.810 ;
        RECT 30.680 83.370 31.150 83.810 ;
        RECT 32.380 83.370 32.850 83.810 ;
        RECT 32.380 89.870 32.850 90.310 ;
        RECT 28.980 84.670 29.450 85.110 ;
        RECT 30.680 84.670 31.150 85.110 ;
        RECT 32.380 84.670 32.850 85.110 ;
        RECT 29.930 94.530 30.470 95.070 ;
        RECT 30.680 71.670 31.150 72.110 ;
        RECT 32.380 75.570 32.850 76.010 ;
        RECT 28.980 72.970 29.450 73.410 ;
        RECT 28.980 74.270 29.450 74.710 ;
        RECT 30.680 74.270 31.150 74.710 ;
        RECT 28.980 76.870 29.450 77.310 ;
        RECT 30.680 76.870 31.150 77.310 ;
        RECT 32.380 76.870 32.850 77.310 ;
        RECT 28.980 79.470 29.450 79.910 ;
        RECT 30.680 79.470 31.150 79.910 ;
        RECT 32.380 79.470 32.850 79.910 ;
        RECT 32.380 71.670 32.850 72.110 ;
        RECT 28.980 75.570 29.450 76.010 ;
        RECT 30.680 75.570 31.150 76.010 ;
        RECT 28.980 82.070 29.450 82.510 ;
        RECT 30.680 82.070 31.150 82.510 ;
        RECT 32.380 82.070 32.850 82.510 ;
        RECT 30.680 72.970 31.150 73.410 ;
        RECT 28.980 71.670 29.450 72.110 ;
        RECT 28.980 78.170 29.450 78.610 ;
        RECT 30.680 78.170 31.150 78.610 ;
        RECT 32.380 78.170 32.850 78.610 ;
        RECT 32.380 74.270 32.850 74.710 ;
        RECT 32.380 72.970 32.850 73.410 ;
        RECT 39.180 79.470 39.650 79.910 ;
        RECT 37.480 72.970 37.950 73.410 ;
        RECT 39.180 72.970 39.650 73.410 ;
        RECT 37.480 74.270 37.950 74.710 ;
        RECT 35.780 78.170 36.250 78.610 ;
        RECT 37.480 78.170 37.950 78.610 ;
        RECT 35.780 76.870 36.250 77.310 ;
        RECT 39.180 74.270 39.650 74.710 ;
        RECT 35.780 74.270 36.250 74.710 ;
        RECT 39.180 78.170 39.650 78.610 ;
        RECT 35.780 82.070 36.250 82.510 ;
        RECT 37.480 82.070 37.950 82.510 ;
        RECT 39.180 82.070 39.650 82.510 ;
        RECT 35.780 75.570 36.250 76.010 ;
        RECT 37.480 75.570 37.950 76.010 ;
        RECT 39.180 75.570 39.650 76.010 ;
        RECT 35.780 72.970 36.250 73.410 ;
        RECT 35.780 71.670 36.250 72.110 ;
        RECT 37.480 71.670 37.950 72.110 ;
        RECT 39.180 71.670 39.650 72.110 ;
        RECT 35.780 79.470 36.250 79.910 ;
        RECT 37.480 76.870 37.950 77.310 ;
        RECT 39.180 76.870 39.650 77.310 ;
        RECT 37.480 79.470 37.950 79.910 ;
        RECT 34.080 56.070 34.550 56.510 ;
        RECT 34.080 50.870 34.550 51.310 ;
        RECT 34.080 58.670 34.550 59.110 ;
        RECT 34.080 59.970 34.550 60.410 ;
        RECT 34.080 61.270 34.550 61.710 ;
        RECT 34.080 62.570 34.550 63.010 ;
        RECT 34.080 49.570 34.550 50.010 ;
        RECT 34.080 63.870 34.550 64.310 ;
        RECT 34.080 65.170 34.550 65.610 ;
        RECT 34.080 66.470 34.550 66.910 ;
        RECT 34.080 67.770 34.550 68.210 ;
        RECT 34.080 52.170 34.550 52.610 ;
        RECT 34.080 70.370 34.550 70.810 ;
        RECT 34.080 48.270 34.550 48.710 ;
        RECT 34.080 53.470 34.550 53.910 ;
        RECT 34.080 54.770 34.550 55.210 ;
        RECT 35.780 59.970 36.250 60.410 ;
        RECT 35.780 63.870 36.250 64.310 ;
        RECT 37.480 63.870 37.950 64.310 ;
        RECT 39.180 63.870 39.650 64.310 ;
        RECT 35.780 61.270 36.250 61.710 ;
        RECT 35.780 65.170 36.250 65.610 ;
        RECT 37.480 65.170 37.950 65.610 ;
        RECT 39.180 65.170 39.650 65.610 ;
        RECT 37.480 61.270 37.950 61.710 ;
        RECT 35.780 66.470 36.250 66.910 ;
        RECT 37.480 66.470 37.950 66.910 ;
        RECT 39.180 66.470 39.650 66.910 ;
        RECT 39.180 61.270 39.650 61.710 ;
        RECT 35.780 67.770 36.250 68.210 ;
        RECT 37.480 67.770 37.950 68.210 ;
        RECT 39.180 67.770 39.650 68.210 ;
        RECT 37.480 59.970 37.950 60.410 ;
        RECT 39.180 59.970 39.650 60.410 ;
        RECT 35.780 70.370 36.250 70.810 ;
        RECT 37.480 70.370 37.950 70.810 ;
        RECT 39.180 70.370 39.650 70.810 ;
        RECT 35.780 62.570 36.250 63.010 ;
        RECT 37.480 62.570 37.950 63.010 ;
        RECT 39.180 62.570 39.650 63.010 ;
        RECT 30.680 66.470 31.150 66.910 ;
        RECT 32.380 66.470 32.850 66.910 ;
        RECT 28.980 59.970 29.450 60.410 ;
        RECT 28.980 63.870 29.450 64.310 ;
        RECT 30.680 63.870 31.150 64.310 ;
        RECT 32.380 63.870 32.850 64.310 ;
        RECT 28.980 67.770 29.450 68.210 ;
        RECT 30.680 67.770 31.150 68.210 ;
        RECT 32.380 67.770 32.850 68.210 ;
        RECT 28.980 61.270 29.450 61.710 ;
        RECT 28.980 62.570 29.450 63.010 ;
        RECT 30.680 62.570 31.150 63.010 ;
        RECT 32.380 62.570 32.850 63.010 ;
        RECT 28.980 65.170 29.450 65.610 ;
        RECT 28.980 70.370 29.450 70.810 ;
        RECT 30.680 70.370 31.150 70.810 ;
        RECT 32.380 70.370 32.850 70.810 ;
        RECT 30.680 65.170 31.150 65.610 ;
        RECT 32.380 65.170 32.850 65.610 ;
        RECT 30.680 61.270 31.150 61.710 ;
        RECT 32.380 61.270 32.850 61.710 ;
        RECT 30.680 59.970 31.150 60.410 ;
        RECT 32.380 59.970 32.850 60.410 ;
        RECT 28.980 66.470 29.450 66.910 ;
        RECT 30.680 58.670 31.150 59.110 ;
        RECT 32.380 52.170 32.850 52.610 ;
        RECT 32.380 48.270 32.850 48.710 ;
        RECT 30.680 52.170 31.150 52.610 ;
        RECT 28.980 52.170 29.450 52.610 ;
        RECT 32.380 58.670 32.850 59.110 ;
        RECT 30.680 49.570 31.150 50.010 ;
        RECT 28.980 48.270 29.450 48.710 ;
        RECT 28.980 50.870 29.450 51.310 ;
        RECT 28.980 58.670 29.450 59.110 ;
        RECT 28.980 53.470 29.450 53.910 ;
        RECT 30.680 53.470 31.150 53.910 ;
        RECT 32.380 53.470 32.850 53.910 ;
        RECT 30.680 48.270 31.150 48.710 ;
        RECT 30.680 50.870 31.150 51.310 ;
        RECT 28.980 54.770 29.450 55.210 ;
        RECT 30.680 54.770 31.150 55.210 ;
        RECT 28.980 49.570 29.450 50.010 ;
        RECT 32.380 54.770 32.850 55.210 ;
        RECT 32.380 49.570 32.850 50.010 ;
        RECT 32.380 50.870 32.850 51.310 ;
        RECT 28.980 56.070 29.450 56.510 ;
        RECT 30.680 56.070 31.150 56.510 ;
        RECT 32.380 56.070 32.850 56.510 ;
        RECT 39.180 48.270 39.650 48.710 ;
        RECT 35.780 58.670 36.250 59.110 ;
        RECT 37.480 58.670 37.950 59.110 ;
        RECT 39.180 58.670 39.650 59.110 ;
        RECT 35.780 49.570 36.250 50.010 ;
        RECT 35.780 50.870 36.250 51.310 ;
        RECT 35.780 53.470 36.250 53.910 ;
        RECT 37.480 53.470 37.950 53.910 ;
        RECT 39.180 53.470 39.650 53.910 ;
        RECT 39.180 50.870 39.650 51.310 ;
        RECT 35.780 48.270 36.250 48.710 ;
        RECT 37.480 50.870 37.950 51.310 ;
        RECT 39.180 56.070 39.650 56.510 ;
        RECT 37.480 49.570 37.950 50.010 ;
        RECT 35.780 56.070 36.250 56.510 ;
        RECT 35.780 52.170 36.250 52.610 ;
        RECT 35.780 54.770 36.250 55.210 ;
        RECT 37.480 54.770 37.950 55.210 ;
        RECT 39.180 54.770 39.650 55.210 ;
        RECT 37.480 56.070 37.950 56.510 ;
        RECT 37.480 48.270 37.950 48.710 ;
        RECT 39.180 49.570 39.650 50.010 ;
        RECT 37.480 52.170 37.950 52.610 ;
        RECT 39.180 52.170 39.650 52.610 ;
        RECT 47.680 48.270 48.150 48.710 ;
        RECT 47.680 58.670 48.150 59.110 ;
        RECT 47.680 65.170 48.150 65.610 ;
        RECT 47.680 50.870 48.150 51.310 ;
        RECT 47.680 54.770 48.150 55.210 ;
        RECT 47.680 66.470 48.150 66.910 ;
        RECT 47.680 59.970 48.150 60.410 ;
        RECT 47.680 49.570 48.150 50.010 ;
        RECT 47.680 67.770 48.150 68.210 ;
        RECT 47.680 70.370 48.150 70.810 ;
        RECT 47.680 61.270 48.150 61.710 ;
        RECT 47.680 53.470 48.150 53.910 ;
        RECT 47.680 56.070 48.150 56.510 ;
        RECT 47.680 62.570 48.150 63.010 ;
        RECT 47.680 52.170 48.150 52.610 ;
        RECT 47.680 63.870 48.150 64.310 ;
        RECT 52.780 63.870 53.250 64.310 ;
        RECT 49.380 65.170 49.850 65.610 ;
        RECT 49.380 67.770 49.850 68.210 ;
        RECT 51.080 67.770 51.550 68.210 ;
        RECT 52.780 67.770 53.250 68.210 ;
        RECT 52.780 59.970 53.250 60.410 ;
        RECT 51.080 65.170 51.550 65.610 ;
        RECT 49.380 70.370 49.850 70.810 ;
        RECT 51.080 70.370 51.550 70.810 ;
        RECT 52.780 70.370 53.250 70.810 ;
        RECT 49.380 66.470 49.850 66.910 ;
        RECT 49.380 61.270 49.850 61.710 ;
        RECT 51.080 61.270 51.550 61.710 ;
        RECT 52.780 61.270 53.250 61.710 ;
        RECT 51.080 66.470 51.550 66.910 ;
        RECT 52.780 66.470 53.250 66.910 ;
        RECT 52.780 65.170 53.250 65.610 ;
        RECT 49.380 62.570 49.850 63.010 ;
        RECT 51.080 62.570 51.550 63.010 ;
        RECT 52.780 62.570 53.250 63.010 ;
        RECT 49.380 59.970 49.850 60.410 ;
        RECT 51.080 59.970 51.550 60.410 ;
        RECT 49.380 63.870 49.850 64.310 ;
        RECT 51.080 63.870 51.550 64.310 ;
        RECT 42.580 67.770 43.050 68.210 ;
        RECT 42.580 61.270 43.050 61.710 ;
        RECT 44.280 61.270 44.750 61.710 ;
        RECT 45.980 61.270 46.450 61.710 ;
        RECT 44.280 67.770 44.750 68.210 ;
        RECT 44.280 65.170 44.750 65.610 ;
        RECT 45.980 67.770 46.450 68.210 ;
        RECT 45.980 65.170 46.450 65.610 ;
        RECT 42.580 66.470 43.050 66.910 ;
        RECT 42.580 59.970 43.050 60.410 ;
        RECT 42.580 62.570 43.050 63.010 ;
        RECT 44.280 62.570 44.750 63.010 ;
        RECT 45.980 62.570 46.450 63.010 ;
        RECT 44.280 59.970 44.750 60.410 ;
        RECT 45.980 59.970 46.450 60.410 ;
        RECT 42.580 70.370 43.050 70.810 ;
        RECT 44.280 70.370 44.750 70.810 ;
        RECT 45.980 70.370 46.450 70.810 ;
        RECT 42.580 63.870 43.050 64.310 ;
        RECT 44.280 63.870 44.750 64.310 ;
        RECT 45.980 63.870 46.450 64.310 ;
        RECT 44.280 66.470 44.750 66.910 ;
        RECT 45.980 66.470 46.450 66.910 ;
        RECT 42.580 65.170 43.050 65.610 ;
        RECT 44.280 48.270 44.750 48.710 ;
        RECT 45.980 53.470 46.450 53.910 ;
        RECT 42.580 54.770 43.050 55.210 ;
        RECT 42.580 56.070 43.050 56.510 ;
        RECT 44.280 56.070 44.750 56.510 ;
        RECT 45.980 56.070 46.450 56.510 ;
        RECT 44.280 54.770 44.750 55.210 ;
        RECT 45.980 54.770 46.450 55.210 ;
        RECT 44.280 49.570 44.750 50.010 ;
        RECT 42.580 58.670 43.050 59.110 ;
        RECT 44.280 58.670 44.750 59.110 ;
        RECT 45.980 58.670 46.450 59.110 ;
        RECT 42.580 53.470 43.050 53.910 ;
        RECT 44.280 53.470 44.750 53.910 ;
        RECT 45.980 48.270 46.450 48.710 ;
        RECT 45.980 52.170 46.450 52.610 ;
        RECT 45.980 49.570 46.450 50.010 ;
        RECT 45.980 50.870 46.450 51.310 ;
        RECT 42.580 48.270 43.050 48.710 ;
        RECT 42.580 50.870 43.050 51.310 ;
        RECT 44.280 50.870 44.750 51.310 ;
        RECT 42.580 52.170 43.050 52.610 ;
        RECT 42.580 49.570 43.050 50.010 ;
        RECT 44.280 52.170 44.750 52.610 ;
        RECT 51.080 58.670 51.550 59.110 ;
        RECT 51.080 48.270 51.550 48.710 ;
        RECT 49.380 54.770 49.850 55.210 ;
        RECT 51.080 54.770 51.550 55.210 ;
        RECT 49.380 50.870 49.850 51.310 ;
        RECT 49.380 49.570 49.850 50.010 ;
        RECT 52.780 49.570 53.250 50.010 ;
        RECT 51.080 50.870 51.550 51.310 ;
        RECT 51.080 49.570 51.550 50.010 ;
        RECT 52.780 56.070 53.250 56.510 ;
        RECT 49.380 53.470 49.850 53.910 ;
        RECT 51.080 53.470 51.550 53.910 ;
        RECT 52.780 53.470 53.250 53.910 ;
        RECT 52.780 52.170 53.250 52.610 ;
        RECT 49.380 58.670 49.850 59.110 ;
        RECT 49.380 52.170 49.850 52.610 ;
        RECT 51.080 52.170 51.550 52.610 ;
        RECT 52.780 48.270 53.250 48.710 ;
        RECT 49.380 48.270 49.850 48.710 ;
        RECT 52.780 58.670 53.250 59.110 ;
        RECT 52.780 54.770 53.250 55.210 ;
        RECT 52.780 50.870 53.250 51.310 ;
        RECT 49.380 56.070 49.850 56.510 ;
        RECT 51.080 56.070 51.550 56.510 ;
        RECT 13.680 71.670 14.150 72.110 ;
        RECT 13.680 59.970 14.150 60.410 ;
        RECT 13.680 72.970 14.150 73.410 ;
        RECT 13.680 53.470 14.150 53.910 ;
        RECT 13.680 74.270 14.150 74.710 ;
        RECT 13.680 61.270 14.150 61.710 ;
        RECT 13.680 75.570 14.150 76.010 ;
        RECT 13.680 50.870 14.150 51.310 ;
        RECT 13.680 76.870 14.150 77.310 ;
        RECT 13.680 62.570 14.150 63.010 ;
        RECT 13.680 78.170 14.150 78.610 ;
        RECT 13.680 54.770 14.150 55.210 ;
        RECT 13.680 79.470 14.150 79.910 ;
        RECT 13.680 63.870 14.150 64.310 ;
        RECT 13.680 82.070 14.150 82.510 ;
        RECT 13.680 49.570 14.150 50.010 ;
        RECT 13.680 83.370 14.150 83.810 ;
        RECT 13.680 65.170 14.150 65.610 ;
        RECT 13.680 84.670 14.150 85.110 ;
        RECT 13.680 56.070 14.150 56.510 ;
        RECT 13.680 85.970 14.150 86.410 ;
        RECT 13.680 66.470 14.150 66.910 ;
        RECT 13.680 87.270 14.150 87.710 ;
        RECT 13.680 52.170 14.150 52.610 ;
        RECT 13.680 88.570 14.150 89.010 ;
        RECT 13.680 67.770 14.150 68.210 ;
        RECT 13.680 89.870 14.150 90.310 ;
        RECT 13.680 58.670 14.150 59.110 ;
        RECT 13.680 91.170 14.150 91.610 ;
        RECT 13.680 70.370 14.150 70.810 ;
        RECT 13.200 92.820 13.700 93.320 ;
        RECT 13.680 48.270 14.150 48.710 ;
        RECT 20.480 76.870 20.950 77.310 ;
        RECT 20.480 78.170 20.950 78.610 ;
        RECT 20.480 79.470 20.950 79.910 ;
        RECT 20.480 72.970 20.950 73.410 ;
        RECT 20.480 82.070 20.950 82.510 ;
        RECT 20.480 83.370 20.950 83.810 ;
        RECT 20.480 71.670 20.950 72.110 ;
        RECT 20.480 84.670 20.950 85.110 ;
        RECT 20.480 85.970 20.950 86.410 ;
        RECT 20.480 74.270 20.950 74.710 ;
        RECT 20.480 87.270 20.950 87.710 ;
        RECT 20.480 88.570 20.950 89.010 ;
        RECT 20.480 89.870 20.950 90.310 ;
        RECT 20.480 91.170 20.950 91.610 ;
        RECT 20.000 92.820 20.500 93.320 ;
        RECT 20.480 75.570 20.950 76.010 ;
        RECT 23.880 85.970 24.350 86.410 ;
        RECT 25.580 85.970 26.050 86.410 ;
        RECT 22.180 83.370 22.650 83.810 ;
        RECT 23.880 83.370 24.350 83.810 ;
        RECT 22.180 87.270 22.650 87.710 ;
        RECT 23.880 87.270 24.350 87.710 ;
        RECT 25.580 87.270 26.050 87.710 ;
        RECT 22.180 84.670 22.650 85.110 ;
        RECT 22.180 88.570 22.650 89.010 ;
        RECT 23.880 88.570 24.350 89.010 ;
        RECT 25.580 88.570 26.050 89.010 ;
        RECT 23.880 84.670 24.350 85.110 ;
        RECT 22.180 89.870 22.650 90.310 ;
        RECT 23.880 89.870 24.350 90.310 ;
        RECT 25.580 89.870 26.050 90.310 ;
        RECT 25.580 84.670 26.050 85.110 ;
        RECT 22.180 91.170 22.650 91.610 ;
        RECT 23.880 91.170 24.350 91.610 ;
        RECT 25.580 91.170 26.050 91.610 ;
        RECT 25.580 83.370 26.050 83.810 ;
        RECT 21.700 92.820 22.200 93.320 ;
        RECT 23.400 92.820 23.900 93.320 ;
        RECT 25.100 92.820 25.600 93.320 ;
        RECT 22.180 85.970 22.650 86.410 ;
        RECT 18.780 83.370 19.250 83.810 ;
        RECT 15.380 83.370 15.850 83.810 ;
        RECT 15.380 89.870 15.850 90.310 ;
        RECT 17.080 89.870 17.550 90.310 ;
        RECT 18.780 89.870 19.250 90.310 ;
        RECT 17.080 83.370 17.550 83.810 ;
        RECT 15.380 87.270 15.850 87.710 ;
        RECT 17.080 87.270 17.550 87.710 ;
        RECT 18.780 87.270 19.250 87.710 ;
        RECT 15.380 91.170 15.850 91.610 ;
        RECT 17.080 91.170 17.550 91.610 ;
        RECT 18.780 91.170 19.250 91.610 ;
        RECT 15.380 84.670 15.850 85.110 ;
        RECT 15.380 85.970 15.850 86.410 ;
        RECT 17.080 85.970 17.550 86.410 ;
        RECT 18.780 85.970 19.250 86.410 ;
        RECT 14.900 92.820 15.400 93.320 ;
        RECT 16.600 92.820 17.100 93.320 ;
        RECT 18.300 92.820 18.800 93.320 ;
        RECT 15.380 88.570 15.850 89.010 ;
        RECT 17.080 88.570 17.550 89.010 ;
        RECT 18.780 88.570 19.250 89.010 ;
        RECT 17.080 84.670 17.550 85.110 ;
        RECT 18.780 84.670 19.250 85.110 ;
        RECT 15.380 72.970 15.850 73.410 ;
        RECT 15.380 78.170 15.850 78.610 ;
        RECT 17.080 78.170 17.550 78.610 ;
        RECT 18.780 78.170 19.250 78.610 ;
        RECT 18.780 74.270 19.250 74.710 ;
        RECT 15.380 76.870 15.850 77.310 ;
        RECT 15.380 75.570 15.850 76.010 ;
        RECT 17.080 72.970 17.550 73.410 ;
        RECT 18.780 71.670 19.250 72.110 ;
        RECT 18.780 72.970 19.250 73.410 ;
        RECT 15.380 79.470 15.850 79.910 ;
        RECT 17.080 79.470 17.550 79.910 ;
        RECT 18.780 79.470 19.250 79.910 ;
        RECT 17.080 76.870 17.550 77.310 ;
        RECT 17.080 75.570 17.550 76.010 ;
        RECT 18.780 75.570 19.250 76.010 ;
        RECT 18.780 76.870 19.250 77.310 ;
        RECT 15.380 82.070 15.850 82.510 ;
        RECT 17.080 82.070 17.550 82.510 ;
        RECT 15.380 74.270 15.850 74.710 ;
        RECT 17.080 74.270 17.550 74.710 ;
        RECT 18.780 82.070 19.250 82.510 ;
        RECT 15.380 71.670 15.850 72.110 ;
        RECT 17.080 71.670 17.550 72.110 ;
        RECT 22.180 79.470 22.650 79.910 ;
        RECT 23.880 79.470 24.350 79.910 ;
        RECT 25.580 79.470 26.050 79.910 ;
        RECT 23.880 76.870 24.350 77.310 ;
        RECT 22.180 72.970 22.650 73.410 ;
        RECT 23.880 71.670 24.350 72.110 ;
        RECT 22.180 78.170 22.650 78.610 ;
        RECT 23.880 78.170 24.350 78.610 ;
        RECT 25.580 78.170 26.050 78.610 ;
        RECT 25.580 76.870 26.050 77.310 ;
        RECT 22.180 82.070 22.650 82.510 ;
        RECT 22.180 74.270 22.650 74.710 ;
        RECT 23.880 74.270 24.350 74.710 ;
        RECT 23.880 82.070 24.350 82.510 ;
        RECT 25.580 82.070 26.050 82.510 ;
        RECT 23.880 72.970 24.350 73.410 ;
        RECT 25.580 72.970 26.050 73.410 ;
        RECT 23.880 75.570 24.350 76.010 ;
        RECT 25.580 75.570 26.050 76.010 ;
        RECT 25.580 71.670 26.050 72.110 ;
        RECT 25.580 74.270 26.050 74.710 ;
        RECT 22.180 71.670 22.650 72.110 ;
        RECT 22.180 75.570 22.650 76.010 ;
        RECT 22.180 76.870 22.650 77.310 ;
        RECT 6.880 74.270 7.350 74.710 ;
        RECT 6.880 72.970 7.350 73.410 ;
        RECT 6.880 84.670 7.350 85.110 ;
        RECT 6.880 78.170 7.350 78.610 ;
        RECT 6.880 85.970 7.350 86.410 ;
        RECT 6.880 87.270 7.350 87.710 ;
        RECT 6.880 75.570 7.350 76.010 ;
        RECT 6.880 79.470 7.350 79.910 ;
        RECT 6.880 88.570 7.350 89.010 ;
        RECT 6.880 71.670 7.350 72.110 ;
        RECT 6.880 89.870 7.350 90.310 ;
        RECT 6.880 82.070 7.350 82.510 ;
        RECT 6.880 91.170 7.350 91.610 ;
        RECT 6.880 76.870 7.350 77.310 ;
        RECT 6.400 92.820 6.900 93.320 ;
        RECT 6.880 83.370 7.350 83.810 ;
        RECT 10.280 84.670 10.750 85.110 ;
        RECT 8.580 85.970 9.050 86.410 ;
        RECT 8.580 88.570 9.050 89.010 ;
        RECT 10.280 88.570 10.750 89.010 ;
        RECT 11.980 88.570 12.450 89.010 ;
        RECT 10.280 85.970 10.750 86.410 ;
        RECT 11.980 85.970 12.450 86.410 ;
        RECT 8.580 89.870 9.050 90.310 ;
        RECT 10.280 89.870 10.750 90.310 ;
        RECT 11.980 89.870 12.450 90.310 ;
        RECT 11.980 84.670 12.450 85.110 ;
        RECT 8.580 87.270 9.050 87.710 ;
        RECT 8.580 91.170 9.050 91.610 ;
        RECT 10.280 91.170 10.750 91.610 ;
        RECT 11.980 91.170 12.450 91.610 ;
        RECT 10.280 87.270 10.750 87.710 ;
        RECT 11.980 87.270 12.450 87.710 ;
        RECT 8.100 92.820 8.600 93.320 ;
        RECT 9.800 92.820 10.300 93.320 ;
        RECT 11.500 92.820 12.000 93.320 ;
        RECT 8.580 84.670 9.050 85.110 ;
        RECT 8.580 83.370 9.050 83.810 ;
        RECT 10.280 83.370 10.750 83.810 ;
        RECT 11.980 83.370 12.450 83.810 ;
        RECT 7.930 93.680 8.470 94.220 ;
        RECT 5.180 89.870 5.650 90.310 ;
        RECT 5.180 87.270 5.650 87.710 ;
        RECT 0.080 85.970 0.550 86.410 ;
        RECT 1.780 85.970 2.250 86.410 ;
        RECT 3.480 85.970 3.950 86.410 ;
        RECT 5.180 85.970 5.650 86.410 ;
        RECT 0.080 91.170 0.550 91.610 ;
        RECT 1.780 91.170 2.250 91.610 ;
        RECT 3.480 91.170 3.950 91.610 ;
        RECT 5.180 91.170 5.650 91.610 ;
        RECT 1.780 84.670 2.250 85.110 ;
        RECT 3.480 84.670 3.950 85.110 ;
        RECT 0.080 88.570 0.550 89.010 ;
        RECT 1.780 88.570 2.250 89.010 ;
        RECT 3.480 88.570 3.950 89.010 ;
        RECT 0.080 83.370 0.550 83.810 ;
        RECT 1.300 92.820 1.800 93.320 ;
        RECT 3.000 92.820 3.500 93.320 ;
        RECT 4.700 92.820 5.200 93.320 ;
        RECT 5.180 88.570 5.650 89.010 ;
        RECT 5.180 84.670 5.650 85.110 ;
        RECT 0.080 84.670 0.550 85.110 ;
        RECT 0.080 87.270 0.550 87.710 ;
        RECT 1.780 83.370 2.250 83.810 ;
        RECT 3.480 83.370 3.950 83.810 ;
        RECT 5.180 83.370 5.650 83.810 ;
        RECT 1.780 87.270 2.250 87.710 ;
        RECT 3.480 87.270 3.950 87.710 ;
        RECT 0.080 89.870 0.550 90.310 ;
        RECT 1.780 89.870 2.250 90.310 ;
        RECT 3.480 89.870 3.950 90.310 ;
        RECT 3.480 71.670 3.950 72.110 ;
        RECT 0.080 75.570 0.550 76.010 ;
        RECT 1.780 75.570 2.250 76.010 ;
        RECT 5.180 71.670 5.650 72.110 ;
        RECT 3.480 75.570 3.950 76.010 ;
        RECT 0.080 72.970 0.550 73.410 ;
        RECT 1.780 72.970 2.250 73.410 ;
        RECT 3.480 74.270 3.950 74.710 ;
        RECT 5.180 74.270 5.650 74.710 ;
        RECT 0.080 76.870 0.550 77.310 ;
        RECT 1.780 76.870 2.250 77.310 ;
        RECT 3.480 76.870 3.950 77.310 ;
        RECT 5.180 76.870 5.650 77.310 ;
        RECT 3.480 72.970 3.950 73.410 ;
        RECT 0.080 74.270 0.550 74.710 ;
        RECT 0.080 79.470 0.550 79.910 ;
        RECT 1.780 79.470 2.250 79.910 ;
        RECT 3.480 79.470 3.950 79.910 ;
        RECT 5.180 79.470 5.650 79.910 ;
        RECT 5.180 75.570 5.650 76.010 ;
        RECT 5.180 78.170 5.650 78.610 ;
        RECT 5.180 72.970 5.650 73.410 ;
        RECT 0.080 78.170 0.550 78.610 ;
        RECT 0.080 82.070 0.550 82.510 ;
        RECT 1.780 82.070 2.250 82.510 ;
        RECT 3.480 82.070 3.950 82.510 ;
        RECT 5.180 82.070 5.650 82.510 ;
        RECT 1.780 78.170 2.250 78.610 ;
        RECT 1.780 74.270 2.250 74.710 ;
        RECT 0.080 71.670 0.550 72.110 ;
        RECT 3.480 78.170 3.950 78.610 ;
        RECT 1.780 71.670 2.250 72.110 ;
        RECT 8.580 74.270 9.050 74.710 ;
        RECT 8.580 75.570 9.050 76.010 ;
        RECT 10.280 75.570 10.750 76.010 ;
        RECT 8.580 76.870 9.050 77.310 ;
        RECT 11.980 75.570 12.450 76.010 ;
        RECT 10.280 74.270 10.750 74.710 ;
        RECT 8.580 82.070 9.050 82.510 ;
        RECT 10.280 82.070 10.750 82.510 ;
        RECT 11.980 82.070 12.450 82.510 ;
        RECT 8.580 72.970 9.050 73.410 ;
        RECT 10.280 72.970 10.750 73.410 ;
        RECT 8.580 78.170 9.050 78.610 ;
        RECT 8.580 79.470 9.050 79.910 ;
        RECT 10.280 79.470 10.750 79.910 ;
        RECT 11.980 79.470 12.450 79.910 ;
        RECT 10.280 78.170 10.750 78.610 ;
        RECT 11.980 78.170 12.450 78.610 ;
        RECT 8.580 71.670 9.050 72.110 ;
        RECT 10.280 71.670 10.750 72.110 ;
        RECT 10.280 76.870 10.750 77.310 ;
        RECT 11.980 76.870 12.450 77.310 ;
        RECT 11.980 71.670 12.450 72.110 ;
        RECT 11.980 72.970 12.450 73.410 ;
        RECT 11.980 74.270 12.450 74.710 ;
        RECT 6.880 49.570 7.350 50.010 ;
        RECT 6.880 50.870 7.350 51.310 ;
        RECT 6.880 52.170 7.350 52.610 ;
        RECT 6.880 54.770 7.350 55.210 ;
        RECT 6.880 61.270 7.350 61.710 ;
        RECT 6.880 67.770 7.350 68.210 ;
        RECT 6.880 65.170 7.350 65.610 ;
        RECT 6.880 59.970 7.350 60.410 ;
        RECT 6.880 58.670 7.350 59.110 ;
        RECT 6.880 56.070 7.350 56.510 ;
        RECT 6.880 63.870 7.350 64.310 ;
        RECT 6.880 70.370 7.350 70.810 ;
        RECT 6.880 62.570 7.350 63.010 ;
        RECT 6.880 53.470 7.350 53.910 ;
        RECT 6.880 48.270 7.350 48.710 ;
        RECT 6.880 66.470 7.350 66.910 ;
        RECT 8.580 67.770 9.050 68.210 ;
        RECT 8.580 59.970 9.050 60.410 ;
        RECT 10.280 59.970 10.750 60.410 ;
        RECT 11.980 59.970 12.450 60.410 ;
        RECT 10.280 67.770 10.750 68.210 ;
        RECT 11.980 67.770 12.450 68.210 ;
        RECT 8.580 61.270 9.050 61.710 ;
        RECT 8.580 63.870 9.050 64.310 ;
        RECT 10.280 63.870 10.750 64.310 ;
        RECT 11.980 63.870 12.450 64.310 ;
        RECT 8.580 65.170 9.050 65.610 ;
        RECT 8.580 70.370 9.050 70.810 ;
        RECT 10.280 70.370 10.750 70.810 ;
        RECT 11.980 70.370 12.450 70.810 ;
        RECT 10.280 65.170 10.750 65.610 ;
        RECT 8.580 62.570 9.050 63.010 ;
        RECT 10.280 62.570 10.750 63.010 ;
        RECT 11.980 62.570 12.450 63.010 ;
        RECT 11.980 65.170 12.450 65.610 ;
        RECT 10.280 61.270 10.750 61.710 ;
        RECT 11.980 61.270 12.450 61.710 ;
        RECT 8.580 66.470 9.050 66.910 ;
        RECT 10.280 66.470 10.750 66.910 ;
        RECT 11.980 66.470 12.450 66.910 ;
        RECT 3.480 63.870 3.950 64.310 ;
        RECT 3.480 61.270 3.950 61.710 ;
        RECT 5.180 63.870 5.650 64.310 ;
        RECT 0.080 65.170 0.550 65.610 ;
        RECT 1.780 65.170 2.250 65.610 ;
        RECT 3.480 65.170 3.950 65.610 ;
        RECT 5.180 65.170 5.650 65.610 ;
        RECT 0.080 70.370 0.550 70.810 ;
        RECT 1.780 70.370 2.250 70.810 ;
        RECT 3.480 70.370 3.950 70.810 ;
        RECT 5.180 70.370 5.650 70.810 ;
        RECT 0.080 67.770 0.550 68.210 ;
        RECT 1.780 67.770 2.250 68.210 ;
        RECT 3.480 59.970 3.950 60.410 ;
        RECT 5.180 59.970 5.650 60.410 ;
        RECT 3.480 62.570 3.950 63.010 ;
        RECT 5.180 62.570 5.650 63.010 ;
        RECT 3.480 67.770 3.950 68.210 ;
        RECT 5.180 67.770 5.650 68.210 ;
        RECT 0.080 61.270 0.550 61.710 ;
        RECT 5.180 61.270 5.650 61.710 ;
        RECT 0.080 59.970 0.550 60.410 ;
        RECT 1.780 59.970 2.250 60.410 ;
        RECT 0.080 66.470 0.550 66.910 ;
        RECT 1.780 66.470 2.250 66.910 ;
        RECT 3.480 66.470 3.950 66.910 ;
        RECT 5.180 66.470 5.650 66.910 ;
        RECT 0.080 62.570 0.550 63.010 ;
        RECT 1.780 61.270 2.250 61.710 ;
        RECT 1.780 62.570 2.250 63.010 ;
        RECT 0.080 63.870 0.550 64.310 ;
        RECT 1.780 63.870 2.250 64.310 ;
        RECT 3.480 52.170 3.950 52.610 ;
        RECT 5.180 52.170 5.650 52.610 ;
        RECT 3.480 50.870 3.950 51.310 ;
        RECT 5.180 50.870 5.650 51.310 ;
        RECT 0.080 49.570 0.550 50.010 ;
        RECT 0.080 54.770 0.550 55.210 ;
        RECT 0.080 53.470 0.550 53.910 ;
        RECT 1.780 53.470 2.250 53.910 ;
        RECT 3.480 53.470 3.950 53.910 ;
        RECT 1.780 54.770 2.250 55.210 ;
        RECT 0.080 58.670 0.550 59.110 ;
        RECT 1.780 58.670 2.250 59.110 ;
        RECT 3.480 58.670 3.950 59.110 ;
        RECT 5.180 58.670 5.650 59.110 ;
        RECT 3.480 54.770 3.950 55.210 ;
        RECT 5.180 54.770 5.650 55.210 ;
        RECT 5.180 53.470 5.650 53.910 ;
        RECT 1.780 49.570 2.250 50.010 ;
        RECT 3.480 49.570 3.950 50.010 ;
        RECT 5.180 49.570 5.650 50.010 ;
        RECT 0.080 56.070 0.550 56.510 ;
        RECT 1.780 56.070 2.250 56.510 ;
        RECT 3.480 56.070 3.950 56.510 ;
        RECT 0.080 48.270 0.550 48.710 ;
        RECT 1.780 48.270 2.250 48.710 ;
        RECT 3.480 48.270 3.950 48.710 ;
        RECT 5.180 48.270 5.650 48.710 ;
        RECT 5.180 56.070 5.650 56.510 ;
        RECT 0.080 50.870 0.550 51.310 ;
        RECT 1.780 50.870 2.250 51.310 ;
        RECT 0.080 52.170 0.550 52.610 ;
        RECT 1.780 52.170 2.250 52.610 ;
        RECT 11.980 56.070 12.450 56.510 ;
        RECT 10.280 54.770 10.750 55.210 ;
        RECT 11.980 54.770 12.450 55.210 ;
        RECT 10.280 52.170 10.750 52.610 ;
        RECT 8.580 53.470 9.050 53.910 ;
        RECT 10.280 53.470 10.750 53.910 ;
        RECT 11.980 53.470 12.450 53.910 ;
        RECT 8.580 58.670 9.050 59.110 ;
        RECT 10.280 58.670 10.750 59.110 ;
        RECT 11.980 58.670 12.450 59.110 ;
        RECT 11.980 52.170 12.450 52.610 ;
        RECT 11.980 50.870 12.450 51.310 ;
        RECT 10.280 49.570 10.750 50.010 ;
        RECT 11.980 49.570 12.450 50.010 ;
        RECT 8.580 49.570 9.050 50.010 ;
        RECT 8.580 50.870 9.050 51.310 ;
        RECT 10.280 50.870 10.750 51.310 ;
        RECT 8.580 48.270 9.050 48.710 ;
        RECT 10.280 48.270 10.750 48.710 ;
        RECT 11.980 48.270 12.450 48.710 ;
        RECT 8.580 52.170 9.050 52.610 ;
        RECT 8.580 54.770 9.050 55.210 ;
        RECT 8.580 56.070 9.050 56.510 ;
        RECT 10.280 56.070 10.750 56.510 ;
        RECT 20.480 49.570 20.950 50.010 ;
        RECT 20.480 67.770 20.950 68.210 ;
        RECT 20.480 59.970 20.950 60.410 ;
        RECT 20.480 53.470 20.950 53.910 ;
        RECT 20.480 66.470 20.950 66.910 ;
        RECT 20.480 58.670 20.950 59.110 ;
        RECT 20.480 63.870 20.950 64.310 ;
        RECT 20.480 65.170 20.950 65.610 ;
        RECT 20.480 61.270 20.950 61.710 ;
        RECT 20.480 70.370 20.950 70.810 ;
        RECT 20.480 52.170 20.950 52.610 ;
        RECT 20.480 54.770 20.950 55.210 ;
        RECT 20.480 50.870 20.950 51.310 ;
        RECT 20.480 62.570 20.950 63.010 ;
        RECT 20.480 48.270 20.950 48.710 ;
        RECT 20.480 56.070 20.950 56.510 ;
        RECT 25.580 62.570 26.050 63.010 ;
        RECT 22.180 63.870 22.650 64.310 ;
        RECT 23.880 63.870 24.350 64.310 ;
        RECT 25.580 63.870 26.050 64.310 ;
        RECT 23.880 59.970 24.350 60.410 ;
        RECT 22.180 65.170 22.650 65.610 ;
        RECT 23.880 65.170 24.350 65.610 ;
        RECT 25.580 65.170 26.050 65.610 ;
        RECT 25.580 59.970 26.050 60.410 ;
        RECT 22.180 61.270 22.650 61.710 ;
        RECT 23.880 61.270 24.350 61.710 ;
        RECT 25.580 61.270 26.050 61.710 ;
        RECT 22.180 59.970 22.650 60.410 ;
        RECT 22.180 67.770 22.650 68.210 ;
        RECT 22.180 70.370 22.650 70.810 ;
        RECT 23.880 70.370 24.350 70.810 ;
        RECT 25.580 70.370 26.050 70.810 ;
        RECT 23.880 67.770 24.350 68.210 ;
        RECT 25.580 67.770 26.050 68.210 ;
        RECT 22.180 66.470 22.650 66.910 ;
        RECT 23.880 62.570 24.350 63.010 ;
        RECT 22.180 62.570 22.650 63.010 ;
        RECT 23.880 66.470 24.350 66.910 ;
        RECT 25.580 66.470 26.050 66.910 ;
        RECT 17.080 66.470 17.550 66.910 ;
        RECT 18.780 66.470 19.250 66.910 ;
        RECT 17.080 67.770 17.550 68.210 ;
        RECT 15.380 59.970 15.850 60.410 ;
        RECT 17.080 59.970 17.550 60.410 ;
        RECT 18.780 59.970 19.250 60.410 ;
        RECT 18.780 67.770 19.250 68.210 ;
        RECT 15.380 70.370 15.850 70.810 ;
        RECT 17.080 70.370 17.550 70.810 ;
        RECT 18.780 70.370 19.250 70.810 ;
        RECT 18.780 63.870 19.250 64.310 ;
        RECT 15.380 67.770 15.850 68.210 ;
        RECT 15.380 61.270 15.850 61.710 ;
        RECT 17.080 61.270 17.550 61.710 ;
        RECT 15.380 63.870 15.850 64.310 ;
        RECT 18.780 61.270 19.250 61.710 ;
        RECT 15.380 65.170 15.850 65.610 ;
        RECT 15.380 62.570 15.850 63.010 ;
        RECT 17.080 62.570 17.550 63.010 ;
        RECT 18.780 62.570 19.250 63.010 ;
        RECT 17.080 65.170 17.550 65.610 ;
        RECT 18.780 65.170 19.250 65.610 ;
        RECT 17.080 63.870 17.550 64.310 ;
        RECT 15.380 66.470 15.850 66.910 ;
        RECT 17.080 54.770 17.550 55.210 ;
        RECT 18.780 54.770 19.250 55.210 ;
        RECT 15.380 52.170 15.850 52.610 ;
        RECT 17.080 52.170 17.550 52.610 ;
        RECT 18.780 52.170 19.250 52.610 ;
        RECT 18.780 53.470 19.250 53.910 ;
        RECT 15.380 50.870 15.850 51.310 ;
        RECT 17.080 50.870 17.550 51.310 ;
        RECT 18.780 50.870 19.250 51.310 ;
        RECT 15.380 54.770 15.850 55.210 ;
        RECT 15.380 58.670 15.850 59.110 ;
        RECT 17.080 58.670 17.550 59.110 ;
        RECT 18.780 58.670 19.250 59.110 ;
        RECT 17.080 49.570 17.550 50.010 ;
        RECT 18.780 49.570 19.250 50.010 ;
        RECT 15.380 49.570 15.850 50.010 ;
        RECT 15.380 56.070 15.850 56.510 ;
        RECT 17.080 56.070 17.550 56.510 ;
        RECT 15.380 48.270 15.850 48.710 ;
        RECT 17.080 48.270 17.550 48.710 ;
        RECT 18.780 48.270 19.250 48.710 ;
        RECT 15.380 53.470 15.850 53.910 ;
        RECT 18.780 56.070 19.250 56.510 ;
        RECT 17.080 53.470 17.550 53.910 ;
        RECT 22.180 54.770 22.650 55.210 ;
        RECT 23.880 54.770 24.350 55.210 ;
        RECT 25.580 54.770 26.050 55.210 ;
        RECT 25.580 50.870 26.050 51.310 ;
        RECT 23.880 56.070 24.350 56.510 ;
        RECT 22.180 49.570 22.650 50.010 ;
        RECT 25.580 49.570 26.050 50.010 ;
        RECT 23.880 49.570 24.350 50.010 ;
        RECT 25.580 56.070 26.050 56.510 ;
        RECT 22.180 50.870 22.650 51.310 ;
        RECT 23.880 50.870 24.350 51.310 ;
        RECT 22.180 53.470 22.650 53.910 ;
        RECT 23.880 53.470 24.350 53.910 ;
        RECT 25.580 53.470 26.050 53.910 ;
        RECT 22.180 58.670 22.650 59.110 ;
        RECT 23.880 58.670 24.350 59.110 ;
        RECT 22.180 52.170 22.650 52.610 ;
        RECT 23.880 52.170 24.350 52.610 ;
        RECT 22.180 48.270 22.650 48.710 ;
        RECT 23.880 48.270 24.350 48.710 ;
        RECT 25.580 48.270 26.050 48.710 ;
        RECT 25.580 52.170 26.050 52.610 ;
        RECT 25.580 58.670 26.050 59.110 ;
        RECT 22.180 56.070 22.650 56.510 ;
        RECT 13.680 44.370 14.150 44.810 ;
        RECT 13.680 46.970 14.150 47.410 ;
        RECT 13.680 2.770 14.150 3.210 ;
        RECT 13.680 4.070 14.150 4.510 ;
        RECT 13.680 5.370 14.150 5.810 ;
        RECT 13.680 6.670 14.150 7.110 ;
        RECT 13.680 7.970 14.150 8.410 ;
        RECT 13.680 9.270 14.150 9.710 ;
        RECT 13.680 11.870 14.150 12.310 ;
        RECT 13.680 0.170 14.150 0.610 ;
        RECT 13.680 13.170 14.150 13.610 ;
        RECT 13.680 14.470 14.150 14.910 ;
        RECT 13.680 15.770 14.150 16.210 ;
        RECT 13.680 17.070 14.150 17.510 ;
        RECT 13.680 18.370 14.150 18.810 ;
        RECT 13.680 19.670 14.150 20.110 ;
        RECT 13.680 20.970 14.150 21.410 ;
        RECT 0.080 23.570 0.550 24.010 ;
        RECT 1.780 23.570 2.250 24.010 ;
        RECT 3.480 23.570 3.950 24.010 ;
        RECT 5.180 23.570 5.650 24.010 ;
        RECT 6.880 23.570 7.350 24.010 ;
        RECT 8.580 23.570 9.050 24.010 ;
        RECT 10.280 23.570 10.750 24.010 ;
        RECT 11.980 23.570 12.450 24.010 ;
        RECT 13.680 23.570 14.150 24.010 ;
        RECT 15.380 23.570 15.850 24.010 ;
        RECT 17.080 23.570 17.550 24.010 ;
        RECT 18.780 23.570 19.250 24.010 ;
        RECT 20.480 23.570 20.950 24.010 ;
        RECT 22.180 23.570 22.650 24.010 ;
        RECT 23.880 23.570 24.350 24.010 ;
        RECT 25.580 23.570 26.050 24.010 ;
        RECT 13.680 24.870 14.150 25.310 ;
        RECT 13.680 26.170 14.150 26.610 ;
        RECT 13.680 27.470 14.150 27.910 ;
        RECT 13.680 28.770 14.150 29.210 ;
        RECT 13.680 30.070 14.150 30.510 ;
        RECT 13.680 31.370 14.150 31.810 ;
        RECT 13.680 32.670 14.150 33.110 ;
        RECT 13.680 35.270 14.150 35.710 ;
        RECT 13.680 36.570 14.150 37.010 ;
        RECT 13.680 1.470 14.150 1.910 ;
        RECT 13.680 37.870 14.150 38.310 ;
        RECT 13.680 39.170 14.150 39.610 ;
        RECT 13.680 40.470 14.150 40.910 ;
        RECT 13.680 41.770 14.150 42.210 ;
        RECT 13.680 43.070 14.150 43.510 ;
        RECT 20.480 24.870 20.950 25.310 ;
        RECT 20.480 26.170 20.950 26.610 ;
        RECT 20.480 27.470 20.950 27.910 ;
        RECT 20.480 28.770 20.950 29.210 ;
        RECT 20.480 30.070 20.950 30.510 ;
        RECT 20.480 31.370 20.950 31.810 ;
        RECT 20.480 32.670 20.950 33.110 ;
        RECT 20.480 46.970 20.950 47.410 ;
        RECT 20.480 35.270 20.950 35.710 ;
        RECT 20.480 36.570 20.950 37.010 ;
        RECT 20.480 37.870 20.950 38.310 ;
        RECT 20.480 39.170 20.950 39.610 ;
        RECT 20.480 40.470 20.950 40.910 ;
        RECT 20.480 44.370 20.950 44.810 ;
        RECT 20.480 41.770 20.950 42.210 ;
        RECT 20.480 43.070 20.950 43.510 ;
        RECT 23.880 46.970 24.350 47.410 ;
        RECT 25.580 46.970 26.050 47.410 ;
        RECT 23.880 44.370 24.350 44.810 ;
        RECT 22.180 37.870 22.650 38.310 ;
        RECT 23.880 37.870 24.350 38.310 ;
        RECT 25.580 37.870 26.050 38.310 ;
        RECT 22.180 46.970 22.650 47.410 ;
        RECT 22.180 39.170 22.650 39.610 ;
        RECT 23.880 39.170 24.350 39.610 ;
        RECT 25.580 39.170 26.050 39.610 ;
        RECT 25.580 44.370 26.050 44.810 ;
        RECT 22.180 40.470 22.650 40.910 ;
        RECT 23.880 40.470 24.350 40.910 ;
        RECT 25.580 40.470 26.050 40.910 ;
        RECT 22.180 36.570 22.650 37.010 ;
        RECT 23.880 36.570 24.350 37.010 ;
        RECT 22.180 41.770 22.650 42.210 ;
        RECT 23.880 41.770 24.350 42.210 ;
        RECT 25.580 41.770 26.050 42.210 ;
        RECT 22.180 44.370 22.650 44.810 ;
        RECT 25.580 36.570 26.050 37.010 ;
        RECT 22.180 43.070 22.650 43.510 ;
        RECT 23.880 43.070 24.350 43.510 ;
        RECT 25.580 43.070 26.050 43.510 ;
        RECT 18.780 44.370 19.250 44.810 ;
        RECT 15.380 40.470 15.850 40.910 ;
        RECT 17.080 40.470 17.550 40.910 ;
        RECT 18.780 40.470 19.250 40.910 ;
        RECT 17.080 37.870 17.550 38.310 ;
        RECT 18.780 37.870 19.250 38.310 ;
        RECT 18.780 36.570 19.250 37.010 ;
        RECT 15.380 44.370 15.850 44.810 ;
        RECT 17.080 46.970 17.550 47.410 ;
        RECT 15.380 41.770 15.850 42.210 ;
        RECT 17.080 41.770 17.550 42.210 ;
        RECT 18.780 41.770 19.250 42.210 ;
        RECT 15.380 46.970 15.850 47.410 ;
        RECT 17.080 44.370 17.550 44.810 ;
        RECT 15.380 39.170 15.850 39.610 ;
        RECT 17.080 39.170 17.550 39.610 ;
        RECT 18.780 39.170 19.250 39.610 ;
        RECT 15.380 43.070 15.850 43.510 ;
        RECT 17.080 43.070 17.550 43.510 ;
        RECT 18.780 43.070 19.250 43.510 ;
        RECT 18.780 46.970 19.250 47.410 ;
        RECT 15.380 36.570 15.850 37.010 ;
        RECT 17.080 36.570 17.550 37.010 ;
        RECT 15.380 37.870 15.850 38.310 ;
        RECT 17.080 28.770 17.550 29.210 ;
        RECT 18.780 28.770 19.250 29.210 ;
        RECT 17.080 26.170 17.550 26.610 ;
        RECT 18.780 26.170 19.250 26.610 ;
        RECT 15.380 30.070 15.850 30.510 ;
        RECT 17.080 30.070 17.550 30.510 ;
        RECT 18.780 30.070 19.250 30.510 ;
        RECT 18.780 24.870 19.250 25.310 ;
        RECT 15.380 24.870 15.850 25.310 ;
        RECT 15.380 31.370 15.850 31.810 ;
        RECT 17.080 31.370 17.550 31.810 ;
        RECT 18.780 31.370 19.250 31.810 ;
        RECT 15.380 27.470 15.850 27.910 ;
        RECT 17.080 27.470 17.550 27.910 ;
        RECT 15.380 32.670 15.850 33.110 ;
        RECT 17.080 32.670 17.550 33.110 ;
        RECT 18.780 32.670 19.250 33.110 ;
        RECT 18.780 27.470 19.250 27.910 ;
        RECT 17.080 24.870 17.550 25.310 ;
        RECT 15.380 35.270 15.850 35.710 ;
        RECT 17.080 35.270 17.550 35.710 ;
        RECT 18.780 35.270 19.250 35.710 ;
        RECT 15.380 26.170 15.850 26.610 ;
        RECT 15.380 28.770 15.850 29.210 ;
        RECT 22.180 24.870 22.650 25.310 ;
        RECT 23.880 24.870 24.350 25.310 ;
        RECT 22.180 26.170 22.650 26.610 ;
        RECT 22.180 28.770 22.650 29.210 ;
        RECT 22.180 31.370 22.650 31.810 ;
        RECT 23.880 31.370 24.350 31.810 ;
        RECT 25.580 31.370 26.050 31.810 ;
        RECT 23.880 28.770 24.350 29.210 ;
        RECT 25.580 28.770 26.050 29.210 ;
        RECT 23.880 26.170 24.350 26.610 ;
        RECT 22.180 27.470 22.650 27.910 ;
        RECT 23.880 27.470 24.350 27.910 ;
        RECT 22.180 32.670 22.650 33.110 ;
        RECT 23.880 32.670 24.350 33.110 ;
        RECT 25.580 32.670 26.050 33.110 ;
        RECT 25.580 27.470 26.050 27.910 ;
        RECT 25.580 26.170 26.050 26.610 ;
        RECT 22.180 30.070 22.650 30.510 ;
        RECT 23.880 30.070 24.350 30.510 ;
        RECT 25.580 30.070 26.050 30.510 ;
        RECT 22.180 35.270 22.650 35.710 ;
        RECT 23.880 35.270 24.350 35.710 ;
        RECT 25.580 35.270 26.050 35.710 ;
        RECT 25.580 24.870 26.050 25.310 ;
        RECT 6.880 27.470 7.350 27.910 ;
        RECT 6.880 24.870 7.350 25.310 ;
        RECT 6.880 35.270 7.350 35.710 ;
        RECT 6.880 36.570 7.350 37.010 ;
        RECT 6.880 28.770 7.350 29.210 ;
        RECT 6.880 46.970 7.350 47.410 ;
        RECT 6.880 37.870 7.350 38.310 ;
        RECT 6.880 30.070 7.350 30.510 ;
        RECT 6.880 39.170 7.350 39.610 ;
        RECT 6.880 26.170 7.350 26.610 ;
        RECT 6.880 40.470 7.350 40.910 ;
        RECT 6.880 44.370 7.350 44.810 ;
        RECT 6.880 31.370 7.350 31.810 ;
        RECT 6.880 41.770 7.350 42.210 ;
        RECT 6.880 43.070 7.350 43.510 ;
        RECT 6.880 32.670 7.350 33.110 ;
        RECT 11.980 36.570 12.450 37.010 ;
        RECT 11.980 44.370 12.450 44.810 ;
        RECT 8.580 39.170 9.050 39.610 ;
        RECT 10.280 39.170 10.750 39.610 ;
        RECT 11.980 39.170 12.450 39.610 ;
        RECT 8.580 36.570 9.050 37.010 ;
        RECT 11.980 46.970 12.450 47.410 ;
        RECT 8.580 46.970 9.050 47.410 ;
        RECT 8.580 40.470 9.050 40.910 ;
        RECT 10.280 40.470 10.750 40.910 ;
        RECT 11.980 40.470 12.450 40.910 ;
        RECT 10.280 46.970 10.750 47.410 ;
        RECT 8.580 44.370 9.050 44.810 ;
        RECT 10.280 44.370 10.750 44.810 ;
        RECT 10.280 36.570 10.750 37.010 ;
        RECT 8.580 37.870 9.050 38.310 ;
        RECT 8.580 41.770 9.050 42.210 ;
        RECT 10.280 41.770 10.750 42.210 ;
        RECT 11.980 41.770 12.450 42.210 ;
        RECT 10.280 37.870 10.750 38.310 ;
        RECT 8.580 43.070 9.050 43.510 ;
        RECT 10.280 43.070 10.750 43.510 ;
        RECT 11.980 43.070 12.450 43.510 ;
        RECT 11.980 37.870 12.450 38.310 ;
        RECT 1.780 40.470 2.250 40.910 ;
        RECT 3.480 40.470 3.950 40.910 ;
        RECT 5.180 40.470 5.650 40.910 ;
        RECT 5.180 37.870 5.650 38.310 ;
        RECT 1.780 46.970 2.250 47.410 ;
        RECT 3.480 46.970 3.950 47.410 ;
        RECT 0.080 36.570 0.550 37.010 ;
        RECT 1.780 36.570 2.250 37.010 ;
        RECT 5.180 46.970 5.650 47.410 ;
        RECT 0.080 39.170 0.550 39.610 ;
        RECT 1.780 39.170 2.250 39.610 ;
        RECT 0.080 41.770 0.550 42.210 ;
        RECT 1.780 41.770 2.250 42.210 ;
        RECT 3.480 41.770 3.950 42.210 ;
        RECT 5.180 41.770 5.650 42.210 ;
        RECT 3.480 39.170 3.950 39.610 ;
        RECT 5.180 39.170 5.650 39.610 ;
        RECT 3.480 36.570 3.950 37.010 ;
        RECT 5.180 36.570 5.650 37.010 ;
        RECT 0.080 43.070 0.550 43.510 ;
        RECT 1.780 43.070 2.250 43.510 ;
        RECT 3.480 43.070 3.950 43.510 ;
        RECT 5.180 43.070 5.650 43.510 ;
        RECT 0.080 46.970 0.550 47.410 ;
        RECT 0.080 37.870 0.550 38.310 ;
        RECT 1.780 37.870 2.250 38.310 ;
        RECT 3.480 37.870 3.950 38.310 ;
        RECT 0.080 40.470 0.550 40.910 ;
        RECT 0.080 44.370 0.550 44.810 ;
        RECT 1.780 44.370 2.250 44.810 ;
        RECT 3.480 44.370 3.950 44.810 ;
        RECT 5.180 44.370 5.650 44.810 ;
        RECT 0.080 28.770 0.550 29.210 ;
        RECT 1.780 26.170 2.250 26.610 ;
        RECT 3.480 26.170 3.950 26.610 ;
        RECT 5.180 26.170 5.650 26.610 ;
        RECT 0.080 30.070 0.550 30.510 ;
        RECT 1.780 30.070 2.250 30.510 ;
        RECT 3.480 30.070 3.950 30.510 ;
        RECT 0.080 24.870 0.550 25.310 ;
        RECT 1.780 24.870 2.250 25.310 ;
        RECT 3.480 24.870 3.950 25.310 ;
        RECT 5.180 24.870 5.650 25.310 ;
        RECT 0.080 27.470 0.550 27.910 ;
        RECT 5.180 30.070 5.650 30.510 ;
        RECT 0.080 26.170 0.550 26.610 ;
        RECT 1.780 28.770 2.250 29.210 ;
        RECT 3.480 28.770 3.950 29.210 ;
        RECT 5.180 28.770 5.650 29.210 ;
        RECT 1.780 35.270 2.250 35.710 ;
        RECT 3.480 35.270 3.950 35.710 ;
        RECT 0.080 31.370 0.550 31.810 ;
        RECT 1.780 27.470 2.250 27.910 ;
        RECT 3.480 27.470 3.950 27.910 ;
        RECT 5.180 27.470 5.650 27.910 ;
        RECT 0.080 32.670 0.550 33.110 ;
        RECT 1.780 32.670 2.250 33.110 ;
        RECT 3.480 32.670 3.950 33.110 ;
        RECT 5.180 32.670 5.650 33.110 ;
        RECT 1.780 31.370 2.250 31.810 ;
        RECT 3.480 31.370 3.950 31.810 ;
        RECT 5.180 31.370 5.650 31.810 ;
        RECT 5.180 35.270 5.650 35.710 ;
        RECT 0.080 35.270 0.550 35.710 ;
        RECT 10.280 35.270 10.750 35.710 ;
        RECT 11.980 35.270 12.450 35.710 ;
        RECT 10.280 32.670 10.750 33.110 ;
        RECT 8.580 24.870 9.050 25.310 ;
        RECT 10.280 24.870 10.750 25.310 ;
        RECT 11.980 24.870 12.450 25.310 ;
        RECT 11.980 32.670 12.450 33.110 ;
        RECT 8.580 28.770 9.050 29.210 ;
        RECT 10.280 28.770 10.750 29.210 ;
        RECT 8.580 30.070 9.050 30.510 ;
        RECT 10.280 30.070 10.750 30.510 ;
        RECT 11.980 30.070 12.450 30.510 ;
        RECT 11.980 28.770 12.450 29.210 ;
        RECT 8.580 26.170 9.050 26.610 ;
        RECT 10.280 26.170 10.750 26.610 ;
        RECT 11.980 26.170 12.450 26.610 ;
        RECT 8.580 32.670 9.050 33.110 ;
        RECT 8.580 27.470 9.050 27.910 ;
        RECT 10.280 27.470 10.750 27.910 ;
        RECT 11.980 27.470 12.450 27.910 ;
        RECT 8.580 31.370 9.050 31.810 ;
        RECT 10.280 31.370 10.750 31.810 ;
        RECT 11.980 31.370 12.450 31.810 ;
        RECT 8.580 35.270 9.050 35.710 ;
        RECT 6.880 4.070 7.350 4.510 ;
        RECT 6.880 5.370 7.350 5.810 ;
        RECT 6.880 0.170 7.350 0.610 ;
        RECT 6.880 6.670 7.350 7.110 ;
        RECT 6.880 7.970 7.350 8.410 ;
        RECT 6.880 9.270 7.350 9.710 ;
        RECT 6.880 2.770 7.350 3.210 ;
        RECT 0.080 11.870 0.550 12.310 ;
        RECT 1.780 11.870 2.250 12.310 ;
        RECT 3.480 11.870 3.950 12.310 ;
        RECT 5.180 11.870 5.650 12.310 ;
        RECT 6.880 11.870 7.350 12.310 ;
        RECT 8.580 11.870 9.050 12.310 ;
        RECT 10.280 11.870 10.750 12.310 ;
        RECT 11.980 11.870 12.450 12.310 ;
        RECT 6.880 13.170 7.350 13.610 ;
        RECT 6.880 14.470 7.350 14.910 ;
        RECT 6.880 15.770 7.350 16.210 ;
        RECT 6.880 17.070 7.350 17.510 ;
        RECT 6.880 1.470 7.350 1.910 ;
        RECT 6.880 18.370 7.350 18.810 ;
        RECT 6.880 19.670 7.350 20.110 ;
        RECT 6.880 20.970 7.350 21.410 ;
        RECT 10.280 13.170 10.750 13.610 ;
        RECT 8.580 15.770 9.050 16.210 ;
        RECT 10.280 15.770 10.750 16.210 ;
        RECT 11.980 15.770 12.450 16.210 ;
        RECT 11.980 13.170 12.450 13.610 ;
        RECT 8.580 17.070 9.050 17.510 ;
        RECT 10.280 17.070 10.750 17.510 ;
        RECT 11.980 17.070 12.450 17.510 ;
        RECT 8.580 13.170 9.050 13.610 ;
        RECT 8.580 14.470 9.050 14.910 ;
        RECT 8.580 18.370 9.050 18.810 ;
        RECT 10.280 18.370 10.750 18.810 ;
        RECT 11.980 18.370 12.450 18.810 ;
        RECT 10.280 14.470 10.750 14.910 ;
        RECT 8.580 19.670 9.050 20.110 ;
        RECT 10.280 19.670 10.750 20.110 ;
        RECT 11.980 19.670 12.450 20.110 ;
        RECT 11.980 14.470 12.450 14.910 ;
        RECT 8.580 20.970 9.050 21.410 ;
        RECT 10.280 20.970 10.750 21.410 ;
        RECT 11.980 20.970 12.450 21.410 ;
        RECT 1.780 13.170 2.250 13.610 ;
        RECT 3.480 13.170 3.950 13.610 ;
        RECT 5.180 13.170 5.650 13.610 ;
        RECT 0.080 18.370 0.550 18.810 ;
        RECT 1.780 18.370 2.250 18.810 ;
        RECT 3.480 18.370 3.950 18.810 ;
        RECT 5.180 18.370 5.650 18.810 ;
        RECT 0.080 15.770 0.550 16.210 ;
        RECT 1.780 15.770 2.250 16.210 ;
        RECT 3.480 15.770 3.950 16.210 ;
        RECT 5.180 15.770 5.650 16.210 ;
        RECT 0.080 14.470 0.550 14.910 ;
        RECT 0.080 19.670 0.550 20.110 ;
        RECT 1.780 19.670 2.250 20.110 ;
        RECT 3.480 19.670 3.950 20.110 ;
        RECT 5.180 19.670 5.650 20.110 ;
        RECT 1.780 14.470 2.250 14.910 ;
        RECT 3.480 14.470 3.950 14.910 ;
        RECT 5.180 14.470 5.650 14.910 ;
        RECT 0.080 17.070 0.550 17.510 ;
        RECT 0.080 20.970 0.550 21.410 ;
        RECT 1.780 20.970 2.250 21.410 ;
        RECT 3.480 20.970 3.950 21.410 ;
        RECT 5.180 20.970 5.650 21.410 ;
        RECT 1.780 17.070 2.250 17.510 ;
        RECT 3.480 17.070 3.950 17.510 ;
        RECT 5.180 17.070 5.650 17.510 ;
        RECT 0.080 13.170 0.550 13.610 ;
        RECT 5.180 7.970 5.650 8.410 ;
        RECT 1.780 5.370 2.250 5.810 ;
        RECT 0.080 1.470 0.550 1.910 ;
        RECT 0.080 4.070 0.550 4.510 ;
        RECT 3.480 1.470 3.950 1.910 ;
        RECT 5.180 2.770 5.650 3.210 ;
        RECT 0.080 9.270 0.550 9.710 ;
        RECT 1.780 9.270 2.250 9.710 ;
        RECT 3.480 9.270 3.950 9.710 ;
        RECT 5.180 9.270 5.650 9.710 ;
        RECT 3.480 5.370 3.950 5.810 ;
        RECT 5.180 5.370 5.650 5.810 ;
        RECT 0.080 2.770 0.550 3.210 ;
        RECT 1.780 4.070 2.250 4.510 ;
        RECT 1.780 0.170 2.250 0.610 ;
        RECT 1.780 2.770 2.250 3.210 ;
        RECT 1.780 1.470 2.250 1.910 ;
        RECT 5.180 0.170 5.650 0.610 ;
        RECT 0.080 0.170 0.550 0.610 ;
        RECT 0.080 6.670 0.550 7.110 ;
        RECT 1.780 6.670 2.250 7.110 ;
        RECT 5.180 1.470 5.650 1.910 ;
        RECT 3.480 4.070 3.950 4.510 ;
        RECT 3.480 6.670 3.950 7.110 ;
        RECT 5.180 6.670 5.650 7.110 ;
        RECT 3.480 0.170 3.950 0.610 ;
        RECT 0.080 5.370 0.550 5.810 ;
        RECT 3.480 2.770 3.950 3.210 ;
        RECT 0.080 7.970 0.550 8.410 ;
        RECT 1.780 7.970 2.250 8.410 ;
        RECT 3.480 7.970 3.950 8.410 ;
        RECT 5.180 4.070 5.650 4.510 ;
        RECT 8.580 6.670 9.050 7.110 ;
        RECT 8.580 2.770 9.050 3.210 ;
        RECT 10.280 2.770 10.750 3.210 ;
        RECT 10.280 0.170 10.750 0.610 ;
        RECT 10.280 6.670 10.750 7.110 ;
        RECT 11.980 6.670 12.450 7.110 ;
        RECT 11.980 1.470 12.450 1.910 ;
        RECT 10.280 1.470 10.750 1.910 ;
        RECT 8.580 0.170 9.050 0.610 ;
        RECT 8.580 9.270 9.050 9.710 ;
        RECT 10.280 9.270 10.750 9.710 ;
        RECT 11.980 9.270 12.450 9.710 ;
        RECT 11.980 2.770 12.450 3.210 ;
        RECT 11.980 4.070 12.450 4.510 ;
        RECT 11.980 0.170 12.450 0.610 ;
        RECT 8.580 4.070 9.050 4.510 ;
        RECT 8.580 1.470 9.050 1.910 ;
        RECT 8.580 5.370 9.050 5.810 ;
        RECT 10.280 5.370 10.750 5.810 ;
        RECT 11.980 5.370 12.450 5.810 ;
        RECT 8.580 7.970 9.050 8.410 ;
        RECT 10.280 4.070 10.750 4.510 ;
        RECT 10.280 7.970 10.750 8.410 ;
        RECT 11.980 7.970 12.450 8.410 ;
        RECT 20.480 9.270 20.950 9.710 ;
        RECT 20.480 17.070 20.950 17.510 ;
        RECT 20.480 0.170 20.950 0.610 ;
        RECT 20.480 6.670 20.950 7.110 ;
        RECT 15.380 11.870 15.850 12.310 ;
        RECT 17.080 11.870 17.550 12.310 ;
        RECT 20.480 18.370 20.950 18.810 ;
        RECT 18.780 11.870 19.250 12.310 ;
        RECT 20.480 11.870 20.950 12.310 ;
        RECT 22.180 11.870 22.650 12.310 ;
        RECT 23.880 11.870 24.350 12.310 ;
        RECT 25.580 11.870 26.050 12.310 ;
        RECT 20.480 2.770 20.950 3.210 ;
        RECT 20.480 19.670 20.950 20.110 ;
        RECT 20.480 5.370 20.950 5.810 ;
        RECT 20.480 20.970 20.950 21.410 ;
        RECT 20.480 13.170 20.950 13.610 ;
        RECT 20.480 7.970 20.950 8.410 ;
        RECT 20.480 14.470 20.950 14.910 ;
        RECT 20.480 1.470 20.950 1.910 ;
        RECT 20.480 4.070 20.950 4.510 ;
        RECT 20.480 15.770 20.950 16.210 ;
        RECT 25.580 19.670 26.050 20.110 ;
        RECT 22.180 17.070 22.650 17.510 ;
        RECT 23.880 17.070 24.350 17.510 ;
        RECT 22.180 20.970 22.650 21.410 ;
        RECT 23.880 20.970 24.350 21.410 ;
        RECT 25.580 20.970 26.050 21.410 ;
        RECT 22.180 18.370 22.650 18.810 ;
        RECT 22.180 13.170 22.650 13.610 ;
        RECT 23.880 13.170 24.350 13.610 ;
        RECT 25.580 13.170 26.050 13.610 ;
        RECT 23.880 18.370 24.350 18.810 ;
        RECT 25.580 18.370 26.050 18.810 ;
        RECT 22.180 14.470 22.650 14.910 ;
        RECT 23.880 14.470 24.350 14.910 ;
        RECT 25.580 17.070 26.050 17.510 ;
        RECT 25.580 14.470 26.050 14.910 ;
        RECT 22.180 19.670 22.650 20.110 ;
        RECT 23.880 19.670 24.350 20.110 ;
        RECT 22.180 15.770 22.650 16.210 ;
        RECT 23.880 15.770 24.350 16.210 ;
        RECT 25.580 15.770 26.050 16.210 ;
        RECT 17.080 18.370 17.550 18.810 ;
        RECT 18.780 18.370 19.250 18.810 ;
        RECT 18.780 17.070 19.250 17.510 ;
        RECT 15.380 17.070 15.850 17.510 ;
        RECT 17.080 17.070 17.550 17.510 ;
        RECT 15.380 14.470 15.850 14.910 ;
        RECT 17.080 14.470 17.550 14.910 ;
        RECT 18.780 14.470 19.250 14.910 ;
        RECT 15.380 13.170 15.850 13.610 ;
        RECT 17.080 13.170 17.550 13.610 ;
        RECT 18.780 13.170 19.250 13.610 ;
        RECT 15.380 20.970 15.850 21.410 ;
        RECT 17.080 20.970 17.550 21.410 ;
        RECT 18.780 20.970 19.250 21.410 ;
        RECT 15.380 15.770 15.850 16.210 ;
        RECT 17.080 15.770 17.550 16.210 ;
        RECT 18.780 15.770 19.250 16.210 ;
        RECT 15.380 18.370 15.850 18.810 ;
        RECT 15.380 19.670 15.850 20.110 ;
        RECT 17.080 19.670 17.550 20.110 ;
        RECT 18.780 19.670 19.250 20.110 ;
        RECT 18.780 7.970 19.250 8.410 ;
        RECT 18.780 2.770 19.250 3.210 ;
        RECT 15.380 6.670 15.850 7.110 ;
        RECT 17.080 6.670 17.550 7.110 ;
        RECT 18.780 6.670 19.250 7.110 ;
        RECT 18.780 9.270 19.250 9.710 ;
        RECT 15.380 2.770 15.850 3.210 ;
        RECT 15.380 4.070 15.850 4.510 ;
        RECT 15.380 5.370 15.850 5.810 ;
        RECT 17.080 5.370 17.550 5.810 ;
        RECT 17.080 0.170 17.550 0.610 ;
        RECT 17.080 4.070 17.550 4.510 ;
        RECT 18.780 4.070 19.250 4.510 ;
        RECT 18.780 5.370 19.250 5.810 ;
        RECT 15.380 9.270 15.850 9.710 ;
        RECT 17.080 1.470 17.550 1.910 ;
        RECT 15.380 1.470 15.850 1.910 ;
        RECT 17.080 2.770 17.550 3.210 ;
        RECT 18.780 1.470 19.250 1.910 ;
        RECT 15.380 0.170 15.850 0.610 ;
        RECT 15.380 7.970 15.850 8.410 ;
        RECT 17.080 7.970 17.550 8.410 ;
        RECT 18.780 0.170 19.250 0.610 ;
        RECT 17.080 9.270 17.550 9.710 ;
        RECT 25.580 6.670 26.050 7.110 ;
        RECT 22.180 9.270 22.650 9.710 ;
        RECT 23.880 9.270 24.350 9.710 ;
        RECT 25.580 9.270 26.050 9.710 ;
        RECT 22.180 0.170 22.650 0.610 ;
        RECT 25.580 5.370 26.050 5.810 ;
        RECT 23.880 0.170 24.350 0.610 ;
        RECT 23.880 1.470 24.350 1.910 ;
        RECT 22.180 2.770 22.650 3.210 ;
        RECT 22.180 4.070 22.650 4.510 ;
        RECT 23.880 4.070 24.350 4.510 ;
        RECT 25.580 4.070 26.050 4.510 ;
        RECT 25.580 1.470 26.050 1.910 ;
        RECT 23.880 2.770 24.350 3.210 ;
        RECT 22.180 7.970 22.650 8.410 ;
        RECT 23.880 7.970 24.350 8.410 ;
        RECT 25.580 7.970 26.050 8.410 ;
        RECT 22.180 5.370 22.650 5.810 ;
        RECT 23.880 5.370 24.350 5.810 ;
        RECT 22.180 1.470 22.650 1.910 ;
        RECT 25.580 2.770 26.050 3.210 ;
        RECT 22.180 6.670 22.650 7.110 ;
        RECT 25.580 0.170 26.050 0.610 ;
        RECT 23.880 6.670 24.350 7.110 ;
        RECT 40.880 26.170 41.350 26.610 ;
        RECT 40.880 1.470 41.350 1.910 ;
        RECT 40.880 6.670 41.350 7.110 ;
        RECT 40.880 27.470 41.350 27.910 ;
        RECT 40.880 14.470 41.350 14.910 ;
        RECT 40.880 28.770 41.350 29.210 ;
        RECT 40.880 30.070 41.350 30.510 ;
        RECT 40.880 15.770 41.350 16.210 ;
        RECT 40.880 31.370 41.350 31.810 ;
        RECT 40.880 7.970 41.350 8.410 ;
        RECT 40.880 32.670 41.350 33.110 ;
        RECT 40.880 17.070 41.350 17.510 ;
        RECT 40.880 4.070 41.350 4.510 ;
        RECT 40.880 35.270 41.350 35.710 ;
        RECT 40.880 0.170 41.350 0.610 ;
        RECT 40.880 18.370 41.350 18.810 ;
        RECT 40.880 36.570 41.350 37.010 ;
        RECT 40.880 9.270 41.350 9.710 ;
        RECT 40.880 37.870 41.350 38.310 ;
        RECT 40.880 19.670 41.350 20.110 ;
        RECT 40.880 39.170 41.350 39.610 ;
        RECT 40.880 40.470 41.350 40.910 ;
        RECT 40.880 20.970 41.350 21.410 ;
        RECT 40.880 41.770 41.350 42.210 ;
        RECT 40.880 5.370 41.350 5.810 ;
        RECT 40.880 11.870 41.350 12.310 ;
        RECT 40.880 43.070 41.350 43.510 ;
        RECT 28.980 23.570 29.450 24.010 ;
        RECT 30.680 23.570 31.150 24.010 ;
        RECT 32.380 23.570 32.850 24.010 ;
        RECT 34.080 23.570 34.550 24.010 ;
        RECT 35.780 23.570 36.250 24.010 ;
        RECT 37.480 23.570 37.950 24.010 ;
        RECT 39.180 23.570 39.650 24.010 ;
        RECT 40.880 23.570 41.350 24.010 ;
        RECT 42.580 23.570 43.050 24.010 ;
        RECT 44.280 23.570 44.750 24.010 ;
        RECT 45.980 23.570 46.450 24.010 ;
        RECT 47.680 23.570 48.150 24.010 ;
        RECT 49.380 23.570 49.850 24.010 ;
        RECT 51.080 23.570 51.550 24.010 ;
        RECT 52.780 23.570 53.250 24.010 ;
        RECT 40.880 44.370 41.350 44.810 ;
        RECT 40.880 2.770 41.350 3.210 ;
        RECT 40.880 46.970 41.350 47.410 ;
        RECT 40.880 24.870 41.350 25.310 ;
        RECT 40.880 13.170 41.350 13.610 ;
        RECT 47.680 32.670 48.150 33.110 ;
        RECT 47.680 35.270 48.150 35.710 ;
        RECT 47.680 27.470 48.150 27.910 ;
        RECT 47.680 36.570 48.150 37.010 ;
        RECT 47.680 26.170 48.150 26.610 ;
        RECT 47.680 37.870 48.150 38.310 ;
        RECT 47.680 39.170 48.150 39.610 ;
        RECT 47.680 40.470 48.150 40.910 ;
        RECT 47.680 28.770 48.150 29.210 ;
        RECT 47.680 41.770 48.150 42.210 ;
        RECT 47.680 43.070 48.150 43.510 ;
        RECT 47.680 30.070 48.150 30.510 ;
        RECT 47.680 31.370 48.150 31.810 ;
        RECT 47.680 44.370 48.150 44.810 ;
        RECT 47.680 46.970 48.150 47.410 ;
        RECT 47.680 24.870 48.150 25.310 ;
        RECT 49.380 36.570 49.850 37.010 ;
        RECT 49.380 40.470 49.850 40.910 ;
        RECT 51.080 40.470 51.550 40.910 ;
        RECT 52.780 40.470 53.250 40.910 ;
        RECT 51.080 36.570 51.550 37.010 ;
        RECT 49.380 37.870 49.850 38.310 ;
        RECT 49.380 41.770 49.850 42.210 ;
        RECT 51.080 41.770 51.550 42.210 ;
        RECT 52.780 41.770 53.250 42.210 ;
        RECT 51.080 37.870 51.550 38.310 ;
        RECT 49.380 43.070 49.850 43.510 ;
        RECT 51.080 43.070 51.550 43.510 ;
        RECT 52.780 43.070 53.250 43.510 ;
        RECT 52.780 37.870 53.250 38.310 ;
        RECT 52.780 36.570 53.250 37.010 ;
        RECT 49.380 39.170 49.850 39.610 ;
        RECT 49.380 44.370 49.850 44.810 ;
        RECT 51.080 44.370 51.550 44.810 ;
        RECT 52.780 44.370 53.250 44.810 ;
        RECT 51.080 39.170 51.550 39.610 ;
        RECT 49.380 46.970 49.850 47.410 ;
        RECT 51.080 46.970 51.550 47.410 ;
        RECT 52.780 46.970 53.250 47.410 ;
        RECT 52.780 39.170 53.250 39.610 ;
        RECT 42.580 43.070 43.050 43.510 ;
        RECT 44.280 43.070 44.750 43.510 ;
        RECT 45.980 43.070 46.450 43.510 ;
        RECT 42.580 40.470 43.050 40.910 ;
        RECT 44.280 40.470 44.750 40.910 ;
        RECT 45.980 40.470 46.450 40.910 ;
        RECT 44.280 36.570 44.750 37.010 ;
        RECT 42.580 37.870 43.050 38.310 ;
        RECT 42.580 39.170 43.050 39.610 ;
        RECT 42.580 44.370 43.050 44.810 ;
        RECT 44.280 44.370 44.750 44.810 ;
        RECT 45.980 44.370 46.450 44.810 ;
        RECT 44.280 39.170 44.750 39.610 ;
        RECT 45.980 39.170 46.450 39.610 ;
        RECT 42.580 41.770 43.050 42.210 ;
        RECT 44.280 41.770 44.750 42.210 ;
        RECT 42.580 46.970 43.050 47.410 ;
        RECT 44.280 46.970 44.750 47.410 ;
        RECT 45.980 46.970 46.450 47.410 ;
        RECT 45.980 41.770 46.450 42.210 ;
        RECT 44.280 37.870 44.750 38.310 ;
        RECT 45.980 37.870 46.450 38.310 ;
        RECT 45.980 36.570 46.450 37.010 ;
        RECT 42.580 36.570 43.050 37.010 ;
        RECT 44.280 31.370 44.750 31.810 ;
        RECT 45.980 31.370 46.450 31.810 ;
        RECT 44.280 32.670 44.750 33.110 ;
        RECT 42.580 27.470 43.050 27.910 ;
        RECT 44.280 27.470 44.750 27.910 ;
        RECT 45.980 27.470 46.450 27.910 ;
        RECT 42.580 35.270 43.050 35.710 ;
        RECT 45.980 28.770 46.450 29.210 ;
        RECT 44.280 35.270 44.750 35.710 ;
        RECT 45.980 35.270 46.450 35.710 ;
        RECT 44.280 26.170 44.750 26.610 ;
        RECT 44.280 28.770 44.750 29.210 ;
        RECT 45.980 32.670 46.450 33.110 ;
        RECT 42.580 30.070 43.050 30.510 ;
        RECT 44.280 30.070 44.750 30.510 ;
        RECT 45.980 30.070 46.450 30.510 ;
        RECT 42.580 28.770 43.050 29.210 ;
        RECT 42.580 26.170 43.050 26.610 ;
        RECT 45.980 26.170 46.450 26.610 ;
        RECT 42.580 24.870 43.050 25.310 ;
        RECT 44.280 24.870 44.750 25.310 ;
        RECT 45.980 24.870 46.450 25.310 ;
        RECT 42.580 31.370 43.050 31.810 ;
        RECT 42.580 32.670 43.050 33.110 ;
        RECT 49.380 26.170 49.850 26.610 ;
        RECT 52.780 27.470 53.250 27.910 ;
        RECT 51.080 27.470 51.550 27.910 ;
        RECT 51.080 26.170 51.550 26.610 ;
        RECT 52.780 32.670 53.250 33.110 ;
        RECT 49.380 32.670 49.850 33.110 ;
        RECT 52.780 31.370 53.250 31.810 ;
        RECT 49.380 35.270 49.850 35.710 ;
        RECT 49.380 28.770 49.850 29.210 ;
        RECT 49.380 30.070 49.850 30.510 ;
        RECT 51.080 30.070 51.550 30.510 ;
        RECT 52.780 30.070 53.250 30.510 ;
        RECT 52.780 26.170 53.250 26.610 ;
        RECT 51.080 28.770 51.550 29.210 ;
        RECT 52.780 28.770 53.250 29.210 ;
        RECT 51.080 35.270 51.550 35.710 ;
        RECT 52.780 35.270 53.250 35.710 ;
        RECT 51.080 32.670 51.550 33.110 ;
        RECT 49.380 31.370 49.850 31.810 ;
        RECT 51.080 31.370 51.550 31.810 ;
        RECT 49.380 24.870 49.850 25.310 ;
        RECT 51.080 24.870 51.550 25.310 ;
        RECT 52.780 24.870 53.250 25.310 ;
        RECT 49.380 27.470 49.850 27.910 ;
        RECT 34.080 40.470 34.550 40.910 ;
        RECT 34.080 35.270 34.550 35.710 ;
        RECT 34.080 41.770 34.550 42.210 ;
        RECT 34.080 28.770 34.550 29.210 ;
        RECT 34.080 31.370 34.550 31.810 ;
        RECT 34.080 43.070 34.550 43.510 ;
        RECT 34.080 36.570 34.550 37.010 ;
        RECT 34.080 37.870 34.550 38.310 ;
        RECT 34.080 44.370 34.550 44.810 ;
        RECT 34.080 27.470 34.550 27.910 ;
        RECT 34.080 32.670 34.550 33.110 ;
        RECT 34.080 46.970 34.550 47.410 ;
        RECT 34.080 39.170 34.550 39.610 ;
        RECT 34.080 24.870 34.550 25.310 ;
        RECT 34.080 30.070 34.550 30.510 ;
        RECT 34.080 26.170 34.550 26.610 ;
        RECT 35.780 36.570 36.250 37.010 ;
        RECT 37.480 36.570 37.950 37.010 ;
        RECT 39.180 36.570 39.650 37.010 ;
        RECT 37.480 41.770 37.950 42.210 ;
        RECT 35.780 37.870 36.250 38.310 ;
        RECT 37.480 37.870 37.950 38.310 ;
        RECT 39.180 37.870 39.650 38.310 ;
        RECT 39.180 41.770 39.650 42.210 ;
        RECT 35.780 44.370 36.250 44.810 ;
        RECT 37.480 44.370 37.950 44.810 ;
        RECT 39.180 44.370 39.650 44.810 ;
        RECT 39.180 40.470 39.650 40.910 ;
        RECT 35.780 40.470 36.250 40.910 ;
        RECT 37.480 40.470 37.950 40.910 ;
        RECT 35.780 46.970 36.250 47.410 ;
        RECT 37.480 46.970 37.950 47.410 ;
        RECT 39.180 46.970 39.650 47.410 ;
        RECT 35.780 43.070 36.250 43.510 ;
        RECT 35.780 39.170 36.250 39.610 ;
        RECT 37.480 39.170 37.950 39.610 ;
        RECT 39.180 39.170 39.650 39.610 ;
        RECT 37.480 43.070 37.950 43.510 ;
        RECT 39.180 43.070 39.650 43.510 ;
        RECT 35.780 41.770 36.250 42.210 ;
        RECT 32.380 36.570 32.850 37.010 ;
        RECT 28.980 43.070 29.450 43.510 ;
        RECT 30.680 43.070 31.150 43.510 ;
        RECT 32.380 43.070 32.850 43.510 ;
        RECT 30.680 41.770 31.150 42.210 ;
        RECT 28.980 46.970 29.450 47.410 ;
        RECT 30.680 46.970 31.150 47.410 ;
        RECT 32.380 46.970 32.850 47.410 ;
        RECT 28.980 37.870 29.450 38.310 ;
        RECT 30.680 37.870 31.150 38.310 ;
        RECT 32.380 37.870 32.850 38.310 ;
        RECT 32.380 41.770 32.850 42.210 ;
        RECT 28.980 39.170 29.450 39.610 ;
        RECT 30.680 39.170 31.150 39.610 ;
        RECT 32.380 39.170 32.850 39.610 ;
        RECT 32.380 40.470 32.850 40.910 ;
        RECT 28.980 41.770 29.450 42.210 ;
        RECT 28.980 36.570 29.450 37.010 ;
        RECT 28.980 44.370 29.450 44.810 ;
        RECT 30.680 44.370 31.150 44.810 ;
        RECT 32.380 44.370 32.850 44.810 ;
        RECT 28.980 40.470 29.450 40.910 ;
        RECT 30.680 40.470 31.150 40.910 ;
        RECT 30.680 36.570 31.150 37.010 ;
        RECT 32.380 28.770 32.850 29.210 ;
        RECT 30.680 35.270 31.150 35.710 ;
        RECT 28.980 27.470 29.450 27.910 ;
        RECT 30.680 27.470 31.150 27.910 ;
        RECT 32.380 27.470 32.850 27.910 ;
        RECT 28.980 31.370 29.450 31.810 ;
        RECT 30.680 31.370 31.150 31.810 ;
        RECT 32.380 31.370 32.850 31.810 ;
        RECT 28.980 30.070 29.450 30.510 ;
        RECT 28.980 32.670 29.450 33.110 ;
        RECT 30.680 32.670 31.150 33.110 ;
        RECT 30.680 30.070 31.150 30.510 ;
        RECT 28.980 24.870 29.450 25.310 ;
        RECT 30.680 24.870 31.150 25.310 ;
        RECT 32.380 24.870 32.850 25.310 ;
        RECT 32.380 32.670 32.850 33.110 ;
        RECT 32.380 30.070 32.850 30.510 ;
        RECT 32.380 35.270 32.850 35.710 ;
        RECT 28.980 28.770 29.450 29.210 ;
        RECT 30.680 28.770 31.150 29.210 ;
        RECT 28.980 26.170 29.450 26.610 ;
        RECT 30.680 26.170 31.150 26.610 ;
        RECT 32.380 26.170 32.850 26.610 ;
        RECT 28.980 35.270 29.450 35.710 ;
        RECT 39.180 31.370 39.650 31.810 ;
        RECT 39.180 27.470 39.650 27.910 ;
        RECT 35.780 32.670 36.250 33.110 ;
        RECT 37.480 32.670 37.950 33.110 ;
        RECT 39.180 32.670 39.650 33.110 ;
        RECT 37.480 26.170 37.950 26.610 ;
        RECT 39.180 26.170 39.650 26.610 ;
        RECT 35.780 26.170 36.250 26.610 ;
        RECT 35.780 24.870 36.250 25.310 ;
        RECT 37.480 24.870 37.950 25.310 ;
        RECT 39.180 24.870 39.650 25.310 ;
        RECT 37.480 28.770 37.950 29.210 ;
        RECT 39.180 28.770 39.650 29.210 ;
        RECT 35.780 30.070 36.250 30.510 ;
        RECT 37.480 30.070 37.950 30.510 ;
        RECT 39.180 30.070 39.650 30.510 ;
        RECT 35.780 27.470 36.250 27.910 ;
        RECT 37.480 27.470 37.950 27.910 ;
        RECT 35.780 35.270 36.250 35.710 ;
        RECT 37.480 35.270 37.950 35.710 ;
        RECT 39.180 35.270 39.650 35.710 ;
        RECT 35.780 28.770 36.250 29.210 ;
        RECT 35.780 31.370 36.250 31.810 ;
        RECT 37.480 31.370 37.950 31.810 ;
        RECT 34.080 9.270 34.550 9.710 ;
        RECT 28.980 11.870 29.450 12.310 ;
        RECT 30.680 11.870 31.150 12.310 ;
        RECT 32.380 11.870 32.850 12.310 ;
        RECT 34.080 11.870 34.550 12.310 ;
        RECT 35.780 11.870 36.250 12.310 ;
        RECT 37.480 11.870 37.950 12.310 ;
        RECT 39.180 11.870 39.650 12.310 ;
        RECT 34.080 14.470 34.550 14.910 ;
        RECT 34.080 4.070 34.550 4.510 ;
        RECT 34.080 19.670 34.550 20.110 ;
        RECT 34.080 0.170 34.550 0.610 ;
        RECT 34.080 15.770 34.550 16.210 ;
        RECT 34.080 2.770 34.550 3.210 ;
        RECT 34.080 18.370 34.550 18.810 ;
        RECT 34.080 7.970 34.550 8.410 ;
        RECT 34.080 5.370 34.550 5.810 ;
        RECT 34.080 20.970 34.550 21.410 ;
        RECT 34.080 13.170 34.550 13.610 ;
        RECT 34.080 6.670 34.550 7.110 ;
        RECT 34.080 1.470 34.550 1.910 ;
        RECT 34.080 17.070 34.550 17.510 ;
        RECT 37.480 15.770 37.950 16.210 ;
        RECT 35.780 15.770 36.250 16.210 ;
        RECT 39.180 14.470 39.650 14.910 ;
        RECT 39.180 15.770 39.650 16.210 ;
        RECT 35.780 14.470 36.250 14.910 ;
        RECT 35.780 18.370 36.250 18.810 ;
        RECT 37.480 18.370 37.950 18.810 ;
        RECT 39.180 18.370 39.650 18.810 ;
        RECT 35.780 17.070 36.250 17.510 ;
        RECT 37.480 17.070 37.950 17.510 ;
        RECT 35.780 19.670 36.250 20.110 ;
        RECT 35.780 20.970 36.250 21.410 ;
        RECT 37.480 20.970 37.950 21.410 ;
        RECT 39.180 20.970 39.650 21.410 ;
        RECT 37.480 19.670 37.950 20.110 ;
        RECT 35.780 13.170 36.250 13.610 ;
        RECT 37.480 13.170 37.950 13.610 ;
        RECT 39.180 13.170 39.650 13.610 ;
        RECT 39.180 19.670 39.650 20.110 ;
        RECT 37.480 14.470 37.950 14.910 ;
        RECT 39.180 17.070 39.650 17.510 ;
        RECT 32.380 15.770 32.850 16.210 ;
        RECT 32.380 14.470 32.850 14.910 ;
        RECT 28.980 20.970 29.450 21.410 ;
        RECT 30.680 20.970 31.150 21.410 ;
        RECT 32.380 20.970 32.850 21.410 ;
        RECT 28.980 14.470 29.450 14.910 ;
        RECT 30.680 14.470 31.150 14.910 ;
        RECT 28.980 19.670 29.450 20.110 ;
        RECT 28.980 13.170 29.450 13.610 ;
        RECT 30.680 13.170 31.150 13.610 ;
        RECT 32.380 13.170 32.850 13.610 ;
        RECT 28.980 18.370 29.450 18.810 ;
        RECT 30.680 18.370 31.150 18.810 ;
        RECT 32.380 18.370 32.850 18.810 ;
        RECT 30.680 19.670 31.150 20.110 ;
        RECT 32.380 19.670 32.850 20.110 ;
        RECT 28.980 15.770 29.450 16.210 ;
        RECT 28.980 17.070 29.450 17.510 ;
        RECT 30.680 17.070 31.150 17.510 ;
        RECT 32.380 17.070 32.850 17.510 ;
        RECT 30.680 15.770 31.150 16.210 ;
        RECT 32.380 6.670 32.850 7.110 ;
        RECT 32.380 7.970 32.850 8.410 ;
        RECT 28.980 0.170 29.450 0.610 ;
        RECT 30.680 0.170 31.150 0.610 ;
        RECT 28.980 1.470 29.450 1.910 ;
        RECT 30.680 1.470 31.150 1.910 ;
        RECT 28.980 2.770 29.450 3.210 ;
        RECT 30.680 2.770 31.150 3.210 ;
        RECT 32.380 2.770 32.850 3.210 ;
        RECT 32.380 0.170 32.850 0.610 ;
        RECT 32.380 4.070 32.850 4.510 ;
        RECT 28.980 5.370 29.450 5.810 ;
        RECT 30.680 5.370 31.150 5.810 ;
        RECT 32.380 5.370 32.850 5.810 ;
        RECT 28.980 6.670 29.450 7.110 ;
        RECT 28.980 4.070 29.450 4.510 ;
        RECT 28.980 9.270 29.450 9.710 ;
        RECT 30.680 9.270 31.150 9.710 ;
        RECT 32.380 1.470 32.850 1.910 ;
        RECT 32.380 9.270 32.850 9.710 ;
        RECT 28.980 7.970 29.450 8.410 ;
        RECT 30.680 7.970 31.150 8.410 ;
        RECT 30.680 4.070 31.150 4.510 ;
        RECT 30.680 6.670 31.150 7.110 ;
        RECT 35.780 5.370 36.250 5.810 ;
        RECT 37.480 5.370 37.950 5.810 ;
        RECT 39.180 5.370 39.650 5.810 ;
        RECT 37.480 6.670 37.950 7.110 ;
        RECT 39.180 6.670 39.650 7.110 ;
        RECT 37.480 1.470 37.950 1.910 ;
        RECT 39.180 9.270 39.650 9.710 ;
        RECT 39.180 0.170 39.650 0.610 ;
        RECT 35.780 4.070 36.250 4.510 ;
        RECT 37.480 4.070 37.950 4.510 ;
        RECT 39.180 7.970 39.650 8.410 ;
        RECT 35.780 6.670 36.250 7.110 ;
        RECT 35.780 9.270 36.250 9.710 ;
        RECT 39.180 4.070 39.650 4.510 ;
        RECT 39.180 1.470 39.650 1.910 ;
        RECT 35.780 1.470 36.250 1.910 ;
        RECT 35.780 0.170 36.250 0.610 ;
        RECT 37.480 0.170 37.950 0.610 ;
        RECT 35.780 2.770 36.250 3.210 ;
        RECT 37.480 2.770 37.950 3.210 ;
        RECT 39.180 2.770 39.650 3.210 ;
        RECT 35.780 7.970 36.250 8.410 ;
        RECT 37.480 7.970 37.950 8.410 ;
        RECT 37.480 9.270 37.950 9.710 ;
        RECT 47.680 19.670 48.150 20.110 ;
        RECT 52.780 11.870 53.250 12.310 ;
        RECT 47.680 17.070 48.150 17.510 ;
        RECT 47.680 18.370 48.150 18.810 ;
        RECT 47.680 0.170 48.150 0.610 ;
        RECT 47.680 15.770 48.150 16.210 ;
        RECT 47.680 4.070 48.150 4.510 ;
        RECT 47.680 7.970 48.150 8.410 ;
        RECT 47.680 5.370 48.150 5.810 ;
        RECT 47.680 6.670 48.150 7.110 ;
        RECT 47.680 2.770 48.150 3.210 ;
        RECT 47.680 20.970 48.150 21.410 ;
        RECT 47.680 9.270 48.150 9.710 ;
        RECT 47.680 1.470 48.150 1.910 ;
        RECT 42.580 11.870 43.050 12.310 ;
        RECT 44.280 11.870 44.750 12.310 ;
        RECT 45.980 11.870 46.450 12.310 ;
        RECT 47.680 13.170 48.150 13.610 ;
        RECT 47.680 11.870 48.150 12.310 ;
        RECT 49.380 11.870 49.850 12.310 ;
        RECT 51.080 11.870 51.550 12.310 ;
        RECT 47.680 14.470 48.150 14.910 ;
        RECT 51.080 17.070 51.550 17.510 ;
        RECT 52.780 17.070 53.250 17.510 ;
        RECT 51.080 19.670 51.550 20.110 ;
        RECT 49.380 18.370 49.850 18.810 ;
        RECT 49.380 20.970 49.850 21.410 ;
        RECT 51.080 18.370 51.550 18.810 ;
        RECT 52.780 18.370 53.250 18.810 ;
        RECT 51.080 20.970 51.550 21.410 ;
        RECT 52.780 20.970 53.250 21.410 ;
        RECT 52.780 19.670 53.250 20.110 ;
        RECT 51.080 14.470 51.550 14.910 ;
        RECT 49.380 19.670 49.850 20.110 ;
        RECT 49.380 15.770 49.850 16.210 ;
        RECT 49.380 13.170 49.850 13.610 ;
        RECT 51.080 13.170 51.550 13.610 ;
        RECT 52.780 13.170 53.250 13.610 ;
        RECT 51.080 15.770 51.550 16.210 ;
        RECT 52.780 15.770 53.250 16.210 ;
        RECT 49.380 17.070 49.850 17.510 ;
        RECT 52.780 14.470 53.250 14.910 ;
        RECT 49.380 14.470 49.850 14.910 ;
        RECT 44.280 19.670 44.750 20.110 ;
        RECT 45.980 19.670 46.450 20.110 ;
        RECT 42.580 14.470 43.050 14.910 ;
        RECT 44.280 14.470 44.750 14.910 ;
        RECT 45.980 14.470 46.450 14.910 ;
        RECT 44.280 18.370 44.750 18.810 ;
        RECT 45.980 18.370 46.450 18.810 ;
        RECT 42.580 20.970 43.050 21.410 ;
        RECT 42.580 13.170 43.050 13.610 ;
        RECT 44.280 13.170 44.750 13.610 ;
        RECT 45.980 13.170 46.450 13.610 ;
        RECT 44.280 20.970 44.750 21.410 ;
        RECT 45.980 20.970 46.450 21.410 ;
        RECT 45.980 17.070 46.450 17.510 ;
        RECT 42.580 15.770 43.050 16.210 ;
        RECT 44.280 15.770 44.750 16.210 ;
        RECT 42.580 17.070 43.050 17.510 ;
        RECT 44.280 17.070 44.750 17.510 ;
        RECT 42.580 18.370 43.050 18.810 ;
        RECT 45.980 15.770 46.450 16.210 ;
        RECT 42.580 19.670 43.050 20.110 ;
        RECT 45.980 4.070 46.450 4.510 ;
        RECT 42.580 2.770 43.050 3.210 ;
        RECT 44.280 2.770 44.750 3.210 ;
        RECT 45.980 2.770 46.450 3.210 ;
        RECT 42.580 6.670 43.050 7.110 ;
        RECT 42.580 7.970 43.050 8.410 ;
        RECT 44.280 6.670 44.750 7.110 ;
        RECT 42.580 1.470 43.050 1.910 ;
        RECT 44.280 7.970 44.750 8.410 ;
        RECT 45.980 7.970 46.450 8.410 ;
        RECT 42.580 5.370 43.050 5.810 ;
        RECT 42.580 4.070 43.050 4.510 ;
        RECT 44.280 5.370 44.750 5.810 ;
        RECT 42.580 9.270 43.050 9.710 ;
        RECT 44.280 9.270 44.750 9.710 ;
        RECT 45.980 9.270 46.450 9.710 ;
        RECT 45.980 5.370 46.450 5.810 ;
        RECT 44.280 1.470 44.750 1.910 ;
        RECT 45.980 1.470 46.450 1.910 ;
        RECT 42.580 0.170 43.050 0.610 ;
        RECT 44.280 0.170 44.750 0.610 ;
        RECT 45.980 0.170 46.450 0.610 ;
        RECT 44.280 4.070 44.750 4.510 ;
        RECT 45.980 6.670 46.450 7.110 ;
        RECT 52.780 0.170 53.250 0.610 ;
        RECT 51.080 1.470 51.550 1.910 ;
        RECT 52.780 1.470 53.250 1.910 ;
        RECT 49.380 6.670 49.850 7.110 ;
        RECT 51.080 4.070 51.550 4.510 ;
        RECT 51.080 6.670 51.550 7.110 ;
        RECT 49.380 0.170 49.850 0.610 ;
        RECT 51.080 0.170 51.550 0.610 ;
        RECT 49.380 7.970 49.850 8.410 ;
        RECT 49.380 9.270 49.850 9.710 ;
        RECT 51.080 9.270 51.550 9.710 ;
        RECT 52.780 4.070 53.250 4.510 ;
        RECT 51.080 7.970 51.550 8.410 ;
        RECT 49.380 2.770 49.850 3.210 ;
        RECT 51.080 2.770 51.550 3.210 ;
        RECT 52.780 6.670 53.250 7.110 ;
        RECT 52.780 7.970 53.250 8.410 ;
        RECT 52.780 2.770 53.250 3.210 ;
        RECT 49.380 5.370 49.850 5.810 ;
        RECT 49.380 1.470 49.850 1.910 ;
        RECT 49.380 4.070 49.850 4.510 ;
        RECT 51.080 5.370 51.550 5.810 ;
        RECT 52.780 5.370 53.250 5.810 ;
        RECT 52.780 9.270 53.250 9.710 ;
      LAYER met4 ;
        RECT 1.300 92.820 1.800 93.320 ;
        RECT 3.000 92.820 3.500 93.320 ;
        RECT 4.700 92.820 5.200 93.320 ;
        RECT 6.400 92.820 6.900 93.320 ;
        RECT 8.100 92.820 8.600 93.320 ;
        RECT 9.800 92.820 10.300 93.320 ;
        RECT 11.500 92.820 12.000 93.320 ;
        RECT 13.200 92.820 13.700 93.320 ;
        RECT 14.900 92.820 15.400 93.320 ;
        RECT 16.600 92.820 17.100 93.320 ;
        RECT 18.300 92.820 18.800 93.320 ;
        RECT 20.000 92.820 20.500 93.320 ;
        RECT 21.700 92.820 22.200 93.320 ;
        RECT 23.400 92.820 23.900 93.320 ;
        RECT 25.100 92.820 25.600 93.320 ;
        RECT 26.800 92.820 27.300 93.320 ;
        RECT 28.500 92.820 29.000 93.320 ;
        RECT 30.200 92.820 30.700 93.320 ;
        RECT 31.900 92.820 32.400 93.320 ;
        RECT 33.600 92.820 34.100 93.320 ;
        RECT 35.300 92.820 35.800 93.320 ;
        RECT 37.000 92.820 37.500 93.320 ;
        RECT 38.700 92.820 39.200 93.320 ;
        RECT 40.400 92.820 40.900 93.320 ;
        RECT 42.100 92.820 42.600 93.320 ;
        RECT 43.800 92.820 44.300 93.320 ;
        RECT 45.500 92.820 46.000 93.320 ;
        RECT 47.200 92.820 47.700 93.320 ;
        RECT 48.900 92.820 49.400 93.320 ;
        RECT 50.600 92.820 51.100 93.320 ;
        RECT 52.300 92.820 52.800 93.320 ;
        RECT 54.000 92.820 54.500 93.320 ;
        RECT 0.000 93.680 54.500 94.220 ;
        RECT 0.000 94.530 54.500 95.070 ;
  END
END macro_array_pc_64x32_all_neg
END LIBRARY

